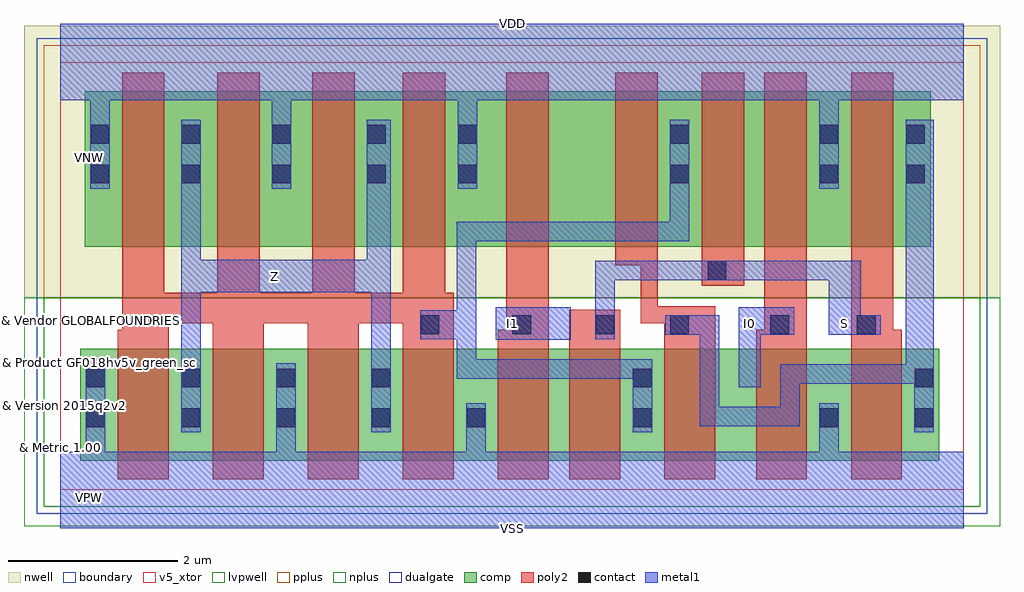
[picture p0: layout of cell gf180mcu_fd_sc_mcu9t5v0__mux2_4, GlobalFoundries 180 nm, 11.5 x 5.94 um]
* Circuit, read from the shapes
.subckt gf180mcu_fd_sc_mcu9t5v0__mux2_4 I0 I1 S VDD VNW VSS Z
XM1 Z n1 VSS VSUBS nfet_05v0 w=1.32u l=0.6u m=4
XM2 n2 I1 VSS VSUBS nfet_05v0 w=1.32u l=0.6u
XM3 n1 S n2 VSUBS nfet_05v0 w=1.32u l=0.6u
XM4 n3 n4 n1 VSUBS nfet_05v0 w=1.32u l=0.6u
XM5 VSS I0 n3 VSUBS nfet_05v0 w=1.32u l=0.6u
XM6 n4 S VSS VSUBS nfet_05v0 w=1.32u l=0.6u
XM7 Z n1 VDD VNW pfet_05v0 w=1.83u l=0.5u m=4
XM8 n5 I1 VDD VNW pfet_05v0 w=1.83u l=0.5u
XM9 n1 n4 n5 VNW pfet_05v0 w=1.83u l=0.5u
XM10 n6 S n1 VNW pfet_05v0 w=1.83u l=0.5u
XM11 VDD I0 n6 VNW pfet_05v0 w=1.83u l=0.5u
XM12 n4 S VDD VNW pfet_05v0 w=1.83u l=0.5u
.ends

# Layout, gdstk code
import gdstk
lib = gdstk.Library(unit=1e-6, precision=1e-09)
def R(c, l, rs):  # rectangles x0, y0, x1, y1
    for r in rs: c.add(gdstk.rectangle(r[:2], r[2:], *l))
def A(c, l, x, y, w, h, nx, ny, dx, dy):  # array of equal rectangles
    R(c, l, [(x+i*dx, y+j*dy, x+i*dx+w, y+j*dy+h) for i in range(nx) for j in range(ny)])
def P(c, l, *ps):  # polygons
    for p in ps: c.add(gdstk.Polygon(p, *l))
boundary = (0, 0)
nwell = (21, 0)
comp = (22, 0)
poly2 = (30, 0)
pplus = (31, 0)
nplus = (32, 0)
contact = (33, 0)
metal1 = (34, 0)
dualgate = (55, 0)
v5_xtor = (112, 1)
lvpwell = (204, 0)

gf180mcu_fd_sc_mcu9t5v0_ = lib.new_cell('gf180mcu_fd_sc_mcu9t5v0__mux2_4')
R(gf180mcu_fd_sc_mcu9t5v0_, boundary, [(0,0,10.64,5.04)])
R(gf180mcu_fd_sc_mcu9t5v0_, nwell, [(-0.43,2.265,11.07,5.47)])
R(gf180mcu_fd_sc_mcu9t5v0_, comp, [(0.235,0.345,10.355,1.665), (0.285,2.865,10.255,4.695)])
R(gf180mcu_fd_sc_mcu9t5v0_, poly2, [(5.995,0.125,6.595,2.125), (7.555,2.405,8.055,4.915)])
P(gf180mcu_fd_sc_mcu9t5v0_, poly2, [(0.675,0.125),(0.675,1.885),(0.725,1.885),(0.725,4.915),(1.225,4.915),(1.225,2.32),(1.845,2.32),(1.845,4.915),(2.345,4.915),(2.345,2.32),(2.965,2.32),(2.965,4.915),(3.465,4.915),(3.465,2.32),(4.035,2.32),(4.035,4.915),(4.535,4.915),(4.535,2.32),(4.635,2.32),(4.635,0.125),(4.035,0.125),(4.035,1.965),(3.515,1.965),(3.515,0.125),(2.915,0.125),(2.915,1.965),(2.395,1.965),(2.395,0.125),(1.795,0.125),(1.795,1.965),(1.275,1.965),(1.275,0.125)],
  [(5.155,0.125),(5.155,1.885),(5.255,1.885),(5.255,4.915),(5.755,4.915),(5.755,0.125)],
  [(7.115,0.125),(7.115,1.965),(6.835,1.965),(6.835,2.645),(6.535,2.645),(6.535,4.915),(7.035,4.915),(7.035,2.165),(7.715,2.165),(7.715,0.125)],
  [(8.195,0.125),(8.195,1.885),(8.295,1.885),(8.295,4.915),(8.795,4.915),(8.795,0.125)],
  [(9.315,0.125),(9.315,4.915),(9.815,4.915),(9.815,1.885),(9.915,1.885),(9.915,0.125)])
R(gf180mcu_fd_sc_mcu9t5v0_, pplus, [(-0.2,2.265,10.84,5.24)])
R(gf180mcu_fd_sc_mcu9t5v0_, nplus, [(-0.2,-0.2,10.84,2.265)])
A(gf180mcu_fd_sc_mcu9t5v0_, contact, 0.305, 0.74, 0.22, 0.22, 5, 1, 1.12, 0)
A(gf180mcu_fd_sc_mcu9t5v0_, contact, 0.305, 1.21, 0.22, 0.22, 4, 1, 1.12, 0)
A(gf180mcu_fd_sc_mcu9t5v0_, contact, 0.355, 3.61, 0.22, 0.22, 3, 2, 1.07, 0.47)
R(gf180mcu_fd_sc_mcu9t5v0_, contact, [(6.745,0.74,6.965,0.96), (8.945,0.74,9.165,0.96), (10.065,0.74,10.285,0.96), (6.745,1.21,6.965,1.43), (10.065,1.21,10.285,1.43), (4.245,1.835,4.465,2.055), (5.325,1.835,5.545,2.055), (6.305,1.835,6.525,2.055), (7.185,1.835,7.405,2.055), (8.365,1.835,8.585,2.055), (9.385,1.835,9.605,2.055), (7.625,2.475,7.845,2.695), (3.615,3.61,3.835,3.83), (4.685,3.61,4.905,3.83), (7.185,3.61,7.405,3.83), (8.945,3.61,9.165,3.83), (9.965,3.61,10.185,3.83), (3.615,4.08,3.835,4.3), (4.685,4.08,4.905,4.3), (7.185,4.08,7.405,4.3), (8.945,4.08,9.165,4.3), (9.965,4.08,10.185,4.3)])
R(gf180mcu_fd_sc_mcu9t5v0_, metal1, [(5.13,1.77,6.01,2.15)])
P(gf180mcu_fd_sc_mcu9t5v0_, metal1, [(1.42,0.68),(1.42,4.36),(1.65,4.36),(1.65,2.71),(3.61,2.71),(3.61,4.36),(3.89,4.36),(3.89,0.68),(3.66,0.68),(3.66,2.33),(1.65,2.33),(1.65,0.68)],
  [(6.74,0.68),(6.74,1.31),(4.67,1.31),(4.67,1.775),(4.24,1.775),(4.24,2.115),(4.67,2.115),(4.67,3.16),(7.18,3.16),(7.18,4.36),(7.41,4.36),(7.41,2.93),(4.9,2.93),(4.9,1.54),(6.97,1.54),(6.97,0.68)],
  [(7.99,1.21),(7.99,2.15),(8.645,2.15),(8.645,1.83),(8.25,1.83),(8.25,1.21)],
  [(6.3,1.775),(6.3,2.7),(9.43,2.7),(9.43,2.06),(9.665,2.06),(9.665,1.83),(9.05,1.83),(9.05,2.47),(6.53,2.47),(6.53,1.775)],
  [(10.06,0.68),(10.06,1.25),(8.71,1.25),(8.71,0.75),(7.53,0.75),(7.53,1.83),(7.125,1.83),(7.125,2.06),(7.76,2.06),(7.76,0.98),(8.48,0.98),(8.48,1.48),(9.96,1.48),(9.96,4.36),(10.29,4.36),(10.29,0.68)],
  [(0,-0.45),(0,0.45),(0.3,0.45),(0.3,1.49),(0.53,1.49),(0.53,0.45),(2.54,0.45),(2.54,1.49),(2.77,1.49),(2.77,0.45),(4.78,0.45),(4.78,1.02),(5.01,1.02),(5.01,0.45),(8.94,0.45),(8.94,1.02),(9.17,1.02),(9.17,0.45),(10.64,0.45),(10.64,-0.45)],
  [(0.35,3.55),(0.35,4.59),(0,4.59),(0,5.49),(10.64,5.49),(10.64,4.59),(9.17,4.59),(9.17,3.55),(8.94,3.55),(8.94,4.59),(4.91,4.59),(4.91,3.55),(4.68,3.55),(4.68,4.59),(2.72,4.59),(2.72,3.55),(2.49,3.55),(2.49,4.59),(0.58,4.59),(0.58,3.55)])
R(gf180mcu_fd_sc_mcu9t5v0_, dualgate, [(-0.28,-0.28,10.92,5.32)])
R(gf180mcu_fd_sc_mcu9t5v0_, v5_xtor, [(0,0,10.64,5.04)])
R(gf180mcu_fd_sc_mcu9t5v0_, lvpwell, [(-0.43,-0.43,11.07,2.265)])
gf180mcu_fd_sc_mcu9t5v0_.add(gdstk.Label('I0', (8.12,1.96), layer=34, texttype=10))
gf180mcu_fd_sc_mcu9t5v0_.add(gdstk.Label('I1', (5.32,1.96), layer=34, texttype=10))
gf180mcu_fd_sc_mcu9t5v0_.add(gdstk.Label('S', (9.24,1.96), layer=34, texttype=10))
gf180mcu_fd_sc_mcu9t5v0_.add(gdstk.Label('VDD', (5.32,5.49), layer=34, texttype=10))
gf180mcu_fd_sc_mcu9t5v0_.add(gdstk.Label('VSS', (5.32,-0.45), layer=34, texttype=10))
gf180mcu_fd_sc_mcu9t5v0_.add(gdstk.Label('Z', (2.52,2.52), layer=34, texttype=10))
gf180mcu_fd_sc_mcu9t5v0_.add(gdstk.Label('& Vendor GLOBALFOUNDRIES', (0,2), layer=63, texttype=63))
gf180mcu_fd_sc_mcu9t5v0_.add(gdstk.Label('& Product GF018hv5v_green_sc9', (0,1.5), layer=63, texttype=63))
gf180mcu_fd_sc_mcu9t5v0_.add(gdstk.Label('& Version 2015q2v2', (0,1), layer=63, texttype=63))
gf180mcu_fd_sc_mcu9t5v0_.add(gdstk.Label('& Metric 1.00', (0,0.5), layer=63, texttype=63))
gf180mcu_fd_sc_mcu9t5v0_.add(gdstk.Label('VNW', (0.345,3.92), layer=21, texttype=10))
gf180mcu_fd_sc_mcu9t5v0_.add(gdstk.Label('VPW', (0.34,-0.085), layer=204, texttype=10))

lib.write_gds('gf180mcu_fd_sc_mcu9t5v0__mux2_4.gds')
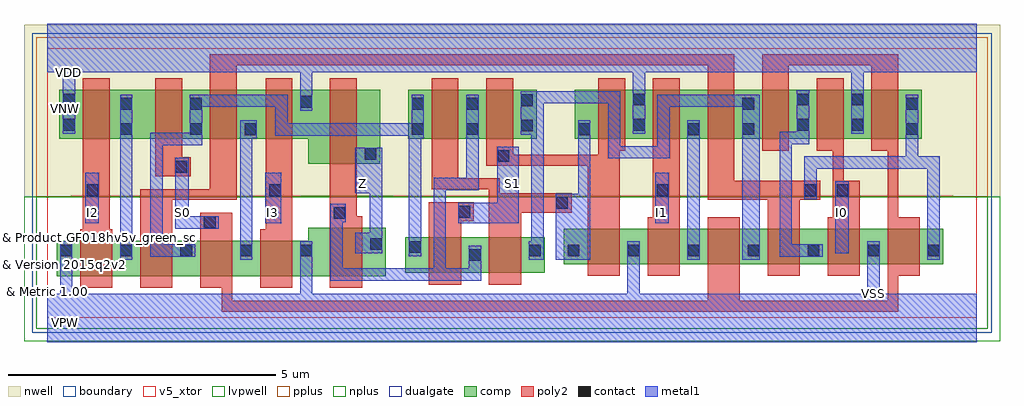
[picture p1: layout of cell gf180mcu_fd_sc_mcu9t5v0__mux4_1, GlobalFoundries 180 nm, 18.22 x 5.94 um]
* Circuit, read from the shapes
.subckt gf180mcu_fd_sc_mcu9t5v0__mux4_1 I0 I1 I2 I3 S0 S1 VDD VNW VSS Z
XM1 n1 I2 VSS VSUBS nfet_05v0 w=0.66u l=0.6u
XM2 n2 n3 n1 VSUBS nfet_05v0 w=0.66u l=0.6u
XM3 n4 S0 n2 VSUBS nfet_05v0 w=0.66u l=0.6u
XM4 VSS I3 n4 VSUBS nfet_05v0 w=0.66u l=0.6u
XM5 Z n5 VSS VSUBS nfet_05v0 w=0.9u l=0.6u
XM6 n5 S1 n2 VSUBS nfet_05v0 w=0.66u l=0.6u
XM7 n6 n7 n5 VSUBS nfet_05v0 w=0.66u l=0.6u
XM8 VSS S1 n7 VSUBS nfet_05v0 w=0.66u l=0.6u
XM9 n8 I1 VSS VSUBS nfet_05v0 w=0.66u l=0.6u
XM10 n6 S0 n8 VSUBS nfet_05v0 w=0.66u l=0.6u
XM11 n9 n3 n6 VSUBS nfet_05v0 w=0.66u l=0.6u
XM12 VSS I0 n9 VSUBS nfet_05v0 w=0.66u l=0.6u
XM13 n3 S0 VSS VSUBS nfet_05v0 w=0.66u l=0.6u
XM14 n1 I2 VDD VNW pfet_05v0 w=0.915u l=0.5u
XM15 n2 S0 n1 VNW pfet_05v0 w=0.915u l=0.5u
XM16 n4 n3 n2 VNW pfet_05v0 w=0.915u l=0.5u
XM17 VDD I3 n4 VNW pfet_05v0 w=0.915u l=0.5u
XM18 Z n5 VDD VNW pfet_05v0 w=1.38u l=0.5u
XM19 n5 n7 n2 VNW pfet_05v0 w=0.915u l=0.5u
XM20 n6 S1 n5 VNW pfet_05v0 w=0.915u l=0.5u
XM21 VDD S1 n7 VNW pfet_05v0 w=0.915u l=0.5u
XM22 n8 I1 VDD VNW pfet_05v0 w=0.915u l=0.5u
XM23 n6 n3 n8 VNW pfet_05v0 w=0.915u l=0.5u
XM24 n9 S0 n6 VNW pfet_05v0 w=0.915u l=0.5u
XM25 VDD I0 n9 VNW pfet_05v0 w=0.915u l=0.5u
XM26 n3 S0 VDD VNW pfet_05v0 w=0.915u l=0.5u
.ends

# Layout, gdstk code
import gdstk
lib = gdstk.Library(unit=1e-6, precision=1e-09)
def R(c, l, rs):  # rectangles x0, y0, x1, y1
    for r in rs: c.add(gdstk.rectangle(r[:2], r[2:], *l))
def A(c, l, x, y, w, h, nx, ny, dx, dy):  # array of equal rectangles
    R(c, l, [(x+i*dx, y+j*dy, x+i*dx+w, y+j*dy+h) for i in range(nx) for j in range(ny)])
def P(c, l, *ps):  # polygons
    for p in ps: c.add(gdstk.Polygon(p, *l))
boundary = (0, 0)
nwell = (21, 0)
comp = (22, 0)
poly2 = (30, 0)
pplus = (31, 0)
nplus = (32, 0)
contact = (33, 0)
metal1 = (34, 0)
dualgate = (55, 0)
v5_xtor = (112, 1)
lvpwell = (204, 0)

gf180mcu_fd_sc_mcu9t5v0_ = lib.new_cell('gf180mcu_fd_sc_mcu9t5v0__mux4_1')
R(gf180mcu_fd_sc_mcu9t5v0_, boundary, [(0,0,17.36,5.04)])
P(gf180mcu_fd_sc_mcu9t5v0_, nwell, [(-0.43,2.265),(-0.43,5.47),(17.79,5.47),(17.79,2.265),(16.93,2.265),(16.93,2.28),(0.43,2.28),(0.43,2.265)])
R(gf180mcu_fd_sc_mcu9t5v0_, comp, [(6.69,0.845,9.29,1.505), (9.65,1.005,16.73,1.665), (6.74,3.345,9.14,4.26), (9.85,3.345,16.33,4.26)])
P(gf180mcu_fd_sc_mcu9t5v0_, comp, [(4.88,2.88),(4.88,3.345),(0.23,3.345),(0.23,4.26),(6.22,4.26),(6.22,2.88)],
  [(0.18,0.78),(0.18,1.44),(4.88,1.44),(4.88,1.68),(6.32,1.68),(6.32,0.78)])
P(gf180mcu_fd_sc_mcu9t5v0_, poly2, [(0.62,0.56),(0.62,1.66),(0.67,1.66),(0.67,4.48),(1.17,4.48),(1.17,1.66),(1.22,1.66),(1.22,0.56)],
  [(2.02,2.645),(2.02,4.48),(2.52,4.48),(2.52,3.005),(2.685,3.005),(2.685,2.645)],
  [(3.98,0.56),(3.98,1.66),(4.08,1.66),(4.08,4.48),(4.58,4.48),(4.58,0.56)],
  [(5.28,0.56),(5.28,4.48),(5.78,4.48),(5.78,1.9),(5.88,1.9),(5.88,0.56)],
  [(7.13,0.625),(7.13,2.165),(7.97,2.165),(7.97,1.805),(7.73,1.805),(7.73,0.625)],
  [(8.25,0.625),(8.25,2.405),(7.18,2.405),(7.18,4.48),(7.68,4.48),(7.68,2.605),(8.45,2.605),(8.45,2.325),(9.795,2.325),(9.795,1.965),(8.85,1.965),(8.85,0.625)],
  [(10.09,0.785),(10.09,2.845),(8.2,2.845),(8.2,4.48),(8.7,4.48),(8.7,3.045),(10.29,3.045),(10.29,4.48),(10.79,4.48),(10.79,3.125),(10.69,3.125),(10.69,0.785)],
  [(11.21,0.785),(11.21,1.885),(11.31,1.885),(11.31,4.48),(11.81,4.48),(11.81,0.785)],
  [(1.74,0.56),(1.74,2.405),(3.04,2.405),(3.04,4.92),(12.83,4.92),(12.83,2.565),(14.43,2.565),(14.43,2.205),(14.05,2.205),(14.05,0.785),(13.45,0.785),(13.45,2.205),(12.33,2.205),(12.33,4.72),(3.54,4.72),(3.54,2.205),(2.34,2.205),(2.34,0.56)],
  [(14.57,0.785),(14.57,1.885),(14.67,1.885),(14.67,3.125),(14.37,3.125),(14.37,4.48),(14.87,4.48),(14.87,2.565),(15.17,2.565),(15.17,0.785)],
  [(3.26,0.12),(3.26,0.56),(2.86,0.56),(2.86,1.965),(3.46,1.965),(3.46,0.32),(12.33,0.32),(12.33,1.885),(12.93,1.885),(12.93,0.32),(15.69,0.32),(15.69,3.125),(15.39,3.125),(15.39,4.72),(13.85,4.72),(13.85,3.125),(13.35,3.125),(13.35,4.92),(15.89,4.92),(15.89,1.885),(16.29,1.885),(16.29,0.785),(15.89,0.785),(15.89,0.12)])
R(gf180mcu_fd_sc_mcu9t5v0_, pplus, [(-0.2,2.265,17.56,5.24)])
R(gf180mcu_fd_sc_mcu9t5v0_, nplus, [(-0.2,-0.2,17.56,2.265)])
A(gf180mcu_fd_sc_mcu9t5v0_, contact, 0.25, 1.15, 0.22, 0.22, 5, 1, 1.12, 0)
A(gf180mcu_fd_sc_mcu9t5v0_, contact, 9.72, 1.15, 0.22, 0.22, 7, 1, 1.12, 0)
R(gf180mcu_fd_sc_mcu9t5v0_, contact, [(7.88,1.065,8.1,1.285), (9,1.15,9.22,1.37), (6.76,1.215,6.98,1.435), (6.03,1.27,6.25,1.49), (2.93,1.675,3.15,1.895), (5.35,1.85,5.57,2.07), (7.68,1.875,7.9,2.095), (9.505,2.035,9.725,2.255), (0.74,2.275,0.96,2.495), (4.15,2.275,4.37,2.495), (11.38,2.275,11.6,2.495), (14.14,2.275,14.36,2.495), (14.74,2.275,14.96,2.495), (2.395,2.715,2.615,2.935), (8.41,2.915,8.63,3.135), (5.93,2.95,6.15,3.17), (3.69,3.415,3.91,3.635), (9.92,3.415,10.14,3.635), (11.96,3.415,12.18,3.635), (1.37,3.42,1.59,3.64), (2.67,3.42,2.89,3.64), (6.81,3.42,7.03,3.64), (7.83,3.42,8.05,3.64), (12.98,3.42,13.2,3.64), (16.04,3.42,16.26,3.64), (8.85,3.485,9.07,3.705), (0.3,3.5,0.52,3.72), (10.94,3.5,11.16,3.72), (14,3.5,14.22,3.72), (15.02,3.5,15.24,3.72), (1.37,3.89,1.59,4.11), (2.67,3.89,2.89,4.11), (6.81,3.89,7.03,4.11), (7.83,3.89,8.05,4.11), (12.98,3.89,13.2,4.11), (16.04,3.89,16.26,4.11), (4.73,3.925,4.95,4.145), (8.85,3.955,9.07,4.175), (0.3,3.97,0.52,4.19), (10.94,3.97,11.16,4.19), (14,3.97,14.22,4.19), (15.02,3.97,15.24,4.19)])
R(gf180mcu_fd_sc_mcu9t5v0_, metal1, [(1.365,1.09,1.595,4.17), (11.955,1.09,12.185,3.695), (14.71,1.21,14.97,2.555), (0.71,1.77,0.97,2.71), (4.07,1.77,4.375,2.71), (11.35,1.77,11.61,2.71)])
P(gf180mcu_fd_sc_mcu9t5v0_, metal1, [(2.39,1.67),(2.39,2.995),(2.65,2.995),(2.65,1.9),(3.21,1.9),(3.21,1.67)],
  [(3.605,1.09),(3.605,3.695),(3.915,3.695),(3.915,3.355),(3.835,3.355),(3.835,1.09)],
  [(5.75,1.21),(5.75,1.59),(6.025,1.59),(6.025,2.33),(5.75,2.33),(5.75,3.175),(6.255,3.175),(6.255,1.21)],
  [(1.93,1.145),(1.93,3.455),(2.665,3.455),(2.665,4.17),(4.495,4.17),(4.495,3.635),(6.805,3.635),(6.805,4.17),(7.035,4.17),(7.035,3.36),(6.985,3.36),(6.985,1.155),(6.755,1.155),(6.755,3.405),(4.265,3.405),(4.265,3.94),(2.895,3.94),(2.895,3.225),(2.16,3.225),(2.16,1.375),(2.77,1.375),(2.77,1.145)],
  [(5.29,0.695),(5.29,2.13),(5.575,2.13),(5.575,1.79),(5.52,1.79),(5.52,0.925),(7.215,0.925),(7.215,2.615),(7.825,2.615),(7.825,4.17),(8.055,4.17),(8.055,2.385),(7.445,2.385),(7.445,0.925),(7.875,0.925),(7.875,1.345),(8.105,1.345),(8.105,0.695)],
  [(7.675,1.77),(7.675,2.155),(8.405,2.155),(8.405,3.195),(8.81,3.195),(8.81,1.77)],
  [(9.5,1.09),(9.5,2.315),(9.915,2.315),(9.915,3.695),(10.145,3.695),(10.145,1.09)],
  [(8.995,1.09),(8.995,1.43),(9.04,1.43),(9.04,3.425),(8.845,3.425),(8.845,4.235),(10.705,4.235),(10.705,3.21),(11.395,3.21),(11.395,4.17),(13.305,4.17),(13.305,1.09),(12.975,1.09),(12.975,3.94),(11.625,3.94),(11.625,2.98),(10.475,2.98),(10.475,4.005),(9.27,4.005),(9.27,1.09)],
  [(13.675,1.145),(13.675,3.475),(13.995,3.475),(13.995,4.25),(14.225,4.25),(14.225,3.245),(13.905,3.245),(13.905,1.375),(14.48,1.375),(14.48,1.145)],
  [(16.435,1.09),(16.435,2.785),(14.365,2.785),(14.365,2.215),(14.135,2.215),(14.135,3.015),(16.035,3.015),(16.035,4.17),(16.265,4.17),(16.265,3.015),(16.665,3.015),(16.665,1.09)],
  [(0,-0.45),(0,0.45),(0.245,0.45),(0.245,1.43),(0.475,1.43),(0.475,0.45),(4.725,0.45),(4.725,1.43),(4.955,1.43),(4.955,0.45),(10.835,0.45),(10.835,1.43),(11.065,1.43),(11.065,0.45),(15.315,0.45),(15.315,1.43),(15.545,1.43),(15.545,0.45),(17.36,0.45),(17.36,-0.45)],
  [(0.295,3.44),(0.295,4.59),(0,4.59),(0,5.49),(17.36,5.49),(17.36,4.59),(15.245,4.59),(15.245,3.44),(15.015,3.44),(15.015,4.59),(11.165,4.59),(11.165,3.44),(10.935,3.44),(10.935,4.59),(4.955,4.59),(4.955,3.865),(4.725,3.865),(4.725,4.59),(0.525,4.59),(0.525,3.44)])
R(gf180mcu_fd_sc_mcu9t5v0_, dualgate, [(-0.28,-0.28,17.64,5.32)])
R(gf180mcu_fd_sc_mcu9t5v0_, v5_xtor, [(0,0,17.36,5.04)])
P(gf180mcu_fd_sc_mcu9t5v0_, lvpwell, [(-0.43,-0.43),(-0.43,2.265),(4.745,2.265),(4.745,2.28),(6.455,2.28),(6.455,2.265),(17.79,2.265),(17.79,-0.43)])
gf180mcu_fd_sc_mcu9t5v0_.add(gdstk.Label('I0', (14.84,1.96), layer=34, texttype=10))
gf180mcu_fd_sc_mcu9t5v0_.add(gdstk.Label('I1', (11.48,1.96), layer=34, texttype=10))
gf180mcu_fd_sc_mcu9t5v0_.add(gdstk.Label('I2', (0.84,1.96), layer=34, texttype=10))
gf180mcu_fd_sc_mcu9t5v0_.add(gdstk.Label('I3', (4.2,1.96), layer=34, texttype=10))
gf180mcu_fd_sc_mcu9t5v0_.add(gdstk.Label('S0', (2.52,1.96), layer=34, texttype=10))
gf180mcu_fd_sc_mcu9t5v0_.add(gdstk.Label('S1', (8.68,2.52), layer=34, texttype=10))
gf180mcu_fd_sc_mcu9t5v0_.add(gdstk.Label('VDD', (0.41,4.59), layer=34, texttype=10))
gf180mcu_fd_sc_mcu9t5v0_.add(gdstk.Label('VSS', (15.43,0.45), layer=34, texttype=10))
gf180mcu_fd_sc_mcu9t5v0_.add(gdstk.Label('Z', (5.88,2.52), layer=34, texttype=10))
gf180mcu_fd_sc_mcu9t5v0_.add(gdstk.Label('& Vendor GLOBALFOUNDRIES', (0,2), layer=63, texttype=63))
gf180mcu_fd_sc_mcu9t5v0_.add(gdstk.Label('& Product GF018hv5v_green_sc9', (0,1.5), layer=63, texttype=63))
gf180mcu_fd_sc_mcu9t5v0_.add(gdstk.Label('& Version 2015q2v2', (0,1), layer=63, texttype=63))
gf180mcu_fd_sc_mcu9t5v0_.add(gdstk.Label('& Metric 1.00', (0,0.5), layer=63, texttype=63))
gf180mcu_fd_sc_mcu9t5v0_.add(gdstk.Label('VNW', (0.345,3.92), layer=21, texttype=10))
gf180mcu_fd_sc_mcu9t5v0_.add(gdstk.Label('VPW', (0.34,-0.085), layer=204, texttype=10))

lib.write_gds('gf180mcu_fd_sc_mcu9t5v0__mux4_1.gds')
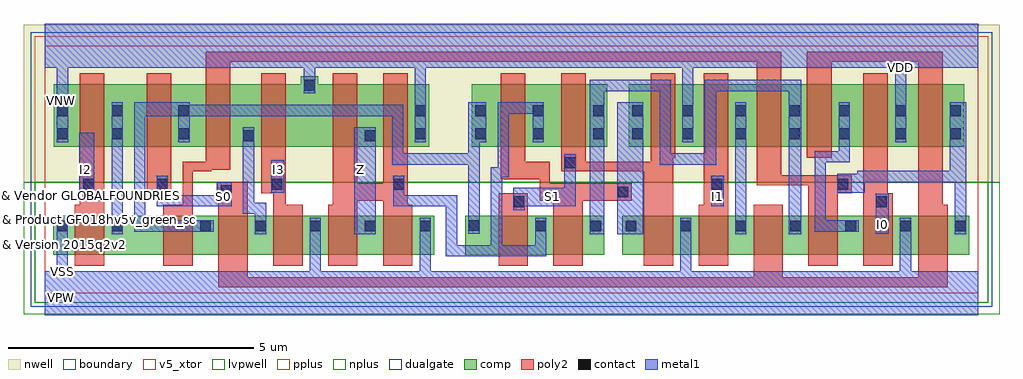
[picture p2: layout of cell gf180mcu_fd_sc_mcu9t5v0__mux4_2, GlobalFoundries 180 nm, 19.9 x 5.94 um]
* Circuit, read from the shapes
.subckt gf180mcu_fd_sc_mcu9t5v0__mux4_2 I0 I1 I2 I3 S0 S1 VDD VNW VSS Z
XM1 n1 I2 VSS VSUBS nfet_05v0 w=0.8u l=0.6u
XM2 n2 n3 n1 VSUBS nfet_05v0 w=0.8u l=0.6u
XM3 n4 S0 n2 VSUBS nfet_05v0 w=0.8u l=0.6u
XM4 VSS I3 n4 VSUBS nfet_05v0 w=0.8u l=0.6u
XM5 Z n5 VSS VSUBS nfet_05v0 w=0.8u l=0.6u m=2
XM6 n5 S1 n2 VSUBS nfet_05v0 w=0.8u l=0.6u
XM7 n6 n7 n5 VSUBS nfet_05v0 w=0.8u l=0.6u
XM8 VSS S1 n7 VSUBS nfet_05v0 w=0.8u l=0.6u
XM9 n8 I1 VSS VSUBS nfet_05v0 w=0.8u l=0.6u
XM10 n6 S0 n8 VSUBS nfet_05v0 w=0.8u l=0.6u
XM11 n9 n3 n6 VSUBS nfet_05v0 w=0.8u l=0.6u
XM12 VSS I0 n9 VSUBS nfet_05v0 w=0.8u l=0.6u
XM13 n3 S0 VSS VSUBS nfet_05v0 w=0.8u l=0.6u
XM14 n1 I2 VDD VNW pfet_05v0 w=1.28u l=0.5u
XM15 n2 S0 n1 VNW pfet_05v0 w=1.28u l=0.5u
XM16 n4 n3 n2 VNW pfet_05v0 w=1.28u l=0.5u
XM17 VDD I3 n4 VNW pfet_05v0 w=1.28u l=0.5u
XM18 Z n5 VDD VNW pfet_05v0 w=1.28u l=0.5u m=2
XM19 n5 n7 n2 VNW pfet_05v0 w=1.28u l=0.5u
XM20 n6 S1 n5 VNW pfet_05v0 w=1.28u l=0.5u
XM21 VDD S1 n7 VNW pfet_05v0 w=1.28u l=0.5u
XM22 n8 I1 VDD VNW pfet_05v0 w=1.28u l=0.5u
XM23 n6 n3 n8 VNW pfet_05v0 w=1.28u l=0.5u
XM24 n9 S0 n6 VNW pfet_05v0 w=1.28u l=0.5u
XM25 VDD I0 n9 VNW pfet_05v0 w=1.28u l=0.5u
XM26 n3 S0 VDD VNW pfet_05v0 w=1.28u l=0.5u
.ends

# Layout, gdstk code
import gdstk
lib = gdstk.Library(unit=1e-6, precision=1e-09)
def R(c, l, rs):  # rectangles x0, y0, x1, y1
    for r in rs: c.add(gdstk.rectangle(r[:2], r[2:], *l))
def A(c, l, x, y, w, h, nx, ny, dx, dy):  # array of equal rectangles
    R(c, l, [(x+i*dx, y+j*dy, x+i*dx+w, y+j*dy+h) for i in range(nx) for j in range(ny)])
def P(c, l, *ps):  # polygons
    for p in ps: c.add(gdstk.Polygon(p, *l))
boundary = (0, 0)
nwell = (21, 0)
comp = (22, 0)
poly2 = (30, 0)
pplus = (31, 0)
nplus = (32, 0)
contact = (33, 0)
metal1 = (34, 0)
dualgate = (55, 0)
v5_xtor = (112, 1)
lvpwell = (204, 0)

gf180mcu_fd_sc_mcu9t5v0_ = lib.new_cell('gf180mcu_fd_sc_mcu9t5v0__mux4_2')
R(gf180mcu_fd_sc_mcu9t5v0_, boundary, [(0,0,19.04,5.04)])
R(gf180mcu_fd_sc_mcu9t5v0_, nwell, [(-0.43,2.265,19.47,5.47)])
R(gf180mcu_fd_sc_mcu9t5v0_, comp, [(0.18,0.78,7.94,1.58), (8.575,0.78,11.415,1.58), (11.775,0.78,18.855,1.58), (8.71,2.98,11.475,4.26), (11.915,2.98,18.755,4.26)])
P(gf180mcu_fd_sc_mcu9t5v0_, comp, [(0.185,2.98),(0.185,4.26),(5.22,4.26),(5.22,4.42),(5.58,4.42),(5.58,4.26),(7.84,4.26),(7.84,2.98)])
R(gf180mcu_fd_sc_mcu9t5v0_, poly2, [(9.255,0.56,9.855,2.04), (2.08,2.04,2.58,4.48)])
P(gf180mcu_fd_sc_mcu9t5v0_, poly2, [(0.62,0.56),(0.62,1.8),(0.72,1.8),(0.72,4.48),(1.22,4.48),(1.22,0.56)],
  [(4.66,0.56),(4.66,2.04),(4.42,2.04),(4.42,4.48),(4.92,4.48),(4.92,1.8),(5.26,1.8),(5.26,0.56)],
  [(5.78,0.56),(5.78,1.8),(5.88,1.8),(5.88,4.48),(6.38,4.48),(6.38,2.24),(6.9,2.24),(6.9,4.48),(7.4,4.48),(7.4,1.8),(7.5,1.8),(7.5,0.56),(6.9,0.56),(6.9,1.88),(6.38,1.88),(6.38,0.56)],
  [(10.375,0.56),(10.375,1.88),(10.095,1.88),(10.095,2.32),(9.305,2.32),(9.305,4.48),(9.805,4.48),(9.805,2.68),(10.295,2.68),(10.295,2.24),(11.975,2.24),(11.975,1.88),(10.975,1.88),(10.975,0.56)],
  [(12.215,0.56),(12.215,2.48),(10.535,2.48),(10.535,4.48),(11.035,4.48),(11.035,2.68),(12.355,2.68),(12.355,4.48),(12.855,4.48),(12.855,2.76),(12.815,2.76),(12.815,0.56)],
  [(13.335,0.56),(13.335,1.8),(13.435,1.8),(13.435,4.48),(13.935,4.48),(13.935,0.56)],
  [(2.42,0.56),(2.42,1.8),(2.82,1.8),(2.82,2.68),(3.29,2.68),(3.29,4.92),(15.025,4.92),(15.025,2.4),(16.455,2.4),(16.455,2.04),(16.175,2.04),(16.175,0.56),(15.575,0.56),(15.575,2.2),(14.525,2.2),(14.525,4.72),(3.79,4.72),(3.79,2.51),(3.4,2.51),(3.4,2.48),(3.02,2.48),(3.02,0.56)],
  [(16.695,0.56),(16.695,4.48),(17.195,4.48),(17.195,2.04),(17.295,2.04),(17.295,0.56)],
  [(3.54,0.12),(3.54,1.91),(3.52,1.91),(3.52,2.27),(4.14,2.27),(4.14,0.32),(14.455,0.32),(14.455,1.8),(15.055,1.8),(15.055,0.32),(17.815,0.32),(17.815,4.72),(16.045,4.72),(16.045,2.76),(15.545,2.76),(15.545,4.92),(18.315,4.92),(18.315,1.8),(18.415,1.8),(18.415,0.12)])
R(gf180mcu_fd_sc_mcu9t5v0_, pplus, [(-0.2,2.265,19.24,5.24)])
R(gf180mcu_fd_sc_mcu9t5v0_, nplus, [(-0.2,-0.2,19.24,2.265)])
A(gf180mcu_fd_sc_mcu9t5v0_, contact, 3.17, 1.26, 0.22, 0.22, 5, 1, 1.12, 0)
A(gf180mcu_fd_sc_mcu9t5v0_, contact, 11.845, 1.26, 0.22, 0.22, 7, 1, 1.12, 0)
R(gf180mcu_fd_sc_mcu9t5v0_, contact, [(0.25,1.26,0.47,1.48), (1.37,1.26,1.59,1.48), (10.005,1.26,10.225,1.48), (11.125,1.26,11.345,1.48), (8.645,1.27,8.865,1.49), (9.565,1.75,9.785,1.97), (16.955,1.75,17.175,1.97), (11.685,1.95,11.905,2.17), (3.59,1.98,3.81,2.2), (0.79,2.11,1.01,2.33), (2.29,2.11,2.51,2.33), (4.63,2.11,4.85,2.33), (7.11,2.11,7.33,2.33), (13.595,2.11,13.815,2.33), (16.165,2.11,16.385,2.33), (10.605,2.55,10.825,2.77), (4.05,3.1,4.27,3.32), (6.53,3.1,6.75,3.32), (0.255,3.14,0.475,3.36), (1.37,3.14,1.59,3.36), (2.73,3.14,2.95,3.36), (7.55,3.14,7.77,3.36), (8.78,3.14,9,3.36), (9.955,3.14,10.175,3.36), (11.185,3.14,11.405,3.36), (11.985,3.14,12.205,3.36), (13.005,3.14,13.225,3.36), (14.085,3.14,14.305,3.36), (15.175,3.14,15.395,3.36), (16.195,3.14,16.415,3.36), (17.345,3.14,17.565,3.36), (18.465,3.14,18.685,3.36), (0.255,3.61,0.475,3.83), (1.37,3.61,1.59,3.83), (2.73,3.61,2.95,3.83), (7.55,3.61,7.77,3.83), (8.78,3.61,9,3.83), (9.955,3.61,10.175,3.83), (11.185,3.61,11.405,3.83), (11.985,3.61,12.205,3.83), (13.005,3.61,13.225,3.83), (14.085,3.61,14.305,3.83), (15.175,3.61,15.395,3.83), (16.195,3.61,16.415,3.83), (17.345,3.61,17.565,3.83), (18.465,3.61,18.685,3.83), (5.29,4.13,5.51,4.35)])
R(gf180mcu_fd_sc_mcu9t5v0_, metal1, [(1.365,1.2,1.595,3.89), (6.31,1.2,6.755,3.38), (11.68,1.2,12.21,3.89), (14.08,1.2,14.31,3.89), (16.95,1.21,17.21,2.03), (13.59,1.77,13.85,2.39), (0.71,2.05,1.015,3.27), (4.625,2.05,4.89,2.71)])
P(gf180mcu_fd_sc_mcu9t5v0_, metal1, [(2.285,1.77),(2.285,2.39),(2.515,2.39),(2.515,2),(3.51,2),(3.51,2.26),(3.815,2.26),(3.815,1.77)],
  [(4.285,1.2),(4.285,1.615),(4.045,1.615),(4.045,3.38),(4.275,3.38),(4.275,1.845),(4.515,1.845),(4.515,1.2)],
  [(8.64,1.21),(8.64,2.62),(7.085,2.62),(7.085,3.61),(2.955,3.61),(2.955,3.08),(2.725,3.08),(2.725,3.61),(2.055,3.61),(2.055,1.485),(3.45,1.485),(3.45,1.255),(1.825,1.255),(1.825,3.89),(2.955,3.89),(2.955,3.84),(7.315,3.84),(7.315,2.85),(8.64,2.85),(8.64,3.89),(9.005,3.89),(9.005,3.08),(8.87,3.08),(8.87,1.21)],
  [(8.18,0.75),(8.18,1.77),(7.105,1.77),(7.105,2.39),(7.335,2.39),(7.335,2),(8.41,2),(8.41,0.98),(9.1,0.98),(9.1,2.57),(9.235,2.57),(9.235,3.89),(10.18,3.89),(10.18,3.08),(9.95,3.08),(9.95,3.66),(9.465,3.66),(9.465,2.36),(9.33,2.36),(9.33,0.98),(10,0.98),(10,1.54),(10.23,1.54),(10.23,0.75)],
  [(9.56,1.69),(9.56,2.15),(10.6,2.15),(10.6,2.83),(10.83,2.83),(10.83,1.77),(9.79,1.77),(9.79,1.69)],
  [(11.12,1.2),(11.12,4.35),(12.77,4.35),(12.77,2.85),(13.46,2.85),(13.46,4.35),(15.43,4.35),(15.43,1.2),(15.17,1.2),(15.17,4.12),(13.69,4.12),(13.69,2.62),(12.54,2.62),(12.54,4.12),(11.41,4.12),(11.41,1.2)],
  [(15.7,1.255),(15.7,2.895),(16.19,2.895),(16.19,3.89),(16.42,3.89),(16.42,2.665),(15.93,2.665),(15.93,1.485),(16.605,1.485),(16.605,1.255)],
  [(18.56,1.2),(18.56,2.26),(16.72,2.26),(16.72,2.05),(16.16,2.05),(16.16,2.435),(16.57,2.435),(16.57,2.49),(18.46,2.49),(18.46,3.89),(18.79,3.89),(18.79,1.2)],
  [(0,-0.45),(0,0.45),(0.245,0.45),(0.245,1.54),(0.475,1.54),(0.475,0.45),(5.405,0.45),(5.405,1.54),(5.635,1.54),(5.635,0.45),(7.645,0.45),(7.645,1.54),(7.875,1.54),(7.875,0.45),(12.96,0.45),(12.96,1.54),(13.19,1.54),(13.19,0.45),(17.44,0.45),(17.44,1.54),(17.67,1.54),(17.67,0.45),(19.04,0.45),(19.04,-0.45)],
  [(0.25,3.08),(0.25,4.59),(0,4.59),(0,5.49),(19.04,5.49),(19.04,4.59),(17.57,4.59),(17.57,3.08),(17.34,3.08),(17.34,4.59),(13.23,4.59),(13.23,3.08),(13,3.08),(13,4.59),(7.775,4.59),(7.775,3.08),(7.545,3.08),(7.545,4.59),(5.515,4.59),(5.515,4.07),(5.285,4.07),(5.285,4.59),(0.48,4.59),(0.48,3.08)])
R(gf180mcu_fd_sc_mcu9t5v0_, dualgate, [(-0.28,-0.28,19.32,5.32)])
R(gf180mcu_fd_sc_mcu9t5v0_, v5_xtor, [(0,0,19.04,5.04)])
R(gf180mcu_fd_sc_mcu9t5v0_, lvpwell, [(-0.43,-0.43,19.47,2.265)])
gf180mcu_fd_sc_mcu9t5v0_.add(gdstk.Label('I0', (17.08,1.4), layer=34, texttype=10))
gf180mcu_fd_sc_mcu9t5v0_.add(gdstk.Label('I1', (13.72,1.96), layer=34, texttype=10))
gf180mcu_fd_sc_mcu9t5v0_.add(gdstk.Label('I2', (0.84,2.52), layer=34, texttype=10))
gf180mcu_fd_sc_mcu9t5v0_.add(gdstk.Label('I3', (4.76,2.52), layer=34, texttype=10))
gf180mcu_fd_sc_mcu9t5v0_.add(gdstk.Label('S0', (3.64,1.96), layer=34, texttype=10))
gf180mcu_fd_sc_mcu9t5v0_.add(gdstk.Label('S1', (10.36,1.96), layer=34, texttype=10))
gf180mcu_fd_sc_mcu9t5v0_.add(gdstk.Label('VDD', (17.455,4.59), layer=34, texttype=10))
gf180mcu_fd_sc_mcu9t5v0_.add(gdstk.Label('VSS', (0.36,0.45), layer=34, texttype=10))
gf180mcu_fd_sc_mcu9t5v0_.add(gdstk.Label('Z', (6.44,2.52), layer=34, texttype=10))
gf180mcu_fd_sc_mcu9t5v0_.add(gdstk.Label('& Vendor GLOBALFOUNDRIES', (0,2), layer=63, texttype=63))
gf180mcu_fd_sc_mcu9t5v0_.add(gdstk.Label('& Product GF018hv5v_green_sc9', (0,1.5), layer=63, texttype=63))
gf180mcu_fd_sc_mcu9t5v0_.add(gdstk.Label('& Version 2015q2v2', (0,1), layer=63, texttype=63))
gf180mcu_fd_sc_mcu9t5v0_.add(gdstk.Label('& Metric 1.00', (0,0.5), layer=63, texttype=63))
gf180mcu_fd_sc_mcu9t5v0_.add(gdstk.Label('VNW', (0.345,3.92), layer=21, texttype=10))
gf180mcu_fd_sc_mcu9t5v0_.add(gdstk.Label('VPW', (0.34,-0.085), layer=204, texttype=10))

lib.write_gds('gf180mcu_fd_sc_mcu9t5v0__mux4_2.gds')
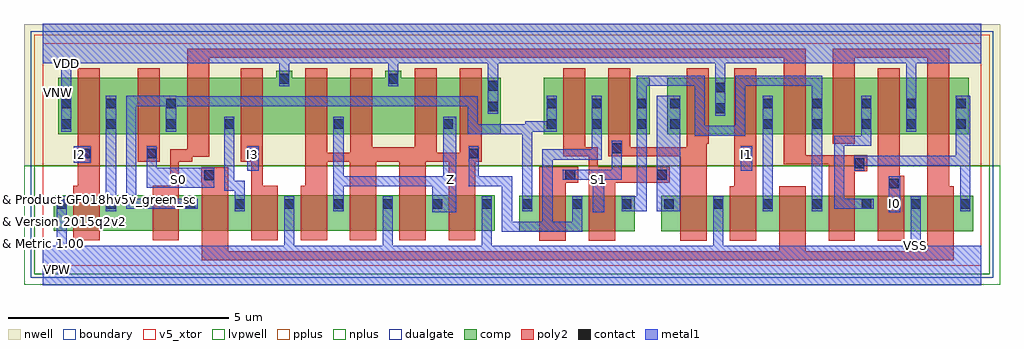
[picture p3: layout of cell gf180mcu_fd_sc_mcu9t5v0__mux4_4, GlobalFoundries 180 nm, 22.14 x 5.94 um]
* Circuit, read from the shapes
.subckt gf180mcu_fd_sc_mcu9t5v0__mux4_4 I0 I1 I2 I3 S0 S1 VDD VNW VSS Z
XM1 n1 I2 VSS VSUBS nfet_05v0 w=0.8u l=0.6u
XM2 n2 n3 n1 VSUBS nfet_05v0 w=0.8u l=0.6u
XM3 n4 S0 n2 VSUBS nfet_05v0 w=0.8u l=0.6u
XM4 VSS I3 n4 VSUBS nfet_05v0 w=0.8u l=0.6u
XM5 Z n5 VSS VSUBS nfet_05v0 w=0.8u l=0.6u m=4
XM6 n5 S1 n2 VSUBS nfet_05v0 w=0.8u l=0.6u
XM7 n6 n7 n5 VSUBS nfet_05v0 w=0.8u l=0.6u
XM8 VSS S1 n7 VSUBS nfet_05v0 w=0.8u l=0.6u
XM9 n8 I1 VSS VSUBS nfet_05v0 w=0.8u l=0.6u
XM10 n6 S0 n8 VSUBS nfet_05v0 w=0.8u l=0.6u
XM11 n9 n3 n6 VSUBS nfet_05v0 w=0.8u l=0.6u
XM12 VSS I0 n9 VSUBS nfet_05v0 w=0.8u l=0.6u
XM13 n3 S0 VSS VSUBS nfet_05v0 w=0.8u l=0.6u
XM14 n1 I2 VDD VNW pfet_05v0 w=1.28u l=0.5u
XM15 n2 S0 n1 VNW pfet_05v0 w=1.28u l=0.5u
XM16 n4 n3 n2 VNW pfet_05v0 w=1.28u l=0.5u
XM17 VDD I3 n4 VNW pfet_05v0 w=1.28u l=0.5u
XM18 Z n5 VDD VNW pfet_05v0 w=1.28u l=0.5u m=4
XM19 n5 n7 n2 VNW pfet_05v0 w=1.28u l=0.5u
XM20 n6 S1 n5 VNW pfet_05v0 w=1.28u l=0.5u
XM21 VDD S1 n7 VNW pfet_05v0 w=1.28u l=0.5u
XM22 n8 I1 VDD VNW pfet_05v0 w=1.28u l=0.5u
XM23 n6 n3 n8 VNW pfet_05v0 w=1.28u l=0.5u
XM24 n9 S0 n6 VNW pfet_05v0 w=1.28u l=0.5u
XM25 VDD I0 n9 VNW pfet_05v0 w=1.28u l=0.5u
XM26 n3 S0 VDD VNW pfet_05v0 w=1.28u l=0.5u
.ends

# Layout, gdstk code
import gdstk
lib = gdstk.Library(unit=1e-6, precision=1e-09)
def R(c, l, rs):  # rectangles x0, y0, x1, y1
    for r in rs: c.add(gdstk.rectangle(r[:2], r[2:], *l))
def A(c, l, x, y, w, h, nx, ny, dx, dy):  # array of equal rectangles
    R(c, l, [(x+i*dx, y+j*dy, x+i*dx+w, y+j*dy+h) for i in range(nx) for j in range(ny)])
def P(c, l, *ps):  # polygons
    for p in ps: c.add(gdstk.Polygon(p, *l))
boundary = (0, 0)
nwell = (21, 0)
comp = (22, 0)
poly2 = (30, 0)
pplus = (31, 0)
nplus = (32, 0)
contact = (33, 0)
metal1 = (34, 0)
dualgate = (55, 0)
v5_xtor = (112, 1)
lvpwell = (204, 0)

gf180mcu_fd_sc_mcu9t5v0_ = lib.new_cell('gf180mcu_fd_sc_mcu9t5v0__mux4_4')
R(gf180mcu_fd_sc_mcu9t5v0_, boundary, [(0,0,21.28,5.04)])
R(gf180mcu_fd_sc_mcu9t5v0_, nwell, [(-0.43,2.265,21.71,5.47)])
R(gf180mcu_fd_sc_mcu9t5v0_, comp, [(10.805,0.78,13.42,1.58), (14.02,0.78,21.1,1.58), (0.245,0.795,10.245,1.595), (11.36,2.98,13.76,4.26), (14.16,2.98,21,4.26)])
P(gf180mcu_fd_sc_mcu9t5v0_, comp, [(0.345,2.98),(0.345,4.26),(5.29,4.26),(5.29,4.42),(5.65,4.42),(5.65,4.26),(7.77,4.26),(7.77,4.42),(8.13,4.42),(8.13,4.26),(10.39,4.26),(10.39,2.98)])
R(gf180mcu_fd_sc_mcu9t5v0_, poly2, [(2.145,2.36,2.645,4.48)])
P(gf180mcu_fd_sc_mcu9t5v0_, poly2, [(0.685,0.575),(0.685,1.815),(0.785,1.815),(0.785,4.48),(1.285,4.48),(1.285,0.575)],
  [(4.725,0.575),(4.725,2.36),(4.49,2.36),(4.49,4.48),(4.99,4.48),(4.99,1.815),(5.325,1.815),(5.325,0.575)],
  [(5.845,0.575),(5.845,1.815),(5.95,1.815),(5.95,4.48),(6.45,4.48),(6.45,2.555),(6.97,2.555),(6.97,4.48),(7.47,4.48),(7.47,2.68),(8.43,2.68),(8.43,4.48),(8.93,4.48),(8.93,2.555),(9.45,2.555),(9.45,4.48),(9.95,4.48),(9.95,2.36),(9.805,2.36),(9.805,0.575),(9.205,0.575),(9.205,2.355),(8.685,2.355),(8.685,0.575),(8.085,0.575),(8.085,2.355),(7.565,2.355),(7.565,0.575),(6.965,0.575),(6.965,2.355),(6.445,2.355),(6.445,0.575)],
  [(11.26,0.56),(11.26,2.24),(12.14,2.24),(12.14,1.88),(11.86,1.88),(11.86,0.56)],
  [(12.38,0.56),(12.38,2.48),(11.8,2.48),(11.8,4.48),(12.3,4.48),(12.3,2.68),(12.58,2.68),(12.58,2.24),(14.22,2.24),(14.22,1.88),(12.98,1.88),(12.98,0.56)],
  [(14.46,0.56),(14.46,2.48),(12.82,2.48),(12.82,4.48),(13.32,4.48),(13.32,2.68),(14.6,2.68),(14.6,4.48),(15.1,4.48),(15.1,2.76),(15.06,2.76),(15.06,0.56)],
  [(15.58,0.56),(15.58,1.8),(15.68,1.8),(15.68,4.48),(16.18,4.48),(16.18,0.56)],
  [(17.82,0.56),(17.82,2.3),(16.8,2.3),(16.8,4.72),(3.775,4.72),(3.775,2.47),(3.385,2.47),(3.385,2.355),(3.085,2.355),(3.085,0.575),(2.485,0.575),(2.485,1.815),(2.885,1.815),(2.885,2.64),(3.275,2.64),(3.275,4.92),(17.3,4.92),(17.3,2.5),(18.7,2.5),(18.7,2.14),(18.42,2.14),(18.42,0.56)],
  [(18.94,0.56),(18.94,4.48),(19.44,4.48),(19.44,2.04),(19.54,2.04),(19.54,0.56)],
  [(3.605,0.12),(3.605,1.895),(3.59,1.895),(3.59,2.23),(4.205,2.23),(4.205,0.32),(16.7,0.32),(16.7,1.8),(17.3,1.8),(17.3,0.32),(20.06,0.32),(20.06,4.72),(18.42,4.72),(18.42,2.76),(17.92,2.76),(17.92,4.92),(20.56,4.92),(20.56,1.8),(20.66,1.8),(20.66,0.12)])
R(gf180mcu_fd_sc_mcu9t5v0_, pplus, [(-0.2,2.265,21.48,5.24)])
R(gf180mcu_fd_sc_mcu9t5v0_, nplus, [(-0.2,-0.2,21.48,2.265)])
A(gf180mcu_fd_sc_mcu9t5v0_, contact, 3.235, 1.29, 0.22, 0.22, 7, 1, 1.12, 0)
A(gf180mcu_fd_sc_mcu9t5v0_, contact, 14.09, 1.29, 0.22, 0.22, 7, 1, 1.12, 0)
A(gf180mcu_fd_sc_mcu9t5v0_, contact, 4.12, 3.1, 0.22, 0.22, 3, 1, 2.48, 0)
A(gf180mcu_fd_sc_mcu9t5v0_, contact, 11.43, 3.1, 0.22, 0.22, 3, 2, 1.02, 0.47)
A(gf180mcu_fd_sc_mcu9t5v0_, contact, 16.33, 3.1, 0.22, 0.22, 3, 2, 1.12, 0.47)
R(gf180mcu_fd_sc_mcu9t5v0_, contact, [(0.315,1.29,0.535,1.51), (1.435,1.29,1.655,1.51), (10.875,1.29,11.095,1.51), (12.01,1.29,12.23,1.51), (13.13,1.29,13.35,1.51), (19.195,1.75,19.415,1.97), (3.66,1.94,3.88,2.16), (11.85,1.95,12.07,2.17), (13.93,1.95,14.15,2.17), (18.41,2.21,18.63,2.43), (0.855,2.43,1.075,2.65), (2.355,2.43,2.575,2.65), (4.635,2.43,4.855,2.65), (9.66,2.43,9.88,2.65), (15.835,2.43,16.055,2.65), (12.91,2.55,13.13,2.77), (0.415,3.1,0.635,3.32), (1.435,3.1,1.655,3.32), (2.795,3.1,3.015,3.32), (14.23,3.1,14.45,3.32), (19.59,3.1,19.81,3.32), (20.71,3.1,20.93,3.32), (15.25,3.46,15.47,3.68), (10.1,3.5,10.32,3.72), (0.415,3.57,0.635,3.79), (1.435,3.57,1.655,3.79), (2.795,3.57,3.015,3.79), (14.23,3.57,14.45,3.79), (19.59,3.57,19.81,3.79), (20.71,3.57,20.93,3.79), (15.25,3.93,15.47,4.15), (10.1,3.97,10.32,4.19), (5.36,4.13,5.58,4.35), (7.84,4.13,8.06,4.35)])
R(gf180mcu_fd_sc_mcu9t5v0_, metal1, [(19.19,1.21,19.45,2.03), (1.43,1.23,1.66,3.85), (13.925,1.23,14.455,3.85), (16.325,1.23,16.555,3.85), (4.63,2.15,4.89,2.71), (15.83,2.15,16.09,2.71), (0.7,2.33,1.08,2.71)])
P(gf180mcu_fd_sc_mcu9t5v0_, metal1, [(2.35,1.77),(2.35,2.71),(2.58,2.71),(2.58,2.22),(3.885,2.22),(3.885,1.77)],
  [(4.35,1.23),(4.35,1.695),(4.115,1.695),(4.115,3.38),(4.345,3.38),(4.345,1.925),(4.58,1.925),(4.58,1.23)],
  [(8.83,1.21),(8.83,1.8),(6.82,1.8),(6.82,1.23),(6.59,1.23),(6.59,3.38),(6.825,3.38),(6.825,2.03),(9.075,2.03),(9.075,3.38),(9.37,3.38),(9.37,1.21)],
  [(10.87,1.23),(10.87,2.98),(9.635,2.98),(9.635,3.61),(3.02,3.61),(3.02,3.04),(2.79,3.04),(2.79,3.61),(2.12,3.61),(2.12,1.515),(3.515,1.515),(3.515,1.285),(1.89,1.285),(1.89,3.85),(3.02,3.85),(3.02,3.84),(9.865,3.84),(9.865,3.21),(10.945,3.21),(10.945,3.27),(11.425,3.27),(11.425,3.85),(11.655,3.85),(11.655,3.04),(11.1,3.04),(11.1,1.23)],
  [(10.41,0.77),(10.41,1.8),(9.655,1.8),(9.655,2.71),(9.885,2.71),(9.885,2.03),(10.64,2.03),(10.64,1),(11.33,1),(11.33,2.635),(12.445,2.635),(12.445,3.85),(12.675,3.85),(12.675,2.405),(11.56,2.405),(11.56,1),(12.005,1),(12.005,1.57),(12.235,1.57),(12.235,0.77)],
  [(12.47,1.21),(12.47,1.945),(11.79,1.945),(11.79,2.175),(12.905,2.175),(12.905,2.83),(13.135,2.83),(13.135,1.945),(12.73,1.945),(12.73,1.21)],
  [(13.125,1.23),(13.125,1.57),(13.465,1.57),(13.465,4.31),(15.015,4.31),(15.015,3.17),(15.705,3.17),(15.705,4.31),(17.675,4.31),(17.675,1.23),(17.445,1.23),(17.445,4.08),(15.935,4.08),(15.935,2.94),(14.785,2.94),(14.785,4.08),(13.695,4.08),(13.695,1.23)],
  [(17.945,1.285),(17.945,2.95),(18.565,2.95),(18.565,3.85),(18.795,3.85),(18.795,2.72),(18.175,2.72),(18.175,1.515),(18.85,1.515),(18.85,1.285)],
  [(20.805,1.23),(20.805,2.26),(18.635,2.26),(18.635,2.15),(18.405,2.15),(18.405,2.49),(20.705,2.49),(20.705,3.85),(21.035,3.85),(21.035,1.23)],
  [(0,-0.45),(0,0.45),(0.31,0.45),(0.31,1.57),(0.54,1.57),(0.54,0.45),(5.47,0.45),(5.47,1.57),(5.7,1.57),(5.7,0.45),(7.71,0.45),(7.71,1.57),(7.94,1.57),(7.94,0.45),(9.95,0.45),(9.95,1.57),(10.18,1.57),(10.18,0.45),(15.205,0.45),(15.205,1.57),(15.435,1.57),(15.435,0.45),(19.685,0.45),(19.685,1.57),(19.915,1.57),(19.915,0.45),(21.28,0.45),(21.28,-0.45)],
  [(0.41,3.04),(0.41,4.59),(0,4.59),(0,5.49),(21.28,5.49),(21.28,4.59),(19.815,4.59),(19.815,3.04),(19.585,3.04),(19.585,4.59),(15.475,4.59),(15.475,3.4),(15.245,3.4),(15.245,4.59),(10.325,4.59),(10.325,3.44),(10.095,3.44),(10.095,4.59),(8.065,4.59),(8.065,4.07),(7.835,4.07),(7.835,4.59),(5.585,4.59),(5.585,4.07),(5.355,4.07),(5.355,4.59),(0.64,4.59),(0.64,3.04)])
R(gf180mcu_fd_sc_mcu9t5v0_, dualgate, [(-0.28,-0.28,21.56,5.32)])
R(gf180mcu_fd_sc_mcu9t5v0_, v5_xtor, [(0,0,21.28,5.04)])
R(gf180mcu_fd_sc_mcu9t5v0_, lvpwell, [(-0.43,-0.43,21.71,2.265)])
gf180mcu_fd_sc_mcu9t5v0_.add(gdstk.Label('I0', (19.32,1.4), layer=34, texttype=10))
gf180mcu_fd_sc_mcu9t5v0_.add(gdstk.Label('I1', (15.96,2.52), layer=34, texttype=10))
gf180mcu_fd_sc_mcu9t5v0_.add(gdstk.Label('I2', (0.84,2.52), layer=34, texttype=10))
gf180mcu_fd_sc_mcu9t5v0_.add(gdstk.Label('I3', (4.76,2.52), layer=34, texttype=10))
gf180mcu_fd_sc_mcu9t5v0_.add(gdstk.Label('S0', (3.08,1.96), layer=34, texttype=10))
gf180mcu_fd_sc_mcu9t5v0_.add(gdstk.Label('S1', (12.6,1.96), layer=34, texttype=10))
gf180mcu_fd_sc_mcu9t5v0_.add(gdstk.Label('VDD', (0.525,4.59), layer=34, texttype=10))
gf180mcu_fd_sc_mcu9t5v0_.add(gdstk.Label('VSS', (19.8,0.45), layer=34, texttype=10))
gf180mcu_fd_sc_mcu9t5v0_.add(gdstk.Label('Z', (9.24,1.96), layer=34, texttype=10))
gf180mcu_fd_sc_mcu9t5v0_.add(gdstk.Label('& Vendor GLOBALFOUNDRIES', (0,2), layer=63, texttype=63))
gf180mcu_fd_sc_mcu9t5v0_.add(gdstk.Label('& Product GF018hv5v_green_sc9', (0,1.5), layer=63, texttype=63))
gf180mcu_fd_sc_mcu9t5v0_.add(gdstk.Label('& Version 2015q2v2', (0,1), layer=63, texttype=63))
gf180mcu_fd_sc_mcu9t5v0_.add(gdstk.Label('& Metric 1.00', (0,0.5), layer=63, texttype=63))
gf180mcu_fd_sc_mcu9t5v0_.add(gdstk.Label('VNW', (0.345,3.92), layer=21, texttype=10))
gf180mcu_fd_sc_mcu9t5v0_.add(gdstk.Label('VPW', (0.34,-0.085), layer=204, texttype=10))

lib.write_gds('gf180mcu_fd_sc_mcu9t5v0__mux4_4.gds')
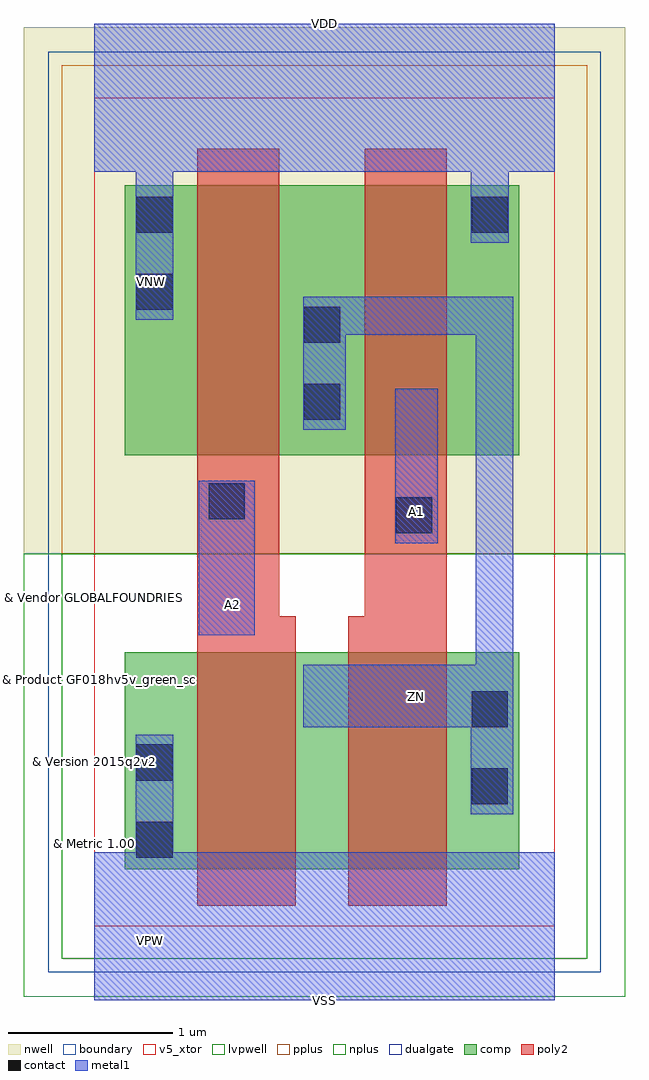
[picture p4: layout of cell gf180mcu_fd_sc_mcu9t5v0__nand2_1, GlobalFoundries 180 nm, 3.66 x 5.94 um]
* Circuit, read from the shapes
.subckt gf180mcu_fd_sc_mcu9t5v0__nand2_1 A1 A2 VDD VNW VSS ZN
XM1 n1 A2 VSS VSUBS nfet_05v0 w=1.32u l=0.6u
XM2 ZN A1 n1 VSUBS nfet_05v0 w=1.32u l=0.6u
XM3 ZN A2 VDD VNW pfet_05v0 w=1.645u l=0.5u
XM4 VDD A1 ZN VNW pfet_05v0 w=1.645u l=0.5u
.ends

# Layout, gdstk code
import gdstk
lib = gdstk.Library(unit=1e-6, precision=1e-09)
def R(c, l, rs):  # rectangles x0, y0, x1, y1
    for r in rs: c.add(gdstk.rectangle(r[:2], r[2:], *l))
def P(c, l, *ps):  # polygons
    for p in ps: c.add(gdstk.Polygon(p, *l))
boundary = (0, 0)
nwell = (21, 0)
comp = (22, 0)
poly2 = (30, 0)
pplus = (31, 0)
nplus = (32, 0)
contact = (33, 0)
metal1 = (34, 0)
dualgate = (55, 0)
v5_xtor = (112, 1)
lvpwell = (204, 0)

gf180mcu_fd_sc_mcu9t5v0_ = lib.new_cell('gf180mcu_fd_sc_mcu9t5v0__nand2_1')
R(gf180mcu_fd_sc_mcu9t5v0_, boundary, [(0,0,2.8,5.04)])
R(gf180mcu_fd_sc_mcu9t5v0_, nwell, [(-0.43,2.265,3.23,5.47)])
R(gf180mcu_fd_sc_mcu9t5v0_, comp, [(0.185,0.345,2.585,1.665), (0.185,2.865,2.585,4.51)])
P(gf180mcu_fd_sc_mcu9t5v0_, poly2, [(0.625,0.125),(0.625,4.73),(1.125,4.73),(1.125,1.885),(1.225,1.885),(1.225,0.125)],
  [(1.545,0.125),(1.545,1.885),(1.645,1.885),(1.645,4.73),(2.145,4.73),(2.145,0.125)])
R(gf180mcu_fd_sc_mcu9t5v0_, pplus, [(-0.2,2.265,3,5.24)])
R(gf180mcu_fd_sc_mcu9t5v0_, nplus, [(-0.2,-0.2,3,2.265)])
R(gf180mcu_fd_sc_mcu9t5v0_, contact, [(0.255,0.415,0.475,0.635), (2.295,0.74,2.515,0.96), (0.255,0.885,0.475,1.105), (2.295,1.21,2.515,1.43), (1.835,2.39,2.055,2.61), (0.695,2.475,0.915,2.695), (1.275,3.08,1.495,3.3), (1.275,3.55,1.495,3.77), (0.255,3.75,0.475,3.97), (0.255,4.22,0.475,4.44), (2.295,4.22,2.515,4.44)])
R(gf180mcu_fd_sc_mcu9t5v0_, metal1, [(0.635,1.77,0.975,2.71), (1.83,2.33,2.09,3.27)])
P(gf180mcu_fd_sc_mcu9t5v0_, metal1, [(2.29,0.68),(2.29,1.21),(1.27,1.21),(1.27,1.59),(2.32,1.59),(2.32,3.6),(1.53,3.6),(1.53,3.02),(1.27,3.02),(1.27,3.83),(2.55,3.83),(2.55,0.68)],
  [(0,-0.45),(0,0.45),(0.25,0.45),(0.25,1.165),(0.48,1.165),(0.48,0.45),(2.8,0.45),(2.8,-0.45)],
  [(0.25,3.69),(0.25,4.59),(0,4.59),(0,5.49),(2.8,5.49),(2.8,4.59),(2.52,4.59),(2.52,4.16),(2.29,4.16),(2.29,4.59),(0.48,4.59),(0.48,3.69)])
R(gf180mcu_fd_sc_mcu9t5v0_, dualgate, [(-0.28,-0.28,3.08,5.32)])
R(gf180mcu_fd_sc_mcu9t5v0_, v5_xtor, [(0,0,2.8,5.04)])
R(gf180mcu_fd_sc_mcu9t5v0_, lvpwell, [(-0.43,-0.43,3.23,2.265)])
gf180mcu_fd_sc_mcu9t5v0_.add(gdstk.Label('A1', (1.96,2.52), layer=34, texttype=10))
gf180mcu_fd_sc_mcu9t5v0_.add(gdstk.Label('A2', (0.84,1.96), layer=34, texttype=10))
gf180mcu_fd_sc_mcu9t5v0_.add(gdstk.Label('VDD', (1.4,5.49), layer=34, texttype=10))
gf180mcu_fd_sc_mcu9t5v0_.add(gdstk.Label('VSS', (1.4,-0.45), layer=34, texttype=10))
gf180mcu_fd_sc_mcu9t5v0_.add(gdstk.Label('ZN', (1.96,1.4), layer=34, texttype=10))
gf180mcu_fd_sc_mcu9t5v0_.add(gdstk.Label('& Vendor GLOBALFOUNDRIES', (0,2), layer=63, texttype=63))
gf180mcu_fd_sc_mcu9t5v0_.add(gdstk.Label('& Product GF018hv5v_green_sc9', (0,1.5), layer=63, texttype=63))
gf180mcu_fd_sc_mcu9t5v0_.add(gdstk.Label('& Version 2015q2v2', (0,1), layer=63, texttype=63))
gf180mcu_fd_sc_mcu9t5v0_.add(gdstk.Label('& Metric 1.00', (0,0.5), layer=63, texttype=63))
gf180mcu_fd_sc_mcu9t5v0_.add(gdstk.Label('VNW', (0.345,3.92), layer=21, texttype=10))
gf180mcu_fd_sc_mcu9t5v0_.add(gdstk.Label('VPW', (0.34,-0.085), layer=204, texttype=10))

lib.write_gds('gf180mcu_fd_sc_mcu9t5v0__nand2_1.gds')
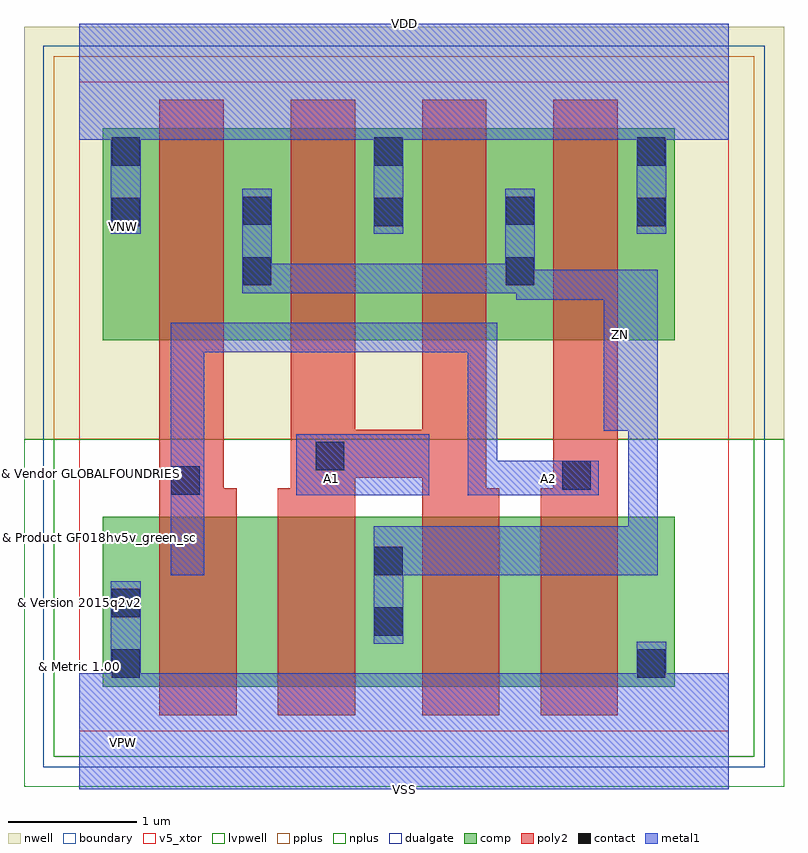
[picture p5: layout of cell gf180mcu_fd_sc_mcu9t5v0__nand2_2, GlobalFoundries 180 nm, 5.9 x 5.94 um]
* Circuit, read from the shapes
.subckt gf180mcu_fd_sc_mcu9t5v0__nand2_2 A1 A2 VDD VNW VSS ZN
XM1 n1 A2 VSS VSUBS nfet_05v0 w=1.32u l=0.6u
XM2 ZN A1 n1 VSUBS nfet_05v0 w=1.32u l=0.6u
XM3 n2 A1 ZN VSUBS nfet_05v0 w=1.32u l=0.6u
XM4 VSS A2 n2 VSUBS nfet_05v0 w=1.32u l=0.6u
XM5 ZN A2 VDD VNW pfet_05v0 w=1.645u l=0.5u m=2
XM6 VDD A1 ZN VNW pfet_05v0 w=1.645u l=0.5u m=2
.ends

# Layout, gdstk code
import gdstk
lib = gdstk.Library(unit=1e-6, precision=1e-09)
def R(c, l, rs):  # rectangles x0, y0, x1, y1
    for r in rs: c.add(gdstk.rectangle(r[:2], r[2:], *l))
def A(c, l, x, y, w, h, nx, ny, dx, dy):  # array of equal rectangles
    R(c, l, [(x+i*dx, y+j*dy, x+i*dx+w, y+j*dy+h) for i in range(nx) for j in range(ny)])
def P(c, l, *ps):  # polygons
    for p in ps: c.add(gdstk.Polygon(p, *l))
boundary = (0, 0)
nwell = (21, 0)
comp = (22, 0)
poly2 = (30, 0)
pplus = (31, 0)
nplus = (32, 0)
contact = (33, 0)
metal1 = (34, 0)
dualgate = (55, 0)
v5_xtor = (112, 1)
lvpwell = (204, 0)

gf180mcu_fd_sc_mcu9t5v0_ = lib.new_cell('gf180mcu_fd_sc_mcu9t5v0__nand2_2')
R(gf180mcu_fd_sc_mcu9t5v0_, boundary, [(0,0,5.04,5.04)])
R(gf180mcu_fd_sc_mcu9t5v0_, nwell, [(-0.43,2.265,5.47,5.47)])
R(gf180mcu_fd_sc_mcu9t5v0_, comp, [(0.18,0.345,4.62,1.665), (0.18,3.035,4.62,4.68)])
P(gf180mcu_fd_sc_mcu9t5v0_, poly2, [(0.62,0.125),(0.62,4.9),(1.12,4.9),(1.12,1.885),(1.22,1.885),(1.22,0.125)],
  [(1.54,0.125),(1.54,1.885),(1.64,1.885),(1.64,4.9),(2.14,4.9),(2.14,2.34),(2.66,2.34),(2.66,4.9),(3.16,4.9),(3.16,1.885),(3.26,1.885),(3.26,0.125),(2.66,0.125),(2.66,1.965),(2.14,1.965),(2.14,0.125)],
  [(3.58,0.125),(3.58,1.885),(3.68,1.885),(3.68,4.9),(4.18,4.9),(4.18,0.125)])
R(gf180mcu_fd_sc_mcu9t5v0_, pplus, [(-0.2,2.265,5.24,5.24)])
R(gf180mcu_fd_sc_mcu9t5v0_, nplus, [(-0.2,-0.2,5.24,2.265)])
A(gf180mcu_fd_sc_mcu9t5v0_, contact, 0.25, 3.92, 0.22, 0.22, 3, 2, 2.04, 0.47)
R(gf180mcu_fd_sc_mcu9t5v0_, contact, [(0.25,0.415,0.47,0.635), (4.33,0.415,4.55,0.635), (2.29,0.74,2.51,0.96), (0.25,0.885,0.47,1.105), (2.29,1.21,2.51,1.43), (0.715,1.835,0.935,2.055), (3.75,1.875,3.97,2.095), (1.835,2.025,2.055,2.245), (1.27,3.46,1.49,3.68), (3.31,3.46,3.53,3.68), (1.27,3.93,1.49,4.15), (3.31,3.93,3.53,4.15)])
R(gf180mcu_fd_sc_mcu9t5v0_, metal1, [(1.685,1.83,2.715,2.305)])
P(gf180mcu_fd_sc_mcu9t5v0_, metal1, [(0.71,1.21),(0.71,3.17),(3.245,3.17),(3.245,2.1),(4.03,2.1),(4.03,1.83),(3.015,1.83),(3.015,2.94),(0.97,2.94),(0.97,1.21)],
  [(2.285,0.68),(2.285,1.59),(4.26,1.59),(4.26,2.33),(4.07,2.33),(4.07,3.35),(3.39,3.35),(3.39,3.4),(1.265,3.4),(1.265,4.21),(1.495,4.21),(1.495,3.63),(3.305,3.63),(3.305,4.21),(3.535,4.21),(3.535,3.58),(4.49,3.58),(4.49,1.21),(2.515,1.21),(2.515,0.68)],
  [(0,-0.45),(0,0.45),(0.245,0.45),(0.245,1.165),(0.475,1.165),(0.475,0.45),(4.325,0.45),(4.325,0.695),(4.555,0.695),(4.555,0.45),(5.04,0.45),(5.04,-0.45)],
  [(0.245,3.86),(0.245,4.59),(0,4.59),(0,5.49),(5.04,5.49),(5.04,4.59),(4.555,4.59),(4.555,3.86),(4.325,3.86),(4.325,4.59),(2.515,4.59),(2.515,3.86),(2.285,3.86),(2.285,4.59),(0.475,4.59),(0.475,3.86)])
R(gf180mcu_fd_sc_mcu9t5v0_, dualgate, [(-0.28,-0.28,5.32,5.32)])
R(gf180mcu_fd_sc_mcu9t5v0_, v5_xtor, [(0,0,5.04,5.04)])
R(gf180mcu_fd_sc_mcu9t5v0_, lvpwell, [(-0.43,-0.43,5.47,2.265)])
gf180mcu_fd_sc_mcu9t5v0_.add(gdstk.Label('A1', (1.96,1.96), layer=34, texttype=10))
gf180mcu_fd_sc_mcu9t5v0_.add(gdstk.Label('A2', (3.64,1.96), layer=34, texttype=10))
gf180mcu_fd_sc_mcu9t5v0_.add(gdstk.Label('VDD', (2.52,5.49), layer=34, texttype=10))
gf180mcu_fd_sc_mcu9t5v0_.add(gdstk.Label('VSS', (2.52,-0.45), layer=34, texttype=10))
gf180mcu_fd_sc_mcu9t5v0_.add(gdstk.Label('ZN', (4.2,3.08), layer=34, texttype=10))
gf180mcu_fd_sc_mcu9t5v0_.add(gdstk.Label('& Vendor GLOBALFOUNDRIES', (0,2), layer=63, texttype=63))
gf180mcu_fd_sc_mcu9t5v0_.add(gdstk.Label('& Product GF018hv5v_green_sc9', (0,1.5), layer=63, texttype=63))
gf180mcu_fd_sc_mcu9t5v0_.add(gdstk.Label('& Version 2015q2v2', (0,1), layer=63, texttype=63))
gf180mcu_fd_sc_mcu9t5v0_.add(gdstk.Label('& Metric 1.00', (0,0.5), layer=63, texttype=63))
gf180mcu_fd_sc_mcu9t5v0_.add(gdstk.Label('VNW', (0.345,3.92), layer=21, texttype=10))
gf180mcu_fd_sc_mcu9t5v0_.add(gdstk.Label('VPW', (0.34,-0.085), layer=204, texttype=10))

lib.write_gds('gf180mcu_fd_sc_mcu9t5v0__nand2_2.gds')
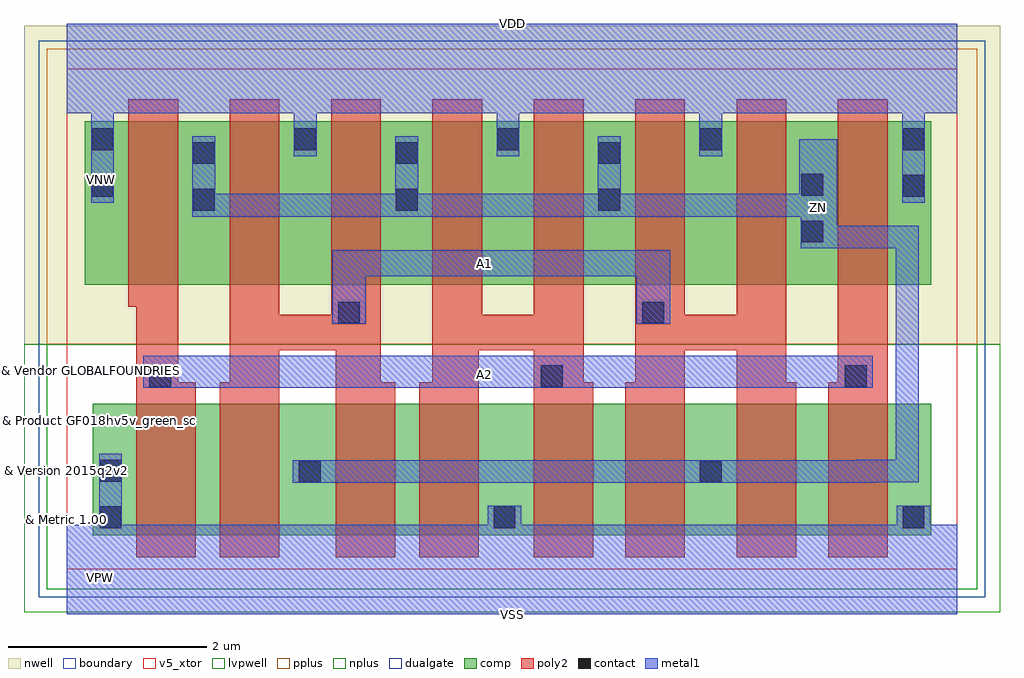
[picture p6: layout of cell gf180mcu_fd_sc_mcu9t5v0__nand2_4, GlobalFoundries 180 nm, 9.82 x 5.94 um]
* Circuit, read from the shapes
.subckt gf180mcu_fd_sc_mcu9t5v0__nand2_4 A1 A2 VDD VNW VSS ZN
XM1 n1 A2 VSS VSUBS nfet_05v0 w=1.32u l=0.6u
XM2 ZN A1 n1 VSUBS nfet_05v0 w=1.32u l=0.6u
XM3 n2 A1 ZN VSUBS nfet_05v0 w=1.32u l=0.6u
XM4 VSS A2 n2 VSUBS nfet_05v0 w=1.32u l=0.6u
XM5 n3 A2 VSS VSUBS nfet_05v0 w=1.32u l=0.6u
XM6 ZN A1 n3 VSUBS nfet_05v0 w=1.32u l=0.6u
XM7 n4 A1 ZN VSUBS nfet_05v0 w=1.32u l=0.6u
XM8 VSS A2 n4 VSUBS nfet_05v0 w=1.32u l=0.6u
XM9 ZN A2 VDD VNW pfet_05v0 w=1.645u l=0.5u m=4
XM10 VDD A1 ZN VNW pfet_05v0 w=1.645u l=0.5u m=4
.ends

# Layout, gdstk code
import gdstk
lib = gdstk.Library(unit=1e-6, precision=1e-09)
def R(c, l, rs):  # rectangles x0, y0, x1, y1
    for r in rs: c.add(gdstk.rectangle(r[:2], r[2:], *l))
def A(c, l, x, y, w, h, nx, ny, dx, dy):  # array of equal rectangles
    R(c, l, [(x+i*dx, y+j*dy, x+i*dx+w, y+j*dy+h) for i in range(nx) for j in range(ny)])
def P(c, l, *ps):  # polygons
    for p in ps: c.add(gdstk.Polygon(p, *l))
boundary = (0, 0)
nwell = (21, 0)
comp = (22, 0)
poly2 = (30, 0)
pplus = (31, 0)
nplus = (32, 0)
contact = (33, 0)
metal1 = (34, 0)
dualgate = (55, 0)
v5_xtor = (112, 1)
lvpwell = (204, 0)

gf180mcu_fd_sc_mcu9t5v0_ = lib.new_cell('gf180mcu_fd_sc_mcu9t5v0__nand2_4')
R(gf180mcu_fd_sc_mcu9t5v0_, boundary, [(0,0,8.96,5.04)])
R(gf180mcu_fd_sc_mcu9t5v0_, nwell, [(-0.43,2.265,9.39,5.47)])
R(gf180mcu_fd_sc_mcu9t5v0_, comp, [(0.26,0.345,8.7,1.665), (0.18,2.865,8.7,4.51)])
P(gf180mcu_fd_sc_mcu9t5v0_, poly2, [(0.7,0.125),(0.7,2.645),(0.62,2.645),(0.62,4.73),(1.12,4.73),(1.12,1.885),(1.3,1.885),(1.3,0.125)],
  [(1.54,0.125),(1.54,1.885),(1.64,1.885),(1.64,4.73),(2.14,4.73),(2.14,2.565),(2.66,2.565),(2.66,4.73),(3.16,4.73),(3.16,1.885),(3.305,1.885),(3.305,0.125),(2.705,0.125),(2.705,2.205),(2.14,2.205),(2.14,0.125)],
  [(3.545,0.125),(3.545,1.885),(3.68,1.885),(3.68,4.73),(4.18,4.73),(4.18,2.565),(4.7,2.565),(4.7,4.73),(5.2,4.73),(5.2,1.885),(5.3,1.885),(5.3,0.125),(4.7,0.125),(4.7,2.205),(4.145,2.205),(4.145,0.125)],
  [(5.62,0.125),(5.62,1.885),(5.72,1.885),(5.72,4.73),(6.22,4.73),(6.22,2.565),(6.74,2.565),(6.74,4.73),(7.24,4.73),(7.24,1.885),(7.34,1.885),(7.34,0.125),(6.74,0.125),(6.74,2.205),(6.22,2.205),(6.22,0.125)],
  [(7.66,0.125),(7.66,1.885),(7.76,1.885),(7.76,4.73),(8.26,4.73),(8.26,0.125)])
R(gf180mcu_fd_sc_mcu9t5v0_, pplus, [(-0.2,2.265,9.16,5.24)])
R(gf180mcu_fd_sc_mcu9t5v0_, nplus, [(-0.2,-0.2,9.16,2.265)])
A(gf180mcu_fd_sc_mcu9t5v0_, contact, 1.27, 3.61, 0.22, 0.22, 3, 2, 2.04, 0.47)
A(gf180mcu_fd_sc_mcu9t5v0_, contact, 0.25, 4.22, 0.22, 0.22, 5, 1, 2.04, 0)
R(gf180mcu_fd_sc_mcu9t5v0_, contact, [(0.33,0.415,0.55,0.635), (4.295,0.415,4.515,0.635), (8.41,0.415,8.63,0.635), (2.335,0.875,2.555,1.095), (6.37,0.875,6.59,1.095), (0.33,0.885,0.55,1.105), (0.83,1.835,1.05,2.055), (4.77,1.835,4.99,2.055), (7.83,1.835,8.05,2.055), (2.73,2.475,2.95,2.695), (5.79,2.475,6.01,2.695), (7.39,3.29,7.61,3.51), (0.25,3.75,0.47,3.97), (8.41,3.75,8.63,3.97), (7.39,3.76,7.61,3.98)])
R(gf180mcu_fd_sc_mcu9t5v0_, metal1, [(0.77,1.83,8.11,2.15)])
P(gf180mcu_fd_sc_mcu9t5v0_, metal1, [(2.67,2.47),(2.67,3.21),(6.07,3.21),(6.07,2.47),(5.73,2.47),(5.73,2.95),(3.01,2.95),(3.01,2.47)],
  [(2.275,0.87),(2.275,1.1),(7.94,1.1),(7.94,1.105),(8.34,1.105),(8.34,3.23),(7.385,3.23),(7.385,3.55),(1.265,3.55),(1.265,4.36),(1.495,4.36),(1.495,3.78),(3.305,3.78),(3.305,4.36),(3.535,4.36),(3.535,3.78),(5.345,3.78),(5.345,4.36),(5.575,4.36),(5.575,3.78),(7.37,3.78),(7.37,4.33),(7.75,4.33),(7.75,3.46),(8.57,3.46),(8.57,0.875),(8.145,0.875),(8.145,0.87)],
  [(0,-0.45),(0,0.45),(0.325,0.45),(0.325,1.165),(0.555,1.165),(0.555,0.45),(4.235,0.45),(4.235,0.64),(4.575,0.64),(4.575,0.45),(8.35,0.45),(8.35,0.64),(8.69,0.64),(8.69,0.45),(8.96,0.45),(8.96,-0.45)],
  [(0.245,3.69),(0.245,4.59),(0,4.59),(0,5.49),(8.96,5.49),(8.96,4.59),(8.635,4.59),(8.635,3.69),(8.405,3.69),(8.405,4.59),(6.595,4.59),(6.595,4.16),(6.365,4.16),(6.365,4.59),(4.555,4.59),(4.555,4.16),(4.325,4.16),(4.325,4.59),(2.515,4.59),(2.515,4.16),(2.285,4.16),(2.285,4.59),(0.475,4.59),(0.475,3.69)])
R(gf180mcu_fd_sc_mcu9t5v0_, dualgate, [(-0.28,-0.28,9.24,5.32)])
R(gf180mcu_fd_sc_mcu9t5v0_, v5_xtor, [(0,0,8.96,5.04)])
R(gf180mcu_fd_sc_mcu9t5v0_, lvpwell, [(-0.43,-0.43,9.39,2.265)])
gf180mcu_fd_sc_mcu9t5v0_.add(gdstk.Label('A1', (4.2,3.08), layer=34, texttype=10))
gf180mcu_fd_sc_mcu9t5v0_.add(gdstk.Label('A2', (4.2,1.96), layer=34, texttype=10))
gf180mcu_fd_sc_mcu9t5v0_.add(gdstk.Label('VDD', (4.48,5.49), layer=34, texttype=10))
gf180mcu_fd_sc_mcu9t5v0_.add(gdstk.Label('VSS', (4.48,-0.45), layer=34, texttype=10))
gf180mcu_fd_sc_mcu9t5v0_.add(gdstk.Label('ZN', (7.56,3.64), layer=34, texttype=10))
gf180mcu_fd_sc_mcu9t5v0_.add(gdstk.Label('& Vendor GLOBALFOUNDRIES', (0,2), layer=63, texttype=63))
gf180mcu_fd_sc_mcu9t5v0_.add(gdstk.Label('& Product GF018hv5v_green_sc9', (0,1.5), layer=63, texttype=63))
gf180mcu_fd_sc_mcu9t5v0_.add(gdstk.Label('& Version 2015q2v2', (0,1), layer=63, texttype=63))
gf180mcu_fd_sc_mcu9t5v0_.add(gdstk.Label('& Metric 1.00', (0,0.5), layer=63, texttype=63))
gf180mcu_fd_sc_mcu9t5v0_.add(gdstk.Label('VNW', (0.345,3.92), layer=21, texttype=10))
gf180mcu_fd_sc_mcu9t5v0_.add(gdstk.Label('VPW', (0.34,-0.085), layer=204, texttype=10))

lib.write_gds('gf180mcu_fd_sc_mcu9t5v0__nand2_4.gds')
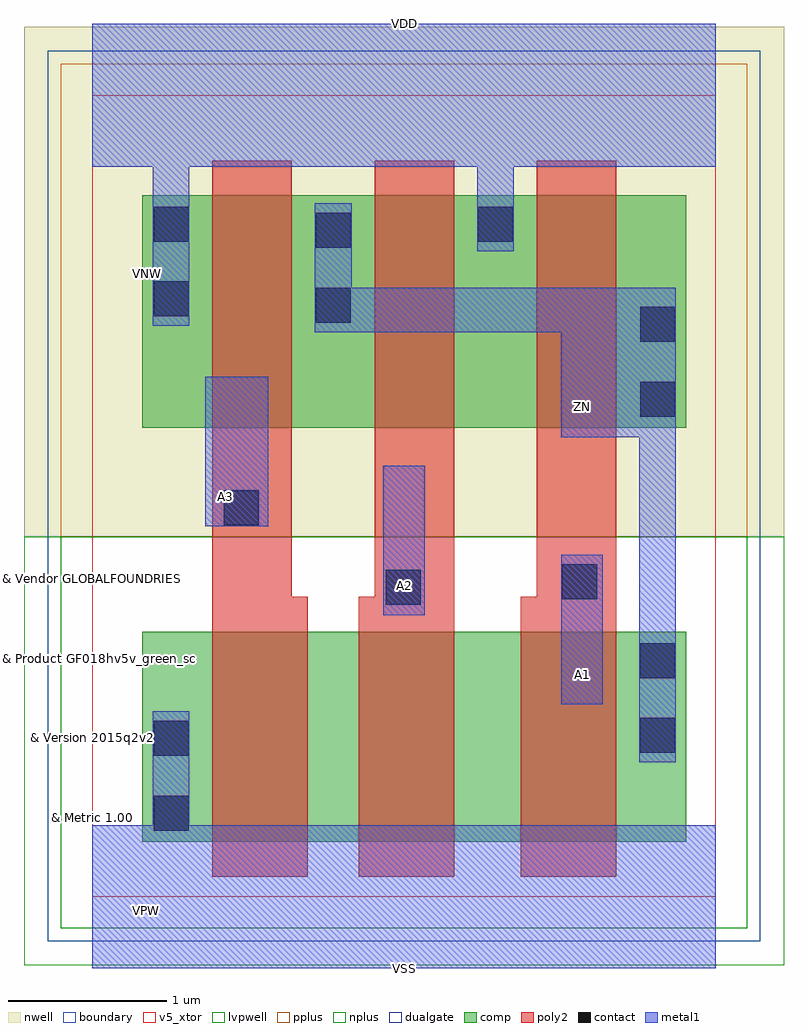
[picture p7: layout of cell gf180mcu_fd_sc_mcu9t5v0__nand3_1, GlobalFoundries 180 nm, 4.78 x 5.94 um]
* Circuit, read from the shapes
.subckt gf180mcu_fd_sc_mcu9t5v0__nand3_1 A1 A2 A3 VDD VNW VSS ZN
XM1 n1 A3 VSS VSUBS nfet_05v0 w=1.32u l=0.6u
XM2 n2 A2 n1 VSUBS nfet_05v0 w=1.32u l=0.6u
XM3 ZN A1 n2 VSUBS nfet_05v0 w=1.32u l=0.6u
XM4 ZN A3 VDD VNW pfet_05v0 w=1.46u l=0.5u
XM5 VDD A2 ZN VNW pfet_05v0 w=1.46u l=0.5u
XM6 ZN A1 VDD VNW pfet_05v0 w=1.46u l=0.5u
.ends

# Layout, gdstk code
import gdstk
lib = gdstk.Library(unit=1e-6, precision=1e-09)
def R(c, l, rs):  # rectangles x0, y0, x1, y1
    for r in rs: c.add(gdstk.rectangle(r[:2], r[2:], *l))
def P(c, l, *ps):  # polygons
    for p in ps: c.add(gdstk.Polygon(p, *l))
boundary = (0, 0)
nwell = (21, 0)
comp = (22, 0)
poly2 = (30, 0)
pplus = (31, 0)
nplus = (32, 0)
contact = (33, 0)
metal1 = (34, 0)
dualgate = (55, 0)
v5_xtor = (112, 1)
lvpwell = (204, 0)

gf180mcu_fd_sc_mcu9t5v0_ = lib.new_cell('gf180mcu_fd_sc_mcu9t5v0__nand3_1')
R(gf180mcu_fd_sc_mcu9t5v0_, boundary, [(0,0,3.92,5.04)])
R(gf180mcu_fd_sc_mcu9t5v0_, nwell, [(-0.43,2.265,4.35,5.47)])
R(gf180mcu_fd_sc_mcu9t5v0_, comp, [(0.315,0.345,3.735,1.665), (0.315,2.95,3.735,4.41)])
P(gf180mcu_fd_sc_mcu9t5v0_, poly2, [(0.755,0.125),(0.755,4.63),(1.255,4.63),(1.255,1.885),(1.355,1.885),(1.355,0.125)],
  [(1.675,0.125),(1.675,1.885),(1.775,1.885),(1.775,4.63),(2.275,4.63),(2.275,0.125)],
  [(2.695,0.125),(2.695,1.885),(2.795,1.885),(2.795,4.63),(3.295,4.63),(3.295,0.125)])
R(gf180mcu_fd_sc_mcu9t5v0_, pplus, [(-0.2,2.265,4.12,5.24)])
R(gf180mcu_fd_sc_mcu9t5v0_, nplus, [(-0.2,-0.2,4.12,2.265)])
R(gf180mcu_fd_sc_mcu9t5v0_, contact, [(0.385,0.415,0.605,0.635), (0.385,0.885,0.605,1.105), (3.445,0.905,3.665,1.125), (3.445,1.375,3.665,1.595), (1.845,1.835,2.065,2.055), (2.955,1.87,3.175,2.09), (0.825,2.335,1.045,2.555), (3.445,3.02,3.665,3.24), (3.445,3.49,3.665,3.71), (1.405,3.61,1.625,3.83), (0.385,3.65,0.605,3.87), (1.405,4.08,1.625,4.3), (0.385,4.12,0.605,4.34), (2.425,4.12,2.645,4.34)])
R(gf180mcu_fd_sc_mcu9t5v0_, metal1, [(2.95,1.21,3.21,2.15), (1.83,1.77,2.09,2.71), (0.71,2.33,1.105,3.27)])
P(gf180mcu_fd_sc_mcu9t5v0_, metal1, [(3.44,0.845),(3.44,2.89),(2.95,2.89),(2.95,3.55),(1.4,3.55),(1.4,4.36),(1.63,4.36),(1.63,3.83),(3.67,3.83),(3.67,0.845)],
  [(0,-0.45),(0,0.45),(0.38,0.45),(0.38,1.165),(0.61,1.165),(0.61,0.45),(3.92,0.45),(3.92,-0.45)],
  [(0.38,3.59),(0.38,4.59),(0,4.59),(0,5.49),(3.92,5.49),(3.92,4.59),(2.65,4.59),(2.65,4.06),(2.42,4.06),(2.42,4.59),(0.61,4.59),(0.61,3.59)])
R(gf180mcu_fd_sc_mcu9t5v0_, dualgate, [(-0.28,-0.28,4.2,5.32)])
R(gf180mcu_fd_sc_mcu9t5v0_, v5_xtor, [(0,0,3.92,5.04)])
R(gf180mcu_fd_sc_mcu9t5v0_, lvpwell, [(-0.43,-0.43,4.35,2.265)])
gf180mcu_fd_sc_mcu9t5v0_.add(gdstk.Label('A1', (3.08,1.4), layer=34, texttype=10))
gf180mcu_fd_sc_mcu9t5v0_.add(gdstk.Label('A2', (1.96,1.96), layer=34, texttype=10))
gf180mcu_fd_sc_mcu9t5v0_.add(gdstk.Label('A3', (0.84,2.52), layer=34, texttype=10))
gf180mcu_fd_sc_mcu9t5v0_.add(gdstk.Label('VDD', (1.96,5.49), layer=34, texttype=10))
gf180mcu_fd_sc_mcu9t5v0_.add(gdstk.Label('VSS', (1.96,-0.45), layer=34, texttype=10))
gf180mcu_fd_sc_mcu9t5v0_.add(gdstk.Label('ZN', (3.08,3.08), layer=34, texttype=10))
gf180mcu_fd_sc_mcu9t5v0_.add(gdstk.Label('& Vendor GLOBALFOUNDRIES', (0,2), layer=63, texttype=63))
gf180mcu_fd_sc_mcu9t5v0_.add(gdstk.Label('& Product GF018hv5v_green_sc9', (0,1.5), layer=63, texttype=63))
gf180mcu_fd_sc_mcu9t5v0_.add(gdstk.Label('& Version 2015q2v2', (0,1), layer=63, texttype=63))
gf180mcu_fd_sc_mcu9t5v0_.add(gdstk.Label('& Metric 1.00', (0,0.5), layer=63, texttype=63))
gf180mcu_fd_sc_mcu9t5v0_.add(gdstk.Label('VNW', (0.345,3.92), layer=21, texttype=10))
gf180mcu_fd_sc_mcu9t5v0_.add(gdstk.Label('VPW', (0.34,-0.085), layer=204, texttype=10))

lib.write_gds('gf180mcu_fd_sc_mcu9t5v0__nand3_1.gds')
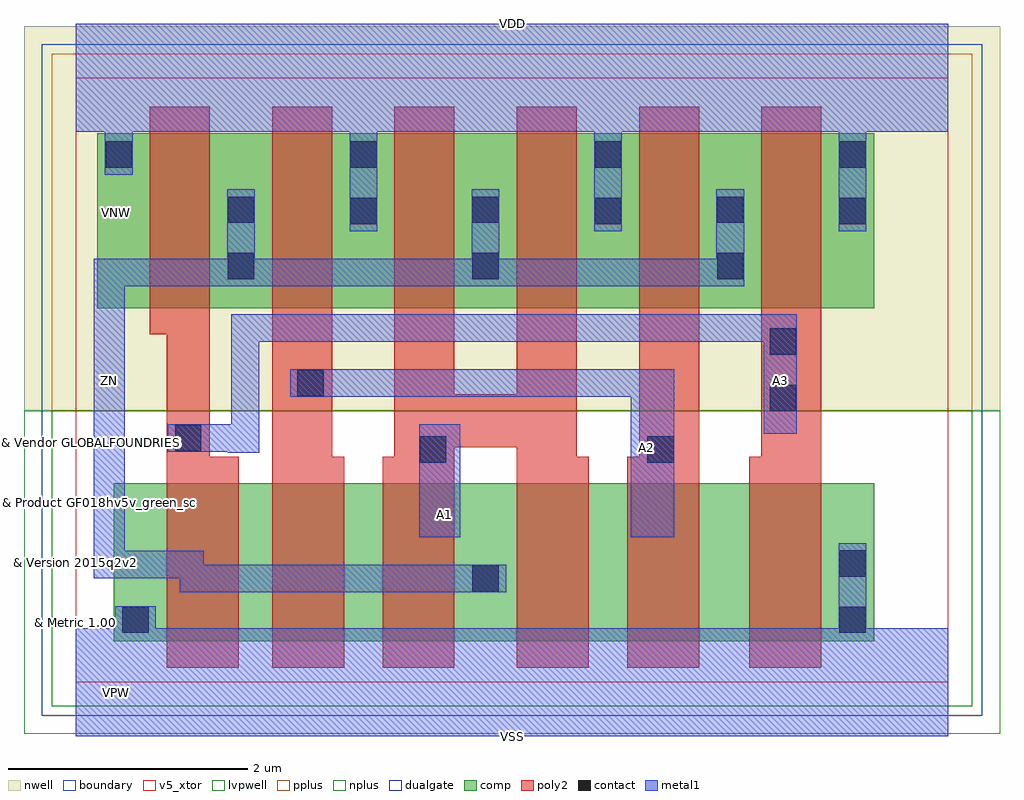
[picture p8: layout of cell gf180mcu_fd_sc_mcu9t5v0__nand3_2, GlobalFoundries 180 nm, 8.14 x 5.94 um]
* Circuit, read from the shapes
.subckt gf180mcu_fd_sc_mcu9t5v0__nand3_2 A1 A2 A3 VDD VNW VSS ZN
XM1 n1 A3 VSS VSUBS nfet_05v0 w=1.32u l=0.6u
XM2 n2 A2 n1 VSUBS nfet_05v0 w=1.32u l=0.6u
XM3 ZN A1 n2 VSUBS nfet_05v0 w=1.32u l=0.6u
XM4 n3 A1 ZN VSUBS nfet_05v0 w=1.32u l=0.6u
XM5 n4 A2 n3 VSUBS nfet_05v0 w=1.32u l=0.6u
XM6 VSS A3 n4 VSUBS nfet_05v0 w=1.32u l=0.6u
XM7 ZN A3 VDD VNW pfet_05v0 w=1.46u l=0.5u m=2
XM8 VDD A2 ZN VNW pfet_05v0 w=1.46u l=0.5u m=2
XM9 ZN A1 VDD VNW pfet_05v0 w=1.46u l=0.5u m=2
.ends

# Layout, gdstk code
import gdstk
lib = gdstk.Library(unit=1e-6, precision=1e-09)
def R(c, l, rs):  # rectangles x0, y0, x1, y1
    for r in rs: c.add(gdstk.rectangle(r[:2], r[2:], *l))
def A(c, l, x, y, w, h, nx, ny, dx, dy):  # array of equal rectangles
    R(c, l, [(x+i*dx, y+j*dy, x+i*dx+w, y+j*dy+h) for i in range(nx) for j in range(ny)])
def P(c, l, *ps):  # polygons
    for p in ps: c.add(gdstk.Polygon(p, *l))
boundary = (0, 0)
nwell = (21, 0)
comp = (22, 0)
poly2 = (30, 0)
pplus = (31, 0)
nplus = (32, 0)
contact = (33, 0)
metal1 = (34, 0)
dualgate = (55, 0)
v5_xtor = (112, 1)
lvpwell = (204, 0)

gf180mcu_fd_sc_mcu9t5v0_ = lib.new_cell('gf180mcu_fd_sc_mcu9t5v0__nand3_2')
R(gf180mcu_fd_sc_mcu9t5v0_, boundary, [(0,0,7.28,5.04)])
R(gf180mcu_fd_sc_mcu9t5v0_, nwell, [(-0.43,2.265,7.71,5.47)])
R(gf180mcu_fd_sc_mcu9t5v0_, comp, [(0.32,0.34,6.66,1.66), (0.18,3.12,6.66,4.58)])
P(gf180mcu_fd_sc_mcu9t5v0_, poly2, [(0.76,0.12),(0.76,2.9),(0.62,2.9),(0.62,4.8),(1.12,4.8),(1.12,1.88),(1.36,1.88),(1.36,0.12)],
  [(1.64,0.12),(1.64,4.8),(2.14,4.8),(2.14,1.88),(2.24,1.88),(2.24,0.12)],
  [(2.56,0.12),(2.56,1.88),(2.66,1.88),(2.66,4.8),(3.16,4.8),(3.16,2.4),(3.68,2.4),(3.68,4.8),(4.18,4.8),(4.18,1.88),(4.28,1.88),(4.28,0.12),(3.68,0.12),(3.68,1.96),(3.16,1.96),(3.16,0.12)],
  [(4.6,0.12),(4.6,1.88),(4.7,1.88),(4.7,4.8),(5.2,4.8),(5.2,0.12)],
  [(5.62,0.12),(5.62,1.88),(5.72,1.88),(5.72,4.8),(6.22,4.8),(6.22,0.12)])
R(gf180mcu_fd_sc_mcu9t5v0_, pplus, [(-0.2,2.265,7.48,5.24)])
R(gf180mcu_fd_sc_mcu9t5v0_, nplus, [(-0.2,-0.2,7.48,2.265)])
A(gf180mcu_fd_sc_mcu9t5v0_, contact, 1.27, 3.36, 0.22, 0.22, 3, 2, 2.04, 0.47)
A(gf180mcu_fd_sc_mcu9t5v0_, contact, 2.29, 3.82, 0.22, 0.22, 3, 1, 2.04, 0)
A(gf180mcu_fd_sc_mcu9t5v0_, contact, 0.25, 4.29, 0.22, 0.22, 4, 1, 2.04, 0)
R(gf180mcu_fd_sc_mcu9t5v0_, contact, [(0.39,0.41,0.61,0.63), (6.37,0.41,6.59,0.63), (3.31,0.755,3.53,0.975), (6.37,0.88,6.59,1.1), (2.87,1.83,3.09,2.05), (4.77,1.83,4.99,2.05), (0.83,1.925,1.05,2.145), (5.79,2.26,6.01,2.48), (1.85,2.385,2.07,2.605), (5.79,2.73,6.01,2.95)])
R(gf180mcu_fd_sc_mcu9t5v0_, metal1, [(2.865,1.21,3.21,2.15)])
P(gf180mcu_fd_sc_mcu9t5v0_, metal1, [(4.63,1.21),(4.63,2.38),(1.79,2.38),(1.79,2.61),(4.995,2.61),(4.995,1.21)],
  [(0.87,0.75),(0.87,0.865),(0.15,0.865),(0.15,3.53),(1.265,3.53),(1.265,4.11),(1.495,4.11),(1.495,3.53),(3.305,3.53),(3.305,4.11),(3.535,4.11),(3.535,3.53),(5.345,3.53),(5.345,4.11),(5.575,4.11),(5.575,3.3),(0.41,3.3),(0.41,1.095),(1.07,1.095),(1.07,0.98),(3.59,0.98),(3.59,0.75)],
  [(1.27,1.915),(1.27,1.92),(0.77,1.92),(0.77,2.15),(1.3,2.15),(1.3,3.07),(6.015,3.07),(6.015,2.07),(5.74,2.07),(5.74,2.84),(1.53,2.84),(1.53,1.915)],
  [(0,-0.45),(0,0.45),(0.33,0.45),(0.33,0.635),(0.67,0.635),(0.67,0.45),(6.365,0.45),(6.365,1.16),(6.595,1.16),(6.595,0.45),(7.28,0.45),(7.28,-0.45)],
  [(2.285,3.76),(2.285,4.59),(0.475,4.59),(0.475,4.23),(0.245,4.23),(0.245,4.59),(0,4.59),(0,5.49),(7.28,5.49),(7.28,4.59),(6.595,4.59),(6.595,3.76),(6.365,3.76),(6.365,4.59),(4.555,4.59),(4.555,3.76),(4.325,3.76),(4.325,4.59),(2.515,4.59),(2.515,3.76)])
R(gf180mcu_fd_sc_mcu9t5v0_, dualgate, [(-0.28,-0.28,7.56,5.32)])
R(gf180mcu_fd_sc_mcu9t5v0_, v5_xtor, [(0,0,7.28,5.04)])
R(gf180mcu_fd_sc_mcu9t5v0_, lvpwell, [(-0.43,-0.43,7.71,2.265)])
gf180mcu_fd_sc_mcu9t5v0_.add(gdstk.Label('A1', (3.08,1.4), layer=34, texttype=10))
gf180mcu_fd_sc_mcu9t5v0_.add(gdstk.Label('A2', (4.76,1.96), layer=34, texttype=10))
gf180mcu_fd_sc_mcu9t5v0_.add(gdstk.Label('A3', (5.88,2.52), layer=34, texttype=10))
gf180mcu_fd_sc_mcu9t5v0_.add(gdstk.Label('VDD', (3.64,5.49), layer=34, texttype=10))
gf180mcu_fd_sc_mcu9t5v0_.add(gdstk.Label('VSS', (3.64,-0.45), layer=34, texttype=10))
gf180mcu_fd_sc_mcu9t5v0_.add(gdstk.Label('ZN', (0.28,2.52), layer=34, texttype=10))
gf180mcu_fd_sc_mcu9t5v0_.add(gdstk.Label('& Vendor GLOBALFOUNDRIES', (0,2), layer=63, texttype=63))
gf180mcu_fd_sc_mcu9t5v0_.add(gdstk.Label('& Product GF018hv5v_green_sc9', (0,1.5), layer=63, texttype=63))
gf180mcu_fd_sc_mcu9t5v0_.add(gdstk.Label('& Version 2015q2v2', (0,1), layer=63, texttype=63))
gf180mcu_fd_sc_mcu9t5v0_.add(gdstk.Label('& Metric 1.00', (0,0.5), layer=63, texttype=63))
gf180mcu_fd_sc_mcu9t5v0_.add(gdstk.Label('VNW', (0.345,3.92), layer=21, texttype=10))
gf180mcu_fd_sc_mcu9t5v0_.add(gdstk.Label('VPW', (0.34,-0.085), layer=204, texttype=10))

lib.write_gds('gf180mcu_fd_sc_mcu9t5v0__nand3_2.gds')
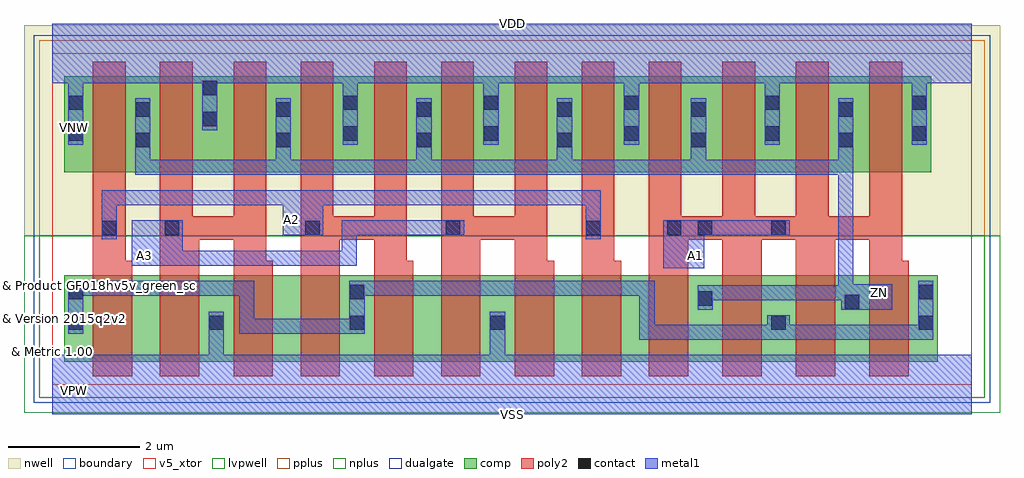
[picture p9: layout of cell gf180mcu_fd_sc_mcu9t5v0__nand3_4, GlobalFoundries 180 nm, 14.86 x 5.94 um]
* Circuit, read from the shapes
.subckt gf180mcu_fd_sc_mcu9t5v0__nand3_4 A1 A2 A3 VDD VNW VSS ZN
XM1 n1 A2 n2 VSUBS nfet_05v0 w=1.32u l=0.6u
XM2 VSS A3 n1 VSUBS nfet_05v0 w=1.32u l=0.6u
XM3 n3 A3 VSS VSUBS nfet_05v0 w=1.32u l=0.6u
XM4 n2 A2 n3 VSUBS nfet_05v0 w=1.32u l=0.6u
XM5 n4 A2 n2 VSUBS nfet_05v0 w=1.32u l=0.6u
XM6 VSS A3 n4 VSUBS nfet_05v0 w=1.32u l=0.6u
XM7 n5 A3 VSS VSUBS nfet_05v0 w=1.32u l=0.6u
XM8 n6 A2 n5 VSUBS nfet_05v0 w=1.32u l=0.6u
XM9 ZN A1 n6 VSUBS nfet_05v0 w=1.32u l=0.6u
XM10 n2 A1 ZN VSUBS nfet_05v0 w=1.32u l=0.6u m=3
XM11 ZN A2 VDD VNW pfet_05v0 w=1.46u l=0.5u m=4
XM12 VDD A3 ZN VNW pfet_05v0 w=1.46u l=0.5u m=4
XM13 ZN A1 VDD VNW pfet_05v0 w=1.46u l=0.5u m=4
.ends

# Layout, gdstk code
import gdstk
lib = gdstk.Library(unit=1e-6, precision=1e-09)
def R(c, l, rs):  # rectangles x0, y0, x1, y1
    for r in rs: c.add(gdstk.rectangle(r[:2], r[2:], *l))
def A(c, l, x, y, w, h, nx, ny, dx, dy):  # array of equal rectangles
    R(c, l, [(x+i*dx, y+j*dy, x+i*dx+w, y+j*dy+h) for i in range(nx) for j in range(ny)])
def P(c, l, *ps):  # polygons
    for p in ps: c.add(gdstk.Polygon(p, *l))
boundary = (0, 0)
nwell = (21, 0)
comp = (22, 0)
poly2 = (30, 0)
pplus = (31, 0)
nplus = (32, 0)
contact = (33, 0)
metal1 = (34, 0)
dualgate = (55, 0)
v5_xtor = (112, 1)
lvpwell = (204, 0)

gf180mcu_fd_sc_mcu9t5v0_ = lib.new_cell('gf180mcu_fd_sc_mcu9t5v0__nand3_4')
R(gf180mcu_fd_sc_mcu9t5v0_, boundary, [(0,0,14,5.04)])
R(gf180mcu_fd_sc_mcu9t5v0_, nwell, [(-0.43,2.265,14.43,5.47)])
R(gf180mcu_fd_sc_mcu9t5v0_, comp, [(0.18,0.345,13.48,1.665), (0.18,3.235,13.38,4.695)])
P(gf180mcu_fd_sc_mcu9t5v0_, poly2, [(0.62,0.125),(0.62,4.915),(1.12,4.915),(1.12,1.885),(1.22,1.885),(1.22,0.125)],
  [(1.64,0.125),(1.64,4.915),(2.14,4.915),(2.14,2.565),(2.76,2.565),(2.76,4.915),(3.26,4.915),(3.26,1.885),(3.36,1.885),(3.36,0.125),(2.76,0.125),(2.76,2.205),(2.24,2.205),(2.24,0.125)],
  [(3.78,0.125),(3.78,4.915),(4.28,4.915),(4.28,2.565),(4.9,2.565),(4.9,4.915),(5.4,4.915),(5.4,1.885),(5.5,1.885),(5.5,0.125),(4.9,0.125),(4.9,2.205),(4.38,2.205),(4.38,0.125)],
  [(5.92,0.125),(5.92,4.915),(6.42,4.915),(6.42,2.565),(7.04,2.565),(7.04,4.915),(7.54,4.915),(7.54,1.885),(7.64,1.885),(7.64,0.125),(7.04,0.125),(7.04,2.205),(6.52,2.205),(6.52,0.125)],
  [(8.06,0.125),(8.06,4.915),(8.56,4.915),(8.56,1.885),(8.66,1.885),(8.66,0.125)],
  [(9.08,0.125),(9.08,4.915),(9.58,4.915),(9.58,2.565),(10.2,2.565),(10.2,4.915),(10.7,4.915),(10.7,2.565),(11.32,2.565),(11.32,4.915),(11.82,4.915),(11.82,2.565),(12.44,2.565),(12.44,4.915),(12.94,4.915),(12.94,1.885),(13.04,1.885),(13.04,0.125),(12.44,0.125),(12.44,2.205),(11.92,2.205),(11.92,0.125),(11.32,0.125),(11.32,2.205),(10.8,2.205),(10.8,0.125),(10.2,0.125),(10.2,2.205),(9.68,2.205),(9.68,0.125)])
R(gf180mcu_fd_sc_mcu9t5v0_, pplus, [(-0.2,2.265,14.2,5.24)])
R(gf180mcu_fd_sc_mcu9t5v0_, nplus, [(-0.2,-0.2,14.2,2.265)])
A(gf180mcu_fd_sc_mcu9t5v0_, contact, 0.25, 0.83, 0.22, 0.22, 4, 1, 2.14, 0)
A(gf180mcu_fd_sc_mcu9t5v0_, contact, 1.71, 2.275, 0.22, 0.22, 4, 1, 2.14, 0)
A(gf180mcu_fd_sc_mcu9t5v0_, contact, 1.27, 3.61, 0.22, 0.22, 4, 2, 2.14, 0.47)
A(gf180mcu_fd_sc_mcu9t5v0_, contact, 4.43, 3.71, 0.22, 0.22, 4, 2, 2.14, 0.47)
R(gf180mcu_fd_sc_mcu9t5v0_, contact, [(10.95,0.83,11.17,1.05), (13.19,0.83,13.41,1.05), (12.07,1.145,12.29,1.365), (9.83,1.2,10.05,1.42), (0.25,1.3,0.47,1.52), (4.53,1.3,4.75,1.52), (13.19,1.3,13.41,1.52), (0.755,2.275,0.975,2.495), (9.36,2.275,9.58,2.495), (9.83,2.275,10.05,2.495), (10.95,2.275,11.17,2.495), (9.73,3.61,9.95,3.83), (11.97,3.61,12.19,3.83), (0.25,3.71,0.47,3.93), (13.09,3.71,13.31,3.93), (2.29,3.935,2.51,4.155), (9.73,4.08,9.95,4.3), (11.97,4.08,12.19,4.3), (0.25,4.18,0.47,4.4), (13.09,4.18,13.31,4.4), (2.29,4.405,2.51,4.625)])
P(gf180mcu_fd_sc_mcu9t5v0_, metal1, [(1.21,1.81),(1.21,2.5),(1.99,2.5),(1.99,2.04),(4.41,2.04),(4.41,2.5),(6.27,2.5),(6.27,2.27),(4.64,2.27),(4.64,1.81)],
  [(0.75,2.215),(0.75,2.96),(8.355,2.96),(8.355,2.215),(8.125,2.215),(8.125,2.73),(4.13,2.73),(4.13,2.27),(3.51,2.27),(3.51,2.73),(0.98,2.73),(0.98,2.215)],
  [(9.3,1.77),(9.3,2.5),(11.23,2.5),(11.23,2.27),(9.93,2.27),(9.93,1.77)],
  [(9.825,1.14),(9.825,1.515),(11.965,1.515),(11.965,3.19),(1.265,3.19),(1.265,4.36),(1.495,4.36),(1.495,3.42),(3.405,3.42),(3.405,4.36),(3.635,4.36),(3.635,3.42),(5.545,3.42),(5.545,4.36),(5.775,4.36),(5.775,3.42),(7.685,3.42),(7.685,4.36),(7.915,4.36),(7.915,3.42),(9.725,3.42),(9.725,4.36),(9.955,4.36),(9.955,3.42),(11.965,3.42),(11.965,4.36),(12.195,4.36),(12.195,1.53),(12.79,1.53),(12.79,1.14),(12.01,1.14),(12.01,1.285),(10.055,1.285),(10.055,1.14)],
  [(8.94,0.68),(8.94,1.35),(4.755,1.35),(4.755,0.77),(2.845,0.77),(2.845,1.35),(0.475,1.35),(0.475,0.77),(0.245,0.77),(0.245,1.58),(3.075,1.58),(3.075,1),(4.525,1),(4.525,1.58),(9.17,1.58),(9.17,0.91),(10.89,0.91),(10.89,1.055),(11.23,1.055),(11.23,0.91),(13.185,0.91),(13.185,1.58),(13.415,1.58),(13.415,0.68)],
  [(0,-0.45),(0,0.45),(2.385,0.45),(2.385,1.11),(2.615,1.11),(2.615,0.45),(6.665,0.45),(6.665,1.11),(6.895,1.11),(6.895,0.45),(14,0.45),(14,-0.45)],
  [(0.245,3.65),(0.245,4.59),(0,4.59),(0,5.49),(14,5.49),(14,4.59),(13.315,4.59),(13.315,3.65),(13.085,3.65),(13.085,4.59),(11.075,4.59),(11.075,3.65),(10.845,3.65),(10.845,4.59),(8.935,4.59),(8.935,3.65),(8.705,3.65),(8.705,4.59),(6.795,4.59),(6.795,3.65),(6.565,3.65),(6.565,4.59),(4.655,4.59),(4.655,3.65),(4.425,3.65),(4.425,4.59),(2.515,4.59),(2.515,3.875),(2.285,3.875),(2.285,4.59),(0.475,4.59),(0.475,3.65)])
R(gf180mcu_fd_sc_mcu9t5v0_, dualgate, [(-0.28,-0.28,14.28,5.32)])
R(gf180mcu_fd_sc_mcu9t5v0_, v5_xtor, [(0,0,14,5.04)])
R(gf180mcu_fd_sc_mcu9t5v0_, lvpwell, [(-0.43,-0.43,14.43,2.265)])
gf180mcu_fd_sc_mcu9t5v0_.add(gdstk.Label('A1', (9.8,1.96), layer=34, texttype=10))
gf180mcu_fd_sc_mcu9t5v0_.add(gdstk.Label('A2', (3.64,2.52), layer=34, texttype=10))
gf180mcu_fd_sc_mcu9t5v0_.add(gdstk.Label('A3', (1.4,1.96), layer=34, texttype=10))
gf180mcu_fd_sc_mcu9t5v0_.add(gdstk.Label('VDD', (7,5.49), layer=34, texttype=10))
gf180mcu_fd_sc_mcu9t5v0_.add(gdstk.Label('VSS', (7,-0.45), layer=34, texttype=10))
gf180mcu_fd_sc_mcu9t5v0_.add(gdstk.Label('ZN', (12.6,1.4), layer=34, texttype=10))
gf180mcu_fd_sc_mcu9t5v0_.add(gdstk.Label('& Vendor GLOBALFOUNDRIES', (0,2), layer=63, texttype=63))
gf180mcu_fd_sc_mcu9t5v0_.add(gdstk.Label('& Product GF018hv5v_green_sc9', (0,1.5), layer=63, texttype=63))
gf180mcu_fd_sc_mcu9t5v0_.add(gdstk.Label('& Version 2015q2v2', (0,1), layer=63, texttype=63))
gf180mcu_fd_sc_mcu9t5v0_.add(gdstk.Label('& Metric 1.00', (0,0.5), layer=63, texttype=63))
gf180mcu_fd_sc_mcu9t5v0_.add(gdstk.Label('VNW', (0.345,3.92), layer=21, texttype=10))
gf180mcu_fd_sc_mcu9t5v0_.add(gdstk.Label('VPW', (0.34,-0.085), layer=204, texttype=10))

lib.write_gds('gf180mcu_fd_sc_mcu9t5v0__nand3_4.gds')
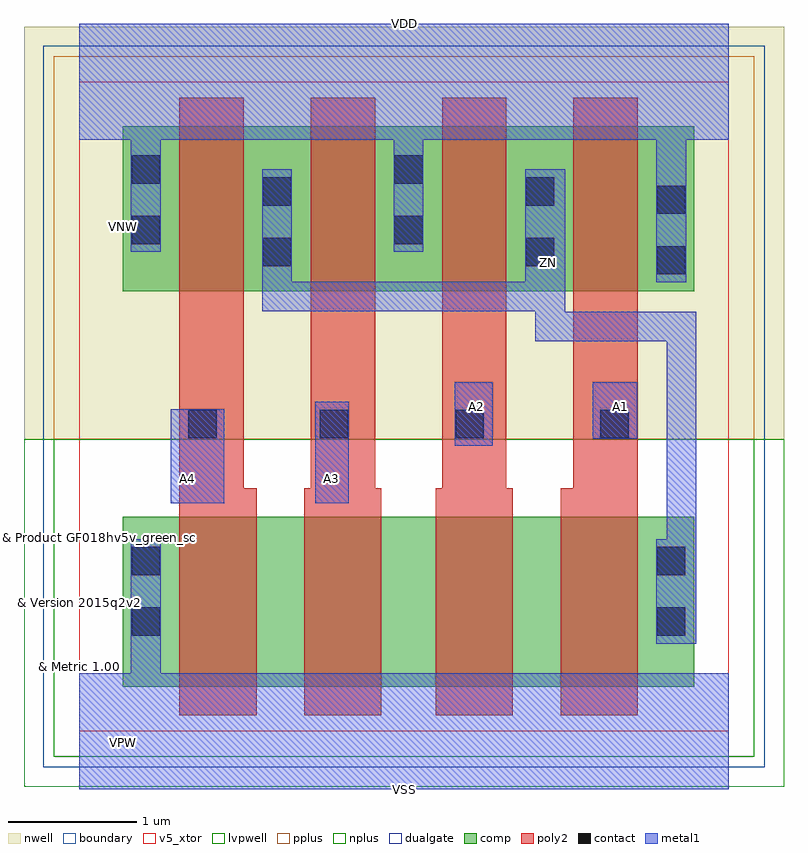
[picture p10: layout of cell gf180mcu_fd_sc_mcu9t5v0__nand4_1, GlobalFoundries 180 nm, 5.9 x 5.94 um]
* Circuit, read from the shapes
.subckt gf180mcu_fd_sc_mcu9t5v0__nand4_1 A1 A2 A3 A4 VDD VNW VSS ZN
XM1 n1 A4 VSS VSUBS nfet_05v0 w=1.32u l=0.6u
XM2 n2 A3 n1 VSUBS nfet_05v0 w=1.32u l=0.6u
XM3 n3 A2 n2 VSUBS nfet_05v0 w=1.32u l=0.6u
XM4 ZN A1 n3 VSUBS nfet_05v0 w=1.32u l=0.6u
XM5 ZN A4 VDD VNW pfet_05v0 w=1.28u l=0.5u
XM6 VDD A3 ZN VNW pfet_05v0 w=1.28u l=0.5u
XM7 ZN A2 VDD VNW pfet_05v0 w=1.28u l=0.5u
XM8 VDD A1 ZN VNW pfet_05v0 w=1.28u l=0.5u
.ends

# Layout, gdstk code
import gdstk
lib = gdstk.Library(unit=1e-6, precision=1e-09)
def R(c, l, rs):  # rectangles x0, y0, x1, y1
    for r in rs: c.add(gdstk.rectangle(r[:2], r[2:], *l))
def P(c, l, *ps):  # polygons
    for p in ps: c.add(gdstk.Polygon(p, *l))
boundary = (0, 0)
nwell = (21, 0)
comp = (22, 0)
poly2 = (30, 0)
pplus = (31, 0)
nplus = (32, 0)
contact = (33, 0)
metal1 = (34, 0)
dualgate = (55, 0)
v5_xtor = (112, 1)
lvpwell = (204, 0)

gf180mcu_fd_sc_mcu9t5v0_ = lib.new_cell('gf180mcu_fd_sc_mcu9t5v0__nand4_1')
R(gf180mcu_fd_sc_mcu9t5v0_, boundary, [(0,0,5.04,5.04)])
R(gf180mcu_fd_sc_mcu9t5v0_, nwell, [(-0.43,2.265,5.47,5.47)])
R(gf180mcu_fd_sc_mcu9t5v0_, comp, [(0.335,0.345,4.775,1.665), (0.335,3.415,4.775,4.695)])
P(gf180mcu_fd_sc_mcu9t5v0_, poly2, [(0.775,0.125),(0.775,4.915),(1.275,4.915),(1.275,1.885),(1.375,1.885),(1.375,0.125)],
  [(1.745,0.125),(1.745,1.885),(1.795,1.885),(1.795,4.915),(2.295,4.915),(2.295,1.885),(2.345,1.885),(2.345,0.125)],
  [(2.765,0.125),(2.765,1.885),(2.815,1.885),(2.815,4.915),(3.315,4.915),(3.315,1.885),(3.365,1.885),(3.365,0.125)],
  [(3.735,0.125),(3.735,1.885),(3.835,1.885),(3.835,4.915),(4.335,4.915),(4.335,0.125)])
R(gf180mcu_fd_sc_mcu9t5v0_, pplus, [(-0.2,2.265,5.24,5.24)])
R(gf180mcu_fd_sc_mcu9t5v0_, nplus, [(-0.2,-0.2,5.24,2.265)])
R(gf180mcu_fd_sc_mcu9t5v0_, contact, [(0.405,0.74,0.625,0.96), (4.485,0.74,4.705,0.96), (0.405,1.21,0.625,1.43), (4.485,1.21,4.705,1.43), (0.845,2.275,1.065,2.495), (1.865,2.275,2.085,2.495), (2.92,2.275,3.14,2.495), (4.045,2.275,4.265,2.495), (4.485,3.545,4.705,3.765), (1.425,3.61,1.645,3.83), (3.465,3.61,3.685,3.83), (0.405,3.78,0.625,4), (2.445,3.78,2.665,4), (4.485,4.015,4.705,4.235), (1.425,4.08,1.645,4.3), (3.465,4.08,3.685,4.3), (0.405,4.25,0.625,4.47), (2.445,4.25,2.665,4.47)])
R(gf180mcu_fd_sc_mcu9t5v0_, metal1, [(0.71,1.77,1.125,2.5), (1.83,1.77,2.09,2.555), (2.915,2.215,3.21,2.71), (3.985,2.27,4.33,2.71)])
P(gf180mcu_fd_sc_mcu9t5v0_, metal1, [(4.48,0.68),(4.48,1.49),(4.56,1.49),(4.56,3.025),(3.54,3.025),(3.54,3.26),(1.42,3.26),(1.42,4.36),(1.65,4.36),(1.65,3.49),(3.46,3.49),(3.46,4.36),(3.77,4.36),(3.77,3.255),(4.79,3.255),(4.79,0.68)],
  [(0,-0.45),(0,0.45),(0.4,0.45),(0.4,1.49),(0.63,1.49),(0.63,0.45),(5.04,0.45),(5.04,-0.45)],
  [(4.48,3.485),(4.48,4.59),(2.67,4.59),(2.67,3.72),(2.44,3.72),(2.44,4.59),(0.63,4.59),(0.63,3.72),(0.4,3.72),(0.4,4.59),(0,4.59),(0,5.49),(5.04,5.49),(5.04,4.59),(4.71,4.59),(4.71,3.485)])
R(gf180mcu_fd_sc_mcu9t5v0_, dualgate, [(-0.28,-0.28,5.32,5.32)])
R(gf180mcu_fd_sc_mcu9t5v0_, v5_xtor, [(0,0,5.04,5.04)])
R(gf180mcu_fd_sc_mcu9t5v0_, lvpwell, [(-0.43,-0.43,5.47,2.265)])
gf180mcu_fd_sc_mcu9t5v0_.add(gdstk.Label('A1', (4.2,2.52), layer=34, texttype=10))
gf180mcu_fd_sc_mcu9t5v0_.add(gdstk.Label('A2', (3.08,2.52), layer=34, texttype=10))
gf180mcu_fd_sc_mcu9t5v0_.add(gdstk.Label('A3', (1.96,1.96), layer=34, texttype=10))
gf180mcu_fd_sc_mcu9t5v0_.add(gdstk.Label('A4', (0.84,1.96), layer=34, texttype=10))
gf180mcu_fd_sc_mcu9t5v0_.add(gdstk.Label('VDD', (2.52,5.49), layer=34, texttype=10))
gf180mcu_fd_sc_mcu9t5v0_.add(gdstk.Label('VSS', (2.52,-0.45), layer=34, texttype=10))
gf180mcu_fd_sc_mcu9t5v0_.add(gdstk.Label('ZN', (3.64,3.64), layer=34, texttype=10))
gf180mcu_fd_sc_mcu9t5v0_.add(gdstk.Label('& Vendor GLOBALFOUNDRIES', (0,2), layer=63, texttype=63))
gf180mcu_fd_sc_mcu9t5v0_.add(gdstk.Label('& Product GF018hv5v_green_sc9', (0,1.5), layer=63, texttype=63))
gf180mcu_fd_sc_mcu9t5v0_.add(gdstk.Label('& Version 2015q2v2', (0,1), layer=63, texttype=63))
gf180mcu_fd_sc_mcu9t5v0_.add(gdstk.Label('& Metric 1.00', (0,0.5), layer=63, texttype=63))
gf180mcu_fd_sc_mcu9t5v0_.add(gdstk.Label('VNW', (0.345,3.92), layer=21, texttype=10))
gf180mcu_fd_sc_mcu9t5v0_.add(gdstk.Label('VPW', (0.34,-0.085), layer=204, texttype=10))

lib.write_gds('gf180mcu_fd_sc_mcu9t5v0__nand4_1.gds')
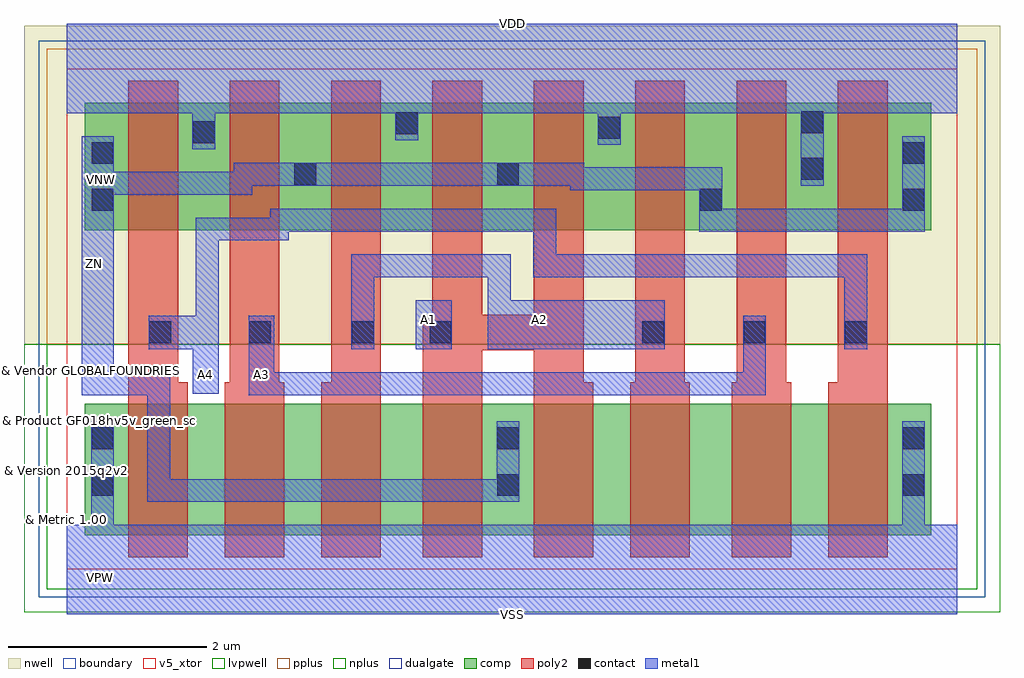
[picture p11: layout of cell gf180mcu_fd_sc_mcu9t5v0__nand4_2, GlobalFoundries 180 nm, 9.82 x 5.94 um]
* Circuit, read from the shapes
.subckt gf180mcu_fd_sc_mcu9t5v0__nand4_2 A1 A2 A3 A4 VDD VNW VSS ZN
XM1 n1 A4 VSS VSUBS nfet_05v0 w=1.32u l=0.6u
XM2 n2 A3 n1 VSUBS nfet_05v0 w=1.32u l=0.6u
XM3 n3 A2 n2 VSUBS nfet_05v0 w=1.32u l=0.6u
XM4 ZN A1 n3 VSUBS nfet_05v0 w=1.32u l=0.6u
XM5 n4 A1 ZN VSUBS nfet_05v0 w=1.32u l=0.6u
XM6 n5 A2 n4 VSUBS nfet_05v0 w=1.32u l=0.6u
XM7 n6 A3 n5 VSUBS nfet_05v0 w=1.32u l=0.6u
XM8 VSS A4 n6 VSUBS nfet_05v0 w=1.32u l=0.6u
XM9 VDD A4 ZN VNW pfet_05v0 w=1.28u l=0.5u m=2
XM10 ZN A3 VDD VNW pfet_05v0 w=1.28u l=0.5u m=2
XM11 VDD A2 ZN VNW pfet_05v0 w=1.28u l=0.5u m=2
XM12 ZN A1 VDD VNW pfet_05v0 w=1.28u l=0.5u m=2
.ends

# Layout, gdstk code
import gdstk
lib = gdstk.Library(unit=1e-6, precision=1e-09)
def R(c, l, rs):  # rectangles x0, y0, x1, y1
    for r in rs: c.add(gdstk.rectangle(r[:2], r[2:], *l))
def A(c, l, x, y, w, h, nx, ny, dx, dy):  # array of equal rectangles
    R(c, l, [(x+i*dx, y+j*dy, x+i*dx+w, y+j*dy+h) for i in range(nx) for j in range(ny)])
def P(c, l, *ps):  # polygons
    for p in ps: c.add(gdstk.Polygon(p, *l))
boundary = (0, 0)
nwell = (21, 0)
comp = (22, 0)
poly2 = (30, 0)
pplus = (31, 0)
nplus = (32, 0)
contact = (33, 0)
metal1 = (34, 0)
dualgate = (55, 0)
v5_xtor = (112, 1)
lvpwell = (204, 0)

gf180mcu_fd_sc_mcu9t5v0_ = lib.new_cell('gf180mcu_fd_sc_mcu9t5v0__nand4_2')
R(gf180mcu_fd_sc_mcu9t5v0_, boundary, [(0,0,8.96,5.04)])
R(gf180mcu_fd_sc_mcu9t5v0_, nwell, [(-0.43,2.265,9.39,5.47)])
R(gf180mcu_fd_sc_mcu9t5v0_, comp, [(0.18,0.345,8.7,1.665), (0.18,3.415,8.7,4.695)])
P(gf180mcu_fd_sc_mcu9t5v0_, poly2, [(0.62,0.125),(0.62,4.915),(1.12,4.915),(1.12,1.885),(1.22,1.885),(1.22,0.125)],
  [(1.59,0.125),(1.59,1.885),(1.64,1.885),(1.64,4.915),(2.14,4.915),(2.14,1.885),(2.19,1.885),(2.19,0.125)],
  [(2.56,0.125),(2.56,1.885),(2.66,1.885),(2.66,4.915),(3.16,4.915),(3.16,0.125)],
  [(3.58,0.125),(3.58,2.565),(3.68,2.565),(3.68,4.915),(4.18,4.915),(4.18,2.565),(4.7,2.565),(4.7,4.915),(5.2,4.915),(5.2,1.885),(5.3,1.885),(5.3,0.125),(4.7,0.125),(4.7,2.205),(4.18,2.205),(4.18,0.125)],
  [(5.67,0.125),(5.67,1.885),(5.72,1.885),(5.72,4.915),(6.22,4.915),(6.22,1.885),(6.27,1.885),(6.27,0.125)],
  [(6.69,0.125),(6.69,1.885),(6.74,1.885),(6.74,4.915),(7.24,4.915),(7.24,1.885),(7.29,1.885),(7.29,0.125)],
  [(7.66,0.125),(7.66,1.885),(7.76,1.885),(7.76,4.915),(8.26,4.915),(8.26,0.125)])
R(gf180mcu_fd_sc_mcu9t5v0_, pplus, [(-0.2,2.265,9.16,5.24)])
R(gf180mcu_fd_sc_mcu9t5v0_, nplus, [(-0.2,-0.2,9.16,2.265)])
A(gf180mcu_fd_sc_mcu9t5v0_, contact, 0.25, 0.74, 0.22, 0.22, 3, 2, 4.08, 0.47)
A(gf180mcu_fd_sc_mcu9t5v0_, contact, 5.79, 2.275, 0.22, 0.22, 3, 1, 1.02, 0)
R(gf180mcu_fd_sc_mcu9t5v0_, contact, [(0.83,2.275,1.05,2.495), (1.835,2.275,2.055,2.495), (2.87,2.275,3.09,2.495), (3.65,2.275,3.87,2.495), (0.25,3.61,0.47,3.83), (6.37,3.61,6.59,3.83), (8.41,3.61,8.63,3.83), (2.29,3.865,2.51,4.085), (4.33,3.865,4.55,4.085), (7.39,3.92,7.61,4.14), (0.25,4.08,0.47,4.3), (8.41,4.08,8.63,4.3), (1.27,4.29,1.49,4.51), (5.35,4.335,5.57,4.555), (3.31,4.38,3.53,4.6), (7.39,4.39,7.61,4.61)])
R(gf180mcu_fd_sc_mcu9t5v0_, metal1, [(3.51,2.215,3.875,2.71)])
P(gf180mcu_fd_sc_mcu9t5v0_, metal1, [(2.865,2.215),(2.865,3.17),(4.465,3.17),(4.465,2.71),(6.015,2.71),(6.015,2.215),(4.235,2.215),(4.235,2.94),(3.095,2.94),(3.095,2.215)],
  [(1.83,1.755),(1.83,2.555),(2.09,2.555),(2.09,1.985),(6.805,1.985),(6.805,2.555),(7.035,2.555),(7.035,1.755)],
  [(1.27,1.77),(1.27,2.215),(0.825,2.215),(0.825,2.555),(1.3,2.555),(1.3,3.54),(2.05,3.54),(2.05,3.63),(4.925,3.63),(4.925,3.17),(8.055,3.17),(8.055,2.215),(7.825,2.215),(7.825,2.94),(4.695,2.94),(4.695,3.4),(2.235,3.4),(2.235,3.31),(1.53,3.31),(1.53,1.77)],
  [(0.81,0.68),(0.81,1.755),(0.15,1.755),(0.15,4.36),(0.475,4.36),(0.475,4),(1.68,4),(1.68,4.09),(5.205,4.09),(5.205,4.045),(6.595,4.045),(6.595,3.63),(8.405,3.63),(8.405,4.36),(8.635,4.36),(8.635,3.4),(6.365,3.4),(6.365,3.815),(5.065,3.815),(5.065,3.86),(1.865,3.86),(1.865,3.77),(0.475,3.77),(0.475,1.985),(1.04,1.985),(1.04,0.91),(4.325,0.91),(4.325,1.49),(4.555,1.49),(4.555,0.68)],
  [(0,-0.45),(0,0.45),(0.245,0.45),(0.245,1.49),(0.475,1.49),(0.475,0.45),(8.405,0.45),(8.405,1.49),(8.635,1.49),(8.635,0.45),(8.96,0.45),(8.96,-0.45)],
  [(7.385,3.86),(7.385,4.59),(5.575,4.59),(5.575,4.275),(5.345,4.275),(5.345,4.59),(3.535,4.59),(3.535,4.32),(3.305,4.32),(3.305,4.59),(1.495,4.59),(1.495,4.23),(1.265,4.23),(1.265,4.59),(0,4.59),(0,5.49),(8.96,5.49),(8.96,4.59),(7.615,4.59),(7.615,3.86)])
R(gf180mcu_fd_sc_mcu9t5v0_, dualgate, [(-0.28,-0.28,9.24,5.32)])
R(gf180mcu_fd_sc_mcu9t5v0_, v5_xtor, [(0,0,8.96,5.04)])
R(gf180mcu_fd_sc_mcu9t5v0_, lvpwell, [(-0.43,-0.43,9.39,2.265)])
gf180mcu_fd_sc_mcu9t5v0_.add(gdstk.Label('A1', (3.64,2.52), layer=34, texttype=10))
gf180mcu_fd_sc_mcu9t5v0_.add(gdstk.Label('A2', (4.76,2.52), layer=34, texttype=10))
gf180mcu_fd_sc_mcu9t5v0_.add(gdstk.Label('A3', (1.96,1.96), layer=34, texttype=10))
gf180mcu_fd_sc_mcu9t5v0_.add(gdstk.Label('A4', (1.4,1.96), layer=34, texttype=10))
gf180mcu_fd_sc_mcu9t5v0_.add(gdstk.Label('VDD', (4.48,5.49), layer=34, texttype=10))
gf180mcu_fd_sc_mcu9t5v0_.add(gdstk.Label('VSS', (4.48,-0.45), layer=34, texttype=10))
gf180mcu_fd_sc_mcu9t5v0_.add(gdstk.Label('ZN', (0.28,3.08), layer=34, texttype=10))
gf180mcu_fd_sc_mcu9t5v0_.add(gdstk.Label('& Vendor GLOBALFOUNDRIES', (0,2), layer=63, texttype=63))
gf180mcu_fd_sc_mcu9t5v0_.add(gdstk.Label('& Product GF018hv5v_green_sc9', (0,1.5), layer=63, texttype=63))
gf180mcu_fd_sc_mcu9t5v0_.add(gdstk.Label('& Version 2015q2v2', (0,1), layer=63, texttype=63))
gf180mcu_fd_sc_mcu9t5v0_.add(gdstk.Label('& Metric 1.00', (0,0.5), layer=63, texttype=63))
gf180mcu_fd_sc_mcu9t5v0_.add(gdstk.Label('VNW', (0.345,3.92), layer=21, texttype=10))
gf180mcu_fd_sc_mcu9t5v0_.add(gdstk.Label('VPW', (0.34,-0.085), layer=204, texttype=10))

lib.write_gds('gf180mcu_fd_sc_mcu9t5v0__nand4_2.gds')
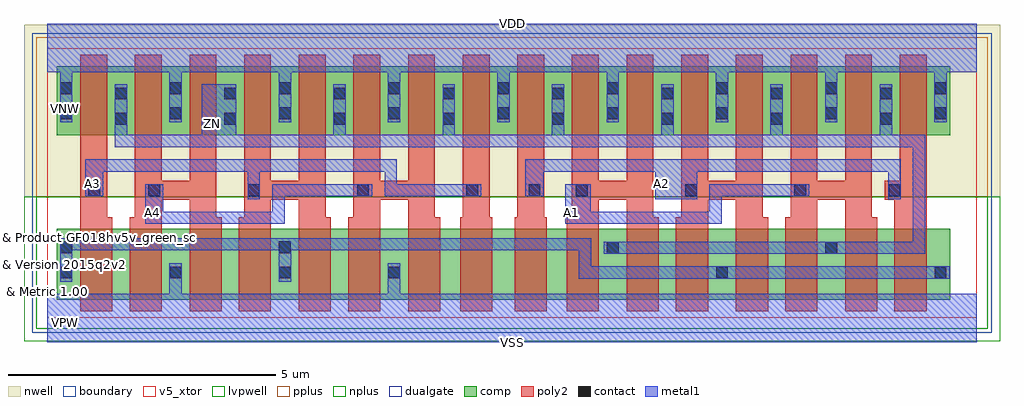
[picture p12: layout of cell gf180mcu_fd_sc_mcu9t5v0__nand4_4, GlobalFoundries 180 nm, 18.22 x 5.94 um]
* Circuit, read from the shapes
.subckt gf180mcu_fd_sc_mcu9t5v0__nand4_4 A1 A2 A3 A4 VDD VNW VSS ZN
XM1 n1 A3 n2 VSUBS nfet_05v0 w=1.32u l=0.6u
XM2 VSS A4 n1 VSUBS nfet_05v0 w=1.32u l=0.6u
XM3 n3 A4 VSS VSUBS nfet_05v0 w=1.32u l=0.6u
XM4 n2 A3 n3 VSUBS nfet_05v0 w=1.32u l=0.6u
XM5 n4 A3 n2 VSUBS nfet_05v0 w=1.32u l=0.6u
XM6 VSS A4 n4 VSUBS nfet_05v0 w=1.32u l=0.6u
XM7 n5 A4 VSS VSUBS nfet_05v0 w=1.32u l=0.6u
XM8 n6 A3 n5 VSUBS nfet_05v0 w=1.32u l=0.6u
XM9 n7 A2 n6 VSUBS nfet_05v0 w=1.32u l=0.6u
XM10 ZN A1 n7 VSUBS nfet_05v0 w=1.32u l=0.6u
XM11 n8 A1 ZN VSUBS nfet_05v0 w=1.32u l=0.6u
XM12 n2 A2 n8 VSUBS nfet_05v0 w=1.32u l=0.6u
XM13 n9 A2 n2 VSUBS nfet_05v0 w=1.32u l=0.6u
XM14 ZN A1 n9 VSUBS nfet_05v0 w=1.32u l=0.6u
XM15 n10 A1 ZN VSUBS nfet_05v0 w=1.32u l=0.6u
XM16 n2 A2 n10 VSUBS nfet_05v0 w=1.32u l=0.6u
XM17 ZN A3 VDD VNW pfet_05v0 w=1.28u l=0.5u m=4
XM18 VDD A4 ZN VNW pfet_05v0 w=1.28u l=0.5u m=4
XM19 ZN A2 VDD VNW pfet_05v0 w=1.28u l=0.5u m=4
XM20 VDD A1 ZN VNW pfet_05v0 w=1.28u l=0.5u m=4
.ends

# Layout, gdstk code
import gdstk
lib = gdstk.Library(unit=1e-6, precision=1e-09)
def R(c, l, rs):  # rectangles x0, y0, x1, y1
    for r in rs: c.add(gdstk.rectangle(r[:2], r[2:], *l))
def A(c, l, x, y, w, h, nx, ny, dx, dy):  # array of equal rectangles
    R(c, l, [(x+i*dx, y+j*dy, x+i*dx+w, y+j*dy+h) for i in range(nx) for j in range(ny)])
def P(c, l, *ps):  # polygons
    for p in ps: c.add(gdstk.Polygon(p, *l))
boundary = (0, 0)
nwell = (21, 0)
comp = (22, 0)
poly2 = (30, 0)
pplus = (31, 0)
nplus = (32, 0)
contact = (33, 0)
metal1 = (34, 0)
dualgate = (55, 0)
v5_xtor = (112, 1)
lvpwell = (204, 0)

gf180mcu_fd_sc_mcu9t5v0_ = lib.new_cell('gf180mcu_fd_sc_mcu9t5v0__nand4_4')
R(gf180mcu_fd_sc_mcu9t5v0_, boundary, [(0,0,17.36,5.04)])
R(gf180mcu_fd_sc_mcu9t5v0_, nwell, [(-0.43,2.265,17.79,5.47)])
R(gf180mcu_fd_sc_mcu9t5v0_, comp, [(0.18,0.345,16.86,1.665), (0.18,3.415,16.86,4.695)])
P(gf180mcu_fd_sc_mcu9t5v0_, poly2, [(0.62,0.125),(0.62,4.915),(1.12,4.915),(1.12,1.885),(1.22,1.885),(1.22,0.125)],
  [(1.54,0.125),(1.54,1.885),(1.64,1.885),(1.64,4.915),(2.14,4.915),(2.14,2.565),(2.66,2.565),(2.66,4.915),(3.16,4.915),(3.16,1.885),(3.26,1.885),(3.26,0.125),(2.66,0.125),(2.66,2.205),(2.14,2.205),(2.14,0.125)],
  [(3.58,0.125),(3.58,1.885),(3.68,1.885),(3.68,4.915),(4.18,4.915),(4.18,2.565),(4.7,2.565),(4.7,4.915),(5.2,4.915),(5.2,1.885),(5.3,1.885),(5.3,0.125),(4.7,0.125),(4.7,2.205),(4.18,2.205),(4.18,0.125)],
  [(5.62,0.125),(5.62,1.885),(5.72,1.885),(5.72,4.915),(6.22,4.915),(6.22,2.565),(6.74,2.565),(6.74,4.915),(7.24,4.915),(7.24,1.885),(7.34,1.885),(7.34,0.125),(6.74,0.125),(6.74,2.205),(6.22,2.205),(6.22,0.125)],
  [(7.71,0.125),(7.71,1.885),(7.76,1.885),(7.76,4.915),(8.26,4.915),(8.26,1.885),(8.31,1.885),(8.31,0.125)],
  [(8.73,0.125),(8.73,1.885),(8.78,1.885),(8.78,4.915),(9.28,4.915),(9.28,1.885),(9.33,1.885),(9.33,0.125)],
  [(9.7,0.125),(9.7,1.885),(9.8,1.885),(9.8,4.915),(10.3,4.915),(10.3,2.565),(10.82,2.565),(10.82,4.915),(11.32,4.915),(11.32,1.885),(11.42,1.885),(11.42,0.125),(10.82,0.125),(10.82,2.205),(10.3,2.205),(10.3,0.125)],
  [(11.74,0.125),(11.74,1.885),(11.84,1.885),(11.84,4.915),(12.34,4.915),(12.34,2.565),(12.86,2.565),(12.86,4.915),(13.36,4.915),(13.36,1.885),(13.46,1.885),(13.46,0.125),(12.86,0.125),(12.86,2.205),(12.34,2.205),(12.34,0.125)],
  [(13.78,0.125),(13.78,1.885),(13.88,1.885),(13.88,4.915),(14.38,4.915),(14.38,2.565),(14.9,2.565),(14.9,4.915),(15.4,4.915),(15.4,1.885),(15.5,1.885),(15.5,0.125),(14.9,0.125),(14.9,2.205),(14.38,2.205),(14.38,0.125)],
  [(15.82,0.125),(15.82,2.205),(15.64,2.205),(15.64,2.565),(15.92,2.565),(15.92,4.915),(16.42,4.915),(16.42,0.125)])
R(gf180mcu_fd_sc_mcu9t5v0_, pplus, [(-0.2,2.265,17.56,5.24)])
R(gf180mcu_fd_sc_mcu9t5v0_, nplus, [(-0.2,-0.2,17.56,2.265)])
A(gf180mcu_fd_sc_mcu9t5v0_, contact, 0.25, 0.74, 0.22, 0.22, 4, 1, 2.04, 0)
A(gf180mcu_fd_sc_mcu9t5v0_, contact, 3.75, 2.275, 0.22, 0.22, 3, 1, 2.04, 0)
A(gf180mcu_fd_sc_mcu9t5v0_, contact, 9.87, 2.275, 0.22, 0.22, 3, 1, 2.04, 0)
A(gf180mcu_fd_sc_mcu9t5v0_, contact, 1.27, 3.61, 0.22, 0.22, 8, 2, 2.04, 0.47)
A(gf180mcu_fd_sc_mcu9t5v0_, contact, 0.25, 3.71, 0.22, 0.22, 9, 2, 2.04, 0.47)
R(gf180mcu_fd_sc_mcu9t5v0_, contact, [(12.49,0.74,12.71,0.96), (16.57,0.74,16.79,0.96), (10.45,1.2,10.67,1.42), (14.53,1.2,14.75,1.42), (0.25,1.21,0.47,1.43), (4.33,1.21,4.55,1.43), (0.77,2.275,0.99,2.495), (1.89,2.275,2.11,2.495), (8.99,2.275,9.21,2.495), (15.71,2.275,15.93,2.495)])
P(gf180mcu_fd_sc_mcu9t5v0_, metal1, [(1.83,1.755),(1.83,2.5),(2.17,2.5),(2.17,1.985),(4.205,1.985),(4.205,2.5),(6.07,2.5),(6.07,2.27),(4.435,2.27),(4.435,1.755)],
  [(3.745,2.215),(3.745,2.73),(1.05,2.73),(1.05,2.27),(0.71,2.27),(0.71,2.96),(6.53,2.96),(6.53,2.5),(8.11,2.5),(8.11,2.27),(6.3,2.27),(6.3,2.73),(3.975,2.73),(3.975,2.215)],
  [(9.67,1.755),(9.67,2.5),(10.15,2.5),(10.15,1.985),(12.365,1.985),(12.365,2.5),(14.23,2.5),(14.23,2.27),(12.595,2.27),(12.595,1.755)],
  [(11.35,2.215),(11.35,2.73),(9.27,2.73),(9.27,2.27),(8.93,2.27),(8.93,2.96),(15.935,2.96),(15.935,2.215),(15.705,2.215),(15.705,2.73),(12.135,2.73),(12.135,2.215)],
  [(10.39,1.195),(10.39,1.425),(16.165,1.425),(16.165,3.19),(1.265,3.19),(1.265,4.36),(1.495,4.36),(1.495,3.42),(2.89,3.42),(2.89,4.36),(3.535,4.36),(3.535,3.42),(5.345,3.42),(5.345,4.36),(5.575,4.36),(5.575,3.42),(7.385,3.42),(7.385,4.36),(7.615,4.36),(7.615,3.42),(9.425,3.42),(9.425,4.36),(9.655,4.36),(9.655,3.42),(11.465,3.42),(11.465,4.36),(11.695,4.36),(11.695,3.42),(13.505,3.42),(13.505,4.36),(13.735,4.36),(13.735,3.42),(15.545,3.42),(15.545,4.36),(15.775,4.36),(15.775,3.42),(16.395,3.42),(16.395,1.195)],
  [(0.245,0.68),(0.245,1.49),(10.16,1.49),(10.16,0.965),(16.85,0.965),(16.85,0.735),(9.93,0.735),(9.93,1.26),(4.555,1.26),(4.555,0.68),(4.325,0.68),(4.325,1.26),(0.475,1.26),(0.475,0.68)],
  [(0,-0.45),(0,0.45),(2.285,0.45),(2.285,1.02),(2.515,1.02),(2.515,0.45),(6.365,0.45),(6.365,1.02),(6.595,1.02),(6.595,0.45),(17.36,0.45),(17.36,-0.45)],
  [(0.245,3.65),(0.245,4.59),(0,4.59),(0,5.49),(17.36,5.49),(17.36,4.59),(16.795,4.59),(16.795,3.65),(16.565,3.65),(16.565,4.59),(14.755,4.59),(14.755,3.65),(14.525,3.65),(14.525,4.59),(12.715,4.59),(12.715,3.65),(12.485,3.65),(12.485,4.59),(10.675,4.59),(10.675,3.65),(10.445,3.65),(10.445,4.59),(8.635,4.59),(8.635,3.65),(8.405,3.65),(8.405,4.59),(6.595,4.59),(6.595,3.65),(6.365,3.65),(6.365,4.59),(4.555,4.59),(4.555,3.65),(4.325,3.65),(4.325,4.59),(2.515,4.59),(2.515,3.65),(2.285,3.65),(2.285,4.59),(0.475,4.59),(0.475,3.65)])
R(gf180mcu_fd_sc_mcu9t5v0_, dualgate, [(-0.28,-0.28,17.64,5.32)])
R(gf180mcu_fd_sc_mcu9t5v0_, v5_xtor, [(0,0,17.36,5.04)])
R(gf180mcu_fd_sc_mcu9t5v0_, lvpwell, [(-0.43,-0.43,17.79,2.265)])
gf180mcu_fd_sc_mcu9t5v0_.add(gdstk.Label('A1', (9.8,1.96), layer=34, texttype=10))
gf180mcu_fd_sc_mcu9t5v0_.add(gdstk.Label('A2', (11.48,2.52), layer=34, texttype=10))
gf180mcu_fd_sc_mcu9t5v0_.add(gdstk.Label('A3', (0.84,2.52), layer=34, texttype=10))
gf180mcu_fd_sc_mcu9t5v0_.add(gdstk.Label('A4', (1.96,1.96), layer=34, texttype=10))
gf180mcu_fd_sc_mcu9t5v0_.add(gdstk.Label('VDD', (8.68,5.49), layer=34, texttype=10))
gf180mcu_fd_sc_mcu9t5v0_.add(gdstk.Label('VSS', (8.68,-0.45), layer=34, texttype=10))
gf180mcu_fd_sc_mcu9t5v0_.add(gdstk.Label('ZN', (3.08,3.64), layer=34, texttype=10))
gf180mcu_fd_sc_mcu9t5v0_.add(gdstk.Label('& Vendor GLOBALFOUNDRIES', (0,2), layer=63, texttype=63))
gf180mcu_fd_sc_mcu9t5v0_.add(gdstk.Label('& Product GF018hv5v_green_sc9', (0,1.5), layer=63, texttype=63))
gf180mcu_fd_sc_mcu9t5v0_.add(gdstk.Label('& Version 2015q2v2', (0,1), layer=63, texttype=63))
gf180mcu_fd_sc_mcu9t5v0_.add(gdstk.Label('& Metric 1.00', (0,0.5), layer=63, texttype=63))
gf180mcu_fd_sc_mcu9t5v0_.add(gdstk.Label('VNW', (0.345,3.92), layer=21, texttype=10))
gf180mcu_fd_sc_mcu9t5v0_.add(gdstk.Label('VPW', (0.34,-0.085), layer=204, texttype=10))

lib.write_gds('gf180mcu_fd_sc_mcu9t5v0__nand4_4.gds')
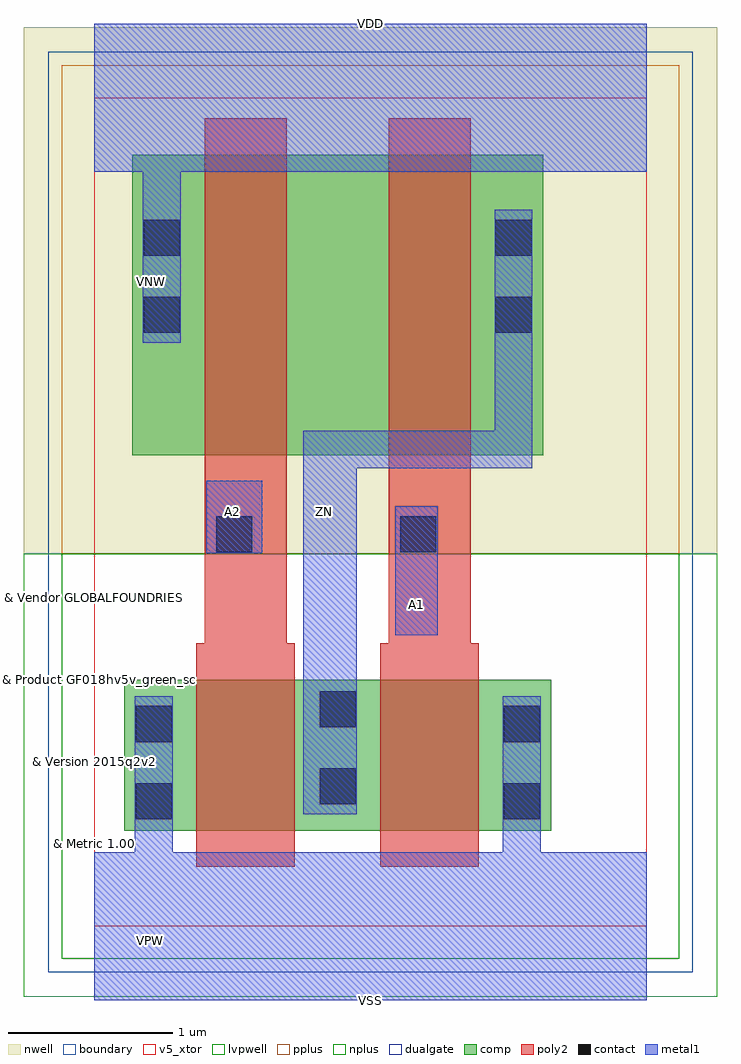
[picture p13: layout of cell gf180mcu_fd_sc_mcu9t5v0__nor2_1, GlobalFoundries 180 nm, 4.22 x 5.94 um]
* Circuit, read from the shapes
.subckt gf180mcu_fd_sc_mcu9t5v0__nor2_1 A1 A2 VDD VNW VSS ZN
XM1 ZN A2 VSS VSUBS nfet_05v0 w=0.92u l=0.6u
XM2 VSS A1 ZN VSUBS nfet_05v0 w=0.92u l=0.6u
XM3 n1 A2 VDD VNW pfet_05v0 w=1.83u l=0.5u
XM4 ZN A1 n1 VNW pfet_05v0 w=1.83u l=0.5u
.ends

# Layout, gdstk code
import gdstk
lib = gdstk.Library(unit=1e-6, precision=1e-09)
def R(c, l, rs):  # rectangles x0, y0, x1, y1
    for r in rs: c.add(gdstk.rectangle(r[:2], r[2:], *l))
def P(c, l, *ps):  # polygons
    for p in ps: c.add(gdstk.Polygon(p, *l))
boundary = (0, 0)
nwell = (21, 0)
comp = (22, 0)
poly2 = (30, 0)
pplus = (31, 0)
nplus = (32, 0)
contact = (33, 0)
metal1 = (34, 0)
dualgate = (55, 0)
v5_xtor = (112, 1)
lvpwell = (204, 0)

gf180mcu_fd_sc_mcu9t5v0_ = lib.new_cell('gf180mcu_fd_sc_mcu9t5v0__nor2_1')
R(gf180mcu_fd_sc_mcu9t5v0_, boundary, [(0,0,3.36,5.04)])
R(gf180mcu_fd_sc_mcu9t5v0_, nwell, [(-0.43,2.265,3.79,5.47)])
R(gf180mcu_fd_sc_mcu9t5v0_, comp, [(0.18,0.58,2.78,1.5), (0.23,2.865,2.73,4.695)])
P(gf180mcu_fd_sc_mcu9t5v0_, poly2, [(0.62,0.36),(0.62,1.72),(0.67,1.72),(0.67,4.915),(1.17,4.915),(1.17,1.72),(1.22,1.72),(1.22,0.36)],
  [(1.74,0.36),(1.74,1.72),(1.79,1.72),(1.79,4.915),(2.29,4.915),(2.29,1.72),(2.34,1.72),(2.34,0.36)])
R(gf180mcu_fd_sc_mcu9t5v0_, pplus, [(-0.2,2.265,3.56,5.24)])
R(gf180mcu_fd_sc_mcu9t5v0_, nplus, [(-0.2,-0.2,3.56,2.265)])
R(gf180mcu_fd_sc_mcu9t5v0_, contact, [(0.25,0.65,0.47,0.87), (2.49,0.65,2.71,0.87), (1.37,0.74,1.59,0.96), (0.25,1.12,0.47,1.34), (2.49,1.12,2.71,1.34), (1.37,1.21,1.59,1.43), (0.74,2.275,0.96,2.495), (1.86,2.275,2.08,2.495), (0.3,3.61,0.52,3.83), (2.44,3.61,2.66,3.83), (0.3,4.08,0.52,4.3), (2.44,4.08,2.66,4.3)])
R(gf180mcu_fd_sc_mcu9t5v0_, metal1, [(1.83,1.77,2.09,2.555), (0.68,2.27,1.02,2.71)])
P(gf180mcu_fd_sc_mcu9t5v0_, metal1, [(1.27,0.68),(1.27,3.015),(2.435,3.015),(2.435,4.36),(2.665,4.36),(2.665,2.785),(1.595,2.785),(1.595,0.68)],
  [(0,-0.45),(0,0.45),(0.245,0.45),(0.245,1.4),(0.475,1.4),(0.475,0.45),(2.485,0.45),(2.485,1.4),(2.715,1.4),(2.715,0.45),(3.36,0.45),(3.36,-0.45)],
  [(0.295,3.55),(0.295,4.59),(0,4.59),(0,5.49),(3.36,5.49),(3.36,4.59),(0.525,4.59),(0.525,3.55)])
R(gf180mcu_fd_sc_mcu9t5v0_, dualgate, [(-0.28,-0.28,3.64,5.32)])
R(gf180mcu_fd_sc_mcu9t5v0_, v5_xtor, [(0,0,3.36,5.04)])
R(gf180mcu_fd_sc_mcu9t5v0_, lvpwell, [(-0.43,-0.43,3.79,2.265)])
gf180mcu_fd_sc_mcu9t5v0_.add(gdstk.Label('A1', (1.96,1.96), layer=34, texttype=10))
gf180mcu_fd_sc_mcu9t5v0_.add(gdstk.Label('A2', (0.84,2.52), layer=34, texttype=10))
gf180mcu_fd_sc_mcu9t5v0_.add(gdstk.Label('VDD', (1.68,5.49), layer=34, texttype=10))
gf180mcu_fd_sc_mcu9t5v0_.add(gdstk.Label('VSS', (1.68,-0.45), layer=34, texttype=10))
gf180mcu_fd_sc_mcu9t5v0_.add(gdstk.Label('ZN', (1.4,2.52), layer=34, texttype=10))
gf180mcu_fd_sc_mcu9t5v0_.add(gdstk.Label('& Vendor GLOBALFOUNDRIES', (0,2), layer=63, texttype=63))
gf180mcu_fd_sc_mcu9t5v0_.add(gdstk.Label('& Product GF018hv5v_green_sc9', (0,1.5), layer=63, texttype=63))
gf180mcu_fd_sc_mcu9t5v0_.add(gdstk.Label('& Version 2015q2v2', (0,1), layer=63, texttype=63))
gf180mcu_fd_sc_mcu9t5v0_.add(gdstk.Label('& Metric 1.00', (0,0.5), layer=63, texttype=63))
gf180mcu_fd_sc_mcu9t5v0_.add(gdstk.Label('VNW', (0.345,3.92), layer=21, texttype=10))
gf180mcu_fd_sc_mcu9t5v0_.add(gdstk.Label('VPW', (0.34,-0.085), layer=204, texttype=10))

lib.write_gds('gf180mcu_fd_sc_mcu9t5v0__nor2_1.gds')
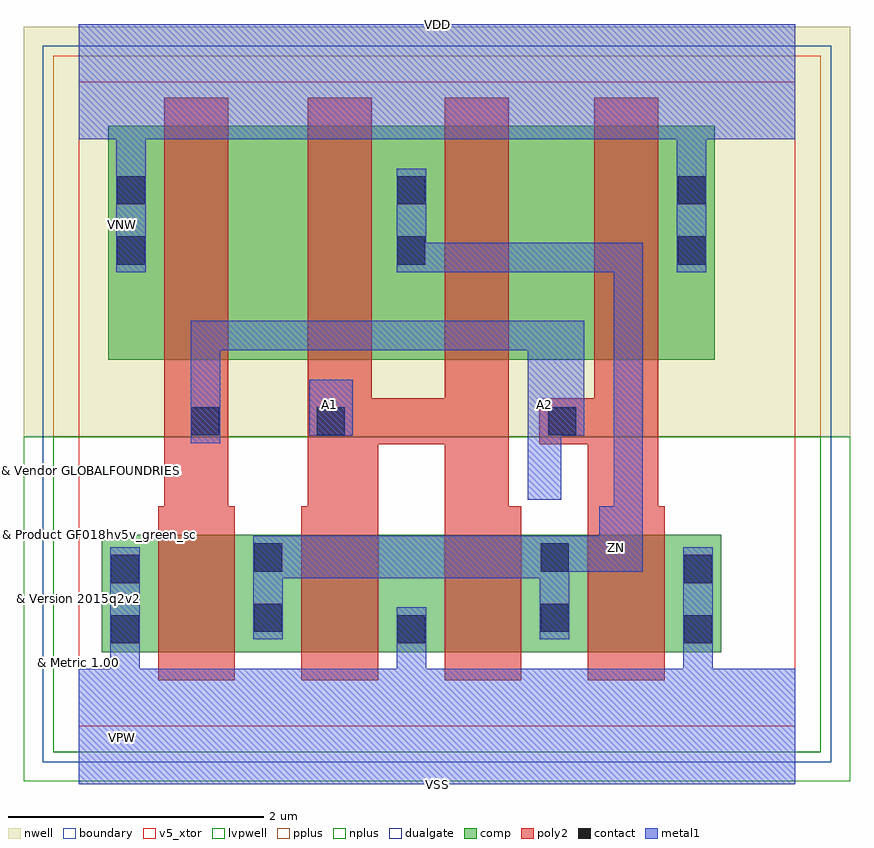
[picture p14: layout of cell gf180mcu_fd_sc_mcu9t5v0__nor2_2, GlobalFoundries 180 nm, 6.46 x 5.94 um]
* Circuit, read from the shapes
.subckt gf180mcu_fd_sc_mcu9t5v0__nor2_2 A1 A2 VDD VNW VSS ZN
XM1 ZN A2 VSS VSUBS nfet_05v0 w=0.92u l=0.6u m=2
XM2 VSS A1 ZN VSUBS nfet_05v0 w=0.92u l=0.6u m=2
XM3 n1 A2 VDD VNW pfet_05v0 w=1.83u l=0.5u
XM4 ZN A1 n1 VNW pfet_05v0 w=1.83u l=0.5u
XM5 n2 A1 ZN VNW pfet_05v0 w=1.83u l=0.5u
XM6 VDD A2 n2 VNW pfet_05v0 w=1.83u l=0.5u
.ends

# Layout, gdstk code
import gdstk
lib = gdstk.Library(unit=1e-6, precision=1e-09)
def R(c, l, rs):  # rectangles x0, y0, x1, y1
    for r in rs: c.add(gdstk.rectangle(r[:2], r[2:], *l))
def A(c, l, x, y, w, h, nx, ny, dx, dy):  # array of equal rectangles
    R(c, l, [(x+i*dx, y+j*dy, x+i*dx+w, y+j*dy+h) for i in range(nx) for j in range(ny)])
def P(c, l, *ps):  # polygons
    for p in ps: c.add(gdstk.Polygon(p, *l))
boundary = (0, 0)
nwell = (21, 0)
comp = (22, 0)
poly2 = (30, 0)
pplus = (31, 0)
nplus = (32, 0)
contact = (33, 0)
metal1 = (34, 0)
dualgate = (55, 0)
v5_xtor = (112, 1)
lvpwell = (204, 0)

gf180mcu_fd_sc_mcu9t5v0_ = lib.new_cell('gf180mcu_fd_sc_mcu9t5v0__nor2_2')
R(gf180mcu_fd_sc_mcu9t5v0_, boundary, [(0,0,5.6,5.04)])
R(gf180mcu_fd_sc_mcu9t5v0_, nwell, [(-0.43,2.265,6.03,5.47)])
R(gf180mcu_fd_sc_mcu9t5v0_, comp, [(0.18,0.58,5.02,1.5), (0.23,2.865,4.97,4.695)])
P(gf180mcu_fd_sc_mcu9t5v0_, poly2, [(0.62,0.36),(0.62,1.72),(0.67,1.72),(0.67,4.915),(1.17,4.915),(1.17,1.72),(1.22,1.72),(1.22,0.36)],
  [(1.74,0.36),(1.74,1.72),(1.79,1.72),(1.79,4.915),(2.29,4.915),(2.29,2.565),(2.86,2.565),(2.86,4.915),(3.36,4.915),(3.36,1.72),(3.46,1.72),(3.46,0.36),(2.86,0.36),(2.86,2.205),(2.34,2.205),(2.34,0.36)],
  [(3.98,0.36),(3.98,2.205),(3.6,2.205),(3.6,2.565),(4.03,2.565),(4.03,4.915),(4.53,4.915),(4.53,1.72),(4.58,1.72),(4.58,0.36)])
R(gf180mcu_fd_sc_mcu9t5v0_, pplus, [(-0.2,2.265,5.8,5.24)])
R(gf180mcu_fd_sc_mcu9t5v0_, nplus, [(-0.2,-0.2,5.8,2.265)])
A(gf180mcu_fd_sc_mcu9t5v0_, contact, 0.25, 0.65, 0.22, 0.22, 3, 1, 2.24, 0)
A(gf180mcu_fd_sc_mcu9t5v0_, contact, 0.3, 3.61, 0.22, 0.22, 3, 2, 2.19, 0.47)
R(gf180mcu_fd_sc_mcu9t5v0_, contact, [(1.37,0.74,1.59,0.96), (3.61,0.74,3.83,0.96), (0.25,1.12,0.47,1.34), (4.73,1.12,4.95,1.34), (1.37,1.21,1.59,1.43), (3.61,1.21,3.83,1.43), (0.88,2.275,1.1,2.495), (1.86,2.275,2.08,2.495), (3.67,2.275,3.89,2.495)])
R(gf180mcu_fd_sc_mcu9t5v0_, metal1, [(1.8,2.27,2.14,2.71)])
P(gf180mcu_fd_sc_mcu9t5v0_, metal1, [(3.51,1.77),(3.51,2.94),(1.105,2.94),(1.105,2.215),(0.875,2.215),(0.875,3.17),(3.95,3.17),(3.95,2.27),(3.77,2.27),(3.77,1.77)],
  [(1.365,0.68),(1.365,1.49),(4.07,1.49),(4.07,1.72),(4.18,1.72),(4.18,3.55),(2.485,3.55),(2.485,4.36),(2.715,4.36),(2.715,3.78),(4.41,3.78),(4.41,1.21),(3.835,1.21),(3.835,0.68),(3.605,0.68),(3.605,1.16),(1.595,1.16),(1.595,0.68)],
  [(0,-0.45),(0,0.45),(0.245,0.45),(0.245,1.4),(0.475,1.4),(0.475,0.45),(2.485,0.45),(2.485,0.93),(2.715,0.93),(2.715,0.45),(4.725,0.45),(4.725,1.4),(4.955,1.4),(4.955,0.45),(5.6,0.45),(5.6,-0.45)],
  [(0.295,3.55),(0.295,4.59),(0,4.59),(0,5.49),(5.6,5.49),(5.6,4.59),(4.905,4.59),(4.905,3.55),(4.675,3.55),(4.675,4.59),(0.525,4.59),(0.525,3.55)])
R(gf180mcu_fd_sc_mcu9t5v0_, dualgate, [(-0.28,-0.28,5.88,5.32)])
R(gf180mcu_fd_sc_mcu9t5v0_, v5_xtor, [(0,0,5.6,5.04)])
R(gf180mcu_fd_sc_mcu9t5v0_, lvpwell, [(-0.43,-0.43,6.03,2.265)])
gf180mcu_fd_sc_mcu9t5v0_.add(gdstk.Label('A1', (1.96,2.52), layer=34, texttype=10))
gf180mcu_fd_sc_mcu9t5v0_.add(gdstk.Label('A2', (3.64,2.52), layer=34, texttype=10))
gf180mcu_fd_sc_mcu9t5v0_.add(gdstk.Label('VDD', (2.8,5.49), layer=34, texttype=10))
gf180mcu_fd_sc_mcu9t5v0_.add(gdstk.Label('VSS', (2.8,-0.45), layer=34, texttype=10))
gf180mcu_fd_sc_mcu9t5v0_.add(gdstk.Label('ZN', (4.2,1.4), layer=34, texttype=10))
gf180mcu_fd_sc_mcu9t5v0_.add(gdstk.Label('& Vendor GLOBALFOUNDRIES', (0,2), layer=63, texttype=63))
gf180mcu_fd_sc_mcu9t5v0_.add(gdstk.Label('& Product GF018hv5v_green_sc9', (0,1.5), layer=63, texttype=63))
gf180mcu_fd_sc_mcu9t5v0_.add(gdstk.Label('& Version 2015q2v2', (0,1), layer=63, texttype=63))
gf180mcu_fd_sc_mcu9t5v0_.add(gdstk.Label('& Metric 1.00', (0,0.5), layer=63, texttype=63))
gf180mcu_fd_sc_mcu9t5v0_.add(gdstk.Label('VNW', (0.345,3.92), layer=21, texttype=10))
gf180mcu_fd_sc_mcu9t5v0_.add(gdstk.Label('VPW', (0.34,-0.085), layer=204, texttype=10))

lib.write_gds('gf180mcu_fd_sc_mcu9t5v0__nor2_2.gds')
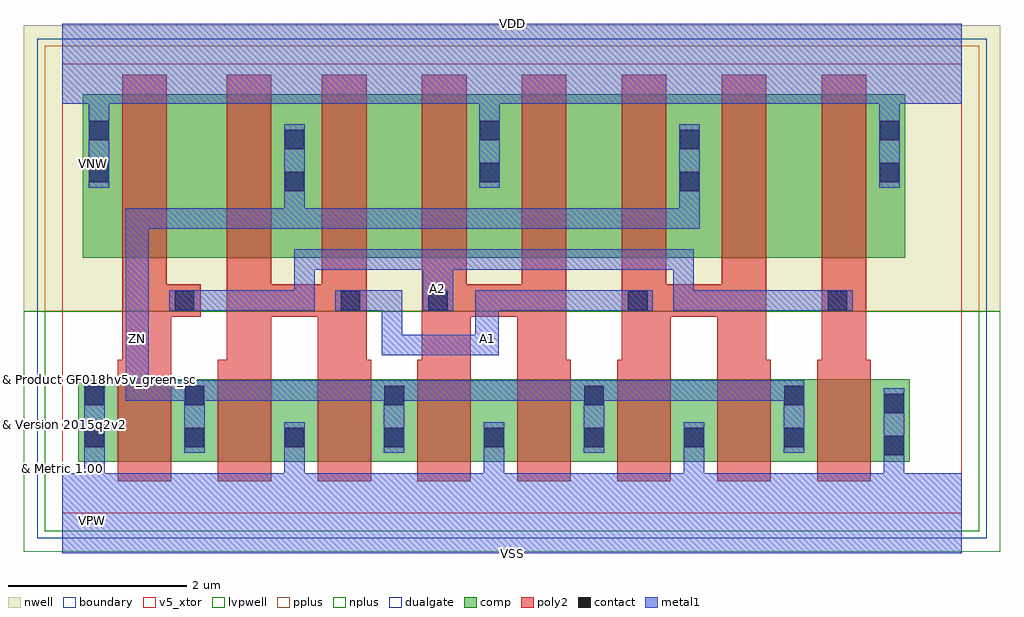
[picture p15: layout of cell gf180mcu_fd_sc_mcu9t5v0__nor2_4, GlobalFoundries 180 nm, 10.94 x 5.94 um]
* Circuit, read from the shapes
.subckt gf180mcu_fd_sc_mcu9t5v0__nor2_4 A1 A2 VDD VNW VSS ZN
XM1 ZN A2 VSS VSUBS nfet_05v0 w=0.92u l=0.6u m=4
XM2 VSS A1 ZN VSUBS nfet_05v0 w=0.92u l=0.6u m=4
XM3 n1 A2 VDD VNW pfet_05v0 w=1.83u l=0.5u
XM4 ZN A1 n1 VNW pfet_05v0 w=1.83u l=0.5u
XM5 n2 A1 ZN VNW pfet_05v0 w=1.83u l=0.5u
XM6 VDD A2 n2 VNW pfet_05v0 w=1.83u l=0.5u
XM7 n3 A2 VDD VNW pfet_05v0 w=1.83u l=0.5u
XM8 ZN A1 n3 VNW pfet_05v0 w=1.83u l=0.5u
XM9 n4 A1 ZN VNW pfet_05v0 w=1.83u l=0.5u
XM10 VDD A2 n4 VNW pfet_05v0 w=1.83u l=0.5u
.ends

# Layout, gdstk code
import gdstk
lib = gdstk.Library(unit=1e-6, precision=1e-09)
def R(c, l, rs):  # rectangles x0, y0, x1, y1
    for r in rs: c.add(gdstk.rectangle(r[:2], r[2:], *l))
def A(c, l, x, y, w, h, nx, ny, dx, dy):  # array of equal rectangles
    R(c, l, [(x+i*dx, y+j*dy, x+i*dx+w, y+j*dy+h) for i in range(nx) for j in range(ny)])
def P(c, l, *ps):  # polygons
    for p in ps: c.add(gdstk.Polygon(p, *l))
boundary = (0, 0)
nwell = (21, 0)
comp = (22, 0)
poly2 = (30, 0)
pplus = (31, 0)
nplus = (32, 0)
contact = (33, 0)
metal1 = (34, 0)
dualgate = (55, 0)
v5_xtor = (112, 1)
lvpwell = (204, 0)

gf180mcu_fd_sc_mcu9t5v0_ = lib.new_cell('gf180mcu_fd_sc_mcu9t5v0__nor2_4')
R(gf180mcu_fd_sc_mcu9t5v0_, boundary, [(0,0,10.08,5.04)])
R(gf180mcu_fd_sc_mcu9t5v0_, nwell, [(-0.43,2.265,10.51,5.47)])
R(gf180mcu_fd_sc_mcu9t5v0_, comp, [(0.18,0.58,9.5,1.5), (0.23,2.865,9.45,4.695)])
P(gf180mcu_fd_sc_mcu9t5v0_, poly2, [(0.62,0.36),(0.62,1.72),(0.67,1.72),(0.67,4.915),(1.17,4.915),(1.17,2.565),(1.55,2.565),(1.55,2.205),(1.22,2.205),(1.22,0.36)],
  [(1.74,0.36),(1.74,1.72),(1.84,1.72),(1.84,4.915),(2.34,4.915),(2.34,2.565),(2.91,2.565),(2.91,4.915),(3.41,4.915),(3.41,1.72),(3.46,1.72),(3.46,0.36),(2.86,0.36),(2.86,2.205),(2.34,2.205),(2.34,0.36)],
  [(3.98,0.36),(3.98,1.72),(4.03,1.72),(4.03,4.915),(4.53,4.915),(4.53,2.565),(5.15,2.565),(5.15,4.915),(5.65,4.915),(5.65,1.72),(5.7,1.72),(5.7,0.36),(5.1,0.36),(5.1,2.205),(4.58,2.205),(4.58,0.36)],
  [(6.22,0.36),(6.22,1.72),(6.27,1.72),(6.27,4.915),(6.77,4.915),(6.77,2.565),(7.39,2.565),(7.39,4.915),(7.89,4.915),(7.89,1.72),(7.94,1.72),(7.94,0.36),(7.34,0.36),(7.34,2.205),(6.82,2.205),(6.82,0.36)],
  [(8.46,0.36),(8.46,1.72),(8.51,1.72),(8.51,4.915),(9.01,4.915),(9.01,1.72),(9.06,1.72),(9.06,0.36)])
R(gf180mcu_fd_sc_mcu9t5v0_, pplus, [(-0.2,2.265,10.28,5.24)])
R(gf180mcu_fd_sc_mcu9t5v0_, nplus, [(-0.2,-0.2,10.28,2.265)])
A(gf180mcu_fd_sc_mcu9t5v0_, contact, 0.25, 0.74, 0.22, 0.22, 8, 1, 1.12, 0)
A(gf180mcu_fd_sc_mcu9t5v0_, contact, 1.37, 1.21, 0.22, 0.22, 4, 1, 2.24, 0)
A(gf180mcu_fd_sc_mcu9t5v0_, contact, 4.1, 2.275, 0.22, 0.22, 3, 1, 2.24, 0)
R(gf180mcu_fd_sc_mcu9t5v0_, contact, [(9.21,0.65,9.43,0.87), (9.21,1.12,9.43,1.34), (0.25,1.21,0.47,1.43), (1.26,2.275,1.48,2.495), (3.12,2.275,3.34,2.495), (2.49,3.61,2.71,3.83), (6.92,3.61,7.14,3.83), (0.3,3.71,0.52,3.93), (4.68,3.71,4.9,3.93), (9.16,3.71,9.38,3.93), (2.49,4.08,2.71,4.3), (6.92,4.08,7.14,4.3), (0.3,4.18,0.52,4.4), (4.68,4.18,4.9,4.4), (9.16,4.18,9.38,4.4)])
P(gf180mcu_fd_sc_mcu9t5v0_, metal1, [(3.58,1.77),(3.58,2.27),(3.06,2.27),(3.06,2.5),(3.81,2.5),(3.81,2),(4.63,2),(4.63,2.5),(6.62,2.5),(6.62,2.27),(4.89,2.27),(4.89,1.77)],
  [(1.365,0.68),(1.365,1.26),(0.71,1.26),(0.71,3.42),(2.485,3.42),(2.485,4.36),(2.715,4.36),(2.715,3.42),(6.915,3.42),(6.915,4.36),(7.145,4.36),(7.145,3.19),(0.97,3.19),(0.97,1.49),(8.315,1.49),(8.315,0.68),(8.085,0.68),(8.085,1.26),(6.075,1.26),(6.075,0.68),(5.845,0.68),(5.845,1.26),(3.835,1.26),(3.835,0.68),(3.605,0.68),(3.605,1.26),(1.595,1.26),(1.595,0.68)],
  [(1.2,2.27),(1.2,2.5),(2.6,2.5),(2.6,2.96),(7.08,2.96),(7.08,2.5),(8.86,2.5),(8.86,2.27),(6.85,2.27),(6.85,2.73),(4.38,2.73),(4.38,2.27),(4.04,2.27),(4.04,2.73),(2.83,2.73),(2.83,2.27)],
  [(0,-0.45),(0,0.45),(0.245,0.45),(0.245,1.49),(0.475,1.49),(0.475,0.45),(2.485,0.45),(2.485,1.02),(2.715,1.02),(2.715,0.45),(4.725,0.45),(4.725,1.02),(4.955,1.02),(4.955,0.45),(6.965,0.45),(6.965,1.02),(7.195,1.02),(7.195,0.45),(9.205,0.45),(9.205,1.4),(9.435,1.4),(9.435,0.45),(10.08,0.45),(10.08,-0.45)],
  [(0.295,3.65),(0.295,4.59),(0,4.59),(0,5.49),(10.08,5.49),(10.08,4.59),(9.385,4.59),(9.385,3.65),(9.155,3.65),(9.155,4.59),(4.905,4.59),(4.905,3.65),(4.675,3.65),(4.675,4.59),(0.525,4.59),(0.525,3.65)])
R(gf180mcu_fd_sc_mcu9t5v0_, dualgate, [(-0.28,-0.28,10.36,5.32)])
R(gf180mcu_fd_sc_mcu9t5v0_, v5_xtor, [(0,0,10.08,5.04)])
R(gf180mcu_fd_sc_mcu9t5v0_, lvpwell, [(-0.43,-0.43,10.51,2.265)])
gf180mcu_fd_sc_mcu9t5v0_.add(gdstk.Label('A1', (4.76,1.96), layer=34, texttype=10))
gf180mcu_fd_sc_mcu9t5v0_.add(gdstk.Label('A2', (4.2,2.52), layer=34, texttype=10))
gf180mcu_fd_sc_mcu9t5v0_.add(gdstk.Label('VDD', (5.04,5.49), layer=34, texttype=10))
gf180mcu_fd_sc_mcu9t5v0_.add(gdstk.Label('VSS', (5.04,-0.45), layer=34, texttype=10))
gf180mcu_fd_sc_mcu9t5v0_.add(gdstk.Label('ZN', (0.84,1.96), layer=34, texttype=10))
gf180mcu_fd_sc_mcu9t5v0_.add(gdstk.Label('& Vendor GLOBALFOUNDRIES', (0,2), layer=63, texttype=63))
gf180mcu_fd_sc_mcu9t5v0_.add(gdstk.Label('& Product GF018hv5v_green_sc9', (0,1.5), layer=63, texttype=63))
gf180mcu_fd_sc_mcu9t5v0_.add(gdstk.Label('& Version 2015q2v2', (0,1), layer=63, texttype=63))
gf180mcu_fd_sc_mcu9t5v0_.add(gdstk.Label('& Metric 1.00', (0,0.5), layer=63, texttype=63))
gf180mcu_fd_sc_mcu9t5v0_.add(gdstk.Label('VNW', (0.345,3.92), layer=21, texttype=10))
gf180mcu_fd_sc_mcu9t5v0_.add(gdstk.Label('VPW', (0.34,-0.085), layer=204, texttype=10))

lib.write_gds('gf180mcu_fd_sc_mcu9t5v0__nor2_4.gds')
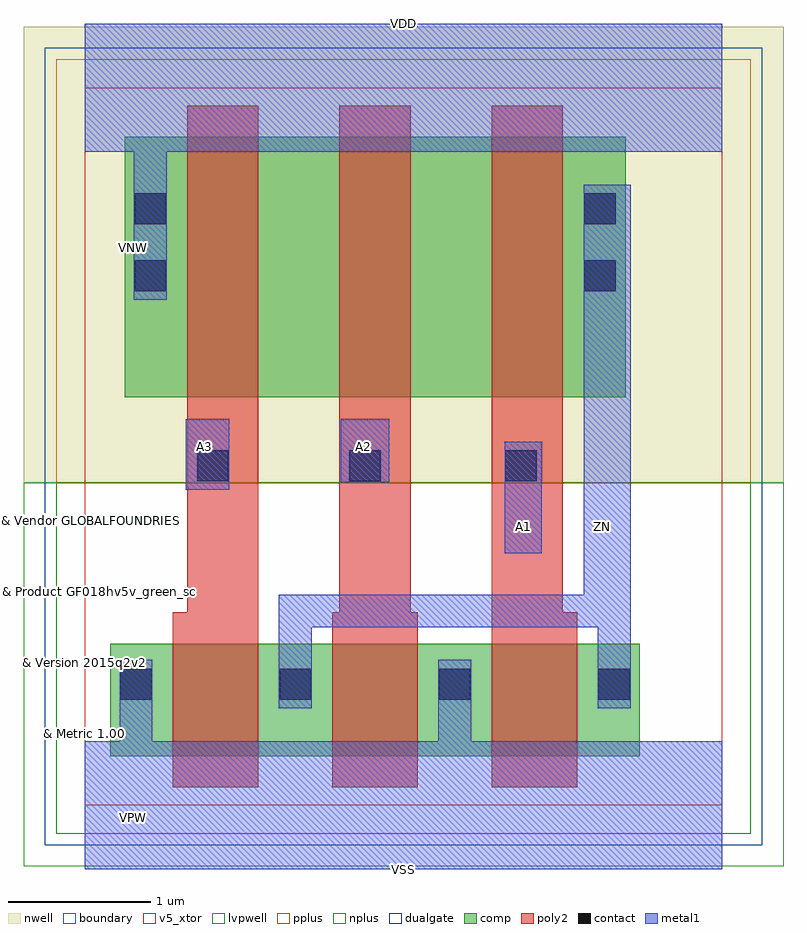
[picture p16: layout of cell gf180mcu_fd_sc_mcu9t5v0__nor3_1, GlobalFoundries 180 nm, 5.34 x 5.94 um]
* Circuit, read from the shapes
.subckt gf180mcu_fd_sc_mcu9t5v0__nor3_1 A1 A2 A3 VDD VNW VSS ZN
XM1 ZN A3 VSS VSUBS nfet_05v0 w=0.79u l=0.6u
XM2 VSS A2 ZN VSUBS nfet_05v0 w=0.79u l=0.6u
XM3 ZN A1 VSS VSUBS nfet_05v0 w=0.79u l=0.6u
XM4 n1 A3 VDD VNW pfet_05v0 w=1.83u l=0.5u
XM5 n2 A2 n1 VNW pfet_05v0 w=1.83u l=0.5u
XM6 ZN A1 n2 VNW pfet_05v0 w=1.83u l=0.5u
.ends

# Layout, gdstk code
import gdstk
lib = gdstk.Library(unit=1e-6, precision=1e-09)
def R(c, l, rs):  # rectangles x0, y0, x1, y1
    for r in rs: c.add(gdstk.rectangle(r[:2], r[2:], *l))
def A(c, l, x, y, w, h, nx, ny, dx, dy):  # array of equal rectangles
    R(c, l, [(x+i*dx, y+j*dy, x+i*dx+w, y+j*dy+h) for i in range(nx) for j in range(ny)])
def P(c, l, *ps):  # polygons
    for p in ps: c.add(gdstk.Polygon(p, *l))
boundary = (0, 0)
nwell = (21, 0)
comp = (22, 0)
poly2 = (30, 0)
pplus = (31, 0)
nplus = (32, 0)
contact = (33, 0)
metal1 = (34, 0)
dualgate = (55, 0)
v5_xtor = (112, 1)
lvpwell = (204, 0)

gf180mcu_fd_sc_mcu9t5v0_ = lib.new_cell('gf180mcu_fd_sc_mcu9t5v0__nor3_1')
R(gf180mcu_fd_sc_mcu9t5v0_, boundary, [(0,0,4.48,5.04)])
R(gf180mcu_fd_sc_mcu9t5v0_, nwell, [(-0.43,2.265,4.91,5.47)])
R(gf180mcu_fd_sc_mcu9t5v0_, comp, [(0.18,0.345,3.9,1.135), (0.28,2.865,3.8,4.695)])
P(gf180mcu_fd_sc_mcu9t5v0_, poly2, [(0.62,0.125),(0.62,1.355),(0.72,1.355),(0.72,4.915),(1.22,4.915),(1.22,0.125)],
  [(1.74,0.125),(1.74,1.355),(1.79,1.355),(1.79,4.915),(2.29,4.915),(2.29,1.355),(2.34,1.355),(2.34,0.125)],
  [(2.86,0.125),(2.86,4.915),(3.36,4.915),(3.36,1.355),(3.46,1.355),(3.46,0.125)])
R(gf180mcu_fd_sc_mcu9t5v0_, pplus, [(-0.2,2.265,4.68,5.24)])
R(gf180mcu_fd_sc_mcu9t5v0_, nplus, [(-0.2,-0.2,4.68,2.265)])
A(gf180mcu_fd_sc_mcu9t5v0_, contact, 0.25, 0.74, 0.22, 0.22, 4, 1, 1.12, 0)
R(gf180mcu_fd_sc_mcu9t5v0_, contact, [(0.79,2.275,1.01,2.495), (1.86,2.275,2.08,2.495), (2.955,2.275,3.175,2.495), (0.35,3.61,0.57,3.83), (3.51,3.61,3.73,3.83), (0.35,4.08,0.57,4.3), (3.51,4.08,3.73,4.3)])
R(gf180mcu_fd_sc_mcu9t5v0_, metal1, [(2.95,1.77,3.21,2.555), (0.71,2.215,1.015,2.71), (1.8,2.27,2.14,2.71)])
P(gf180mcu_fd_sc_mcu9t5v0_, metal1, [(1.365,0.68),(1.365,1.48),(3.505,1.48),(3.505,4.36),(3.835,4.36),(3.835,0.68),(3.605,0.68),(3.605,1.25),(1.595,1.25),(1.595,0.68)],
  [(0,-0.45),(0,0.45),(0.245,0.45),(0.245,1.02),(0.475,1.02),(0.475,0.45),(2.485,0.45),(2.485,1.02),(2.715,1.02),(2.715,0.45),(4.48,0.45),(4.48,-0.45)],
  [(0.345,3.55),(0.345,4.59),(0,4.59),(0,5.49),(4.48,5.49),(4.48,4.59),(0.575,4.59),(0.575,3.55)])
R(gf180mcu_fd_sc_mcu9t5v0_, dualgate, [(-0.28,-0.28,4.76,5.32)])
R(gf180mcu_fd_sc_mcu9t5v0_, v5_xtor, [(0,0,4.48,5.04)])
R(gf180mcu_fd_sc_mcu9t5v0_, lvpwell, [(-0.43,-0.43,4.91,2.265)])
gf180mcu_fd_sc_mcu9t5v0_.add(gdstk.Label('A1', (3.08,1.96), layer=34, texttype=10))
gf180mcu_fd_sc_mcu9t5v0_.add(gdstk.Label('A2', (1.96,2.52), layer=34, texttype=10))
gf180mcu_fd_sc_mcu9t5v0_.add(gdstk.Label('A3', (0.84,2.52), layer=34, texttype=10))
gf180mcu_fd_sc_mcu9t5v0_.add(gdstk.Label('VDD', (2.24,5.49), layer=34, texttype=10))
gf180mcu_fd_sc_mcu9t5v0_.add(gdstk.Label('VSS', (2.24,-0.45), layer=34, texttype=10))
gf180mcu_fd_sc_mcu9t5v0_.add(gdstk.Label('ZN', (3.64,1.96), layer=34, texttype=10))
gf180mcu_fd_sc_mcu9t5v0_.add(gdstk.Label('& Vendor GLOBALFOUNDRIES', (0,2), layer=63, texttype=63))
gf180mcu_fd_sc_mcu9t5v0_.add(gdstk.Label('& Product GF018hv5v_green_sc9', (0,1.5), layer=63, texttype=63))
gf180mcu_fd_sc_mcu9t5v0_.add(gdstk.Label('& Version 2015q2v2', (0,1), layer=63, texttype=63))
gf180mcu_fd_sc_mcu9t5v0_.add(gdstk.Label('& Metric 1.00', (0,0.5), layer=63, texttype=63))
gf180mcu_fd_sc_mcu9t5v0_.add(gdstk.Label('VNW', (0.345,3.92), layer=21, texttype=10))
gf180mcu_fd_sc_mcu9t5v0_.add(gdstk.Label('VPW', (0.34,-0.085), layer=204, texttype=10))

lib.write_gds('gf180mcu_fd_sc_mcu9t5v0__nor3_1.gds')
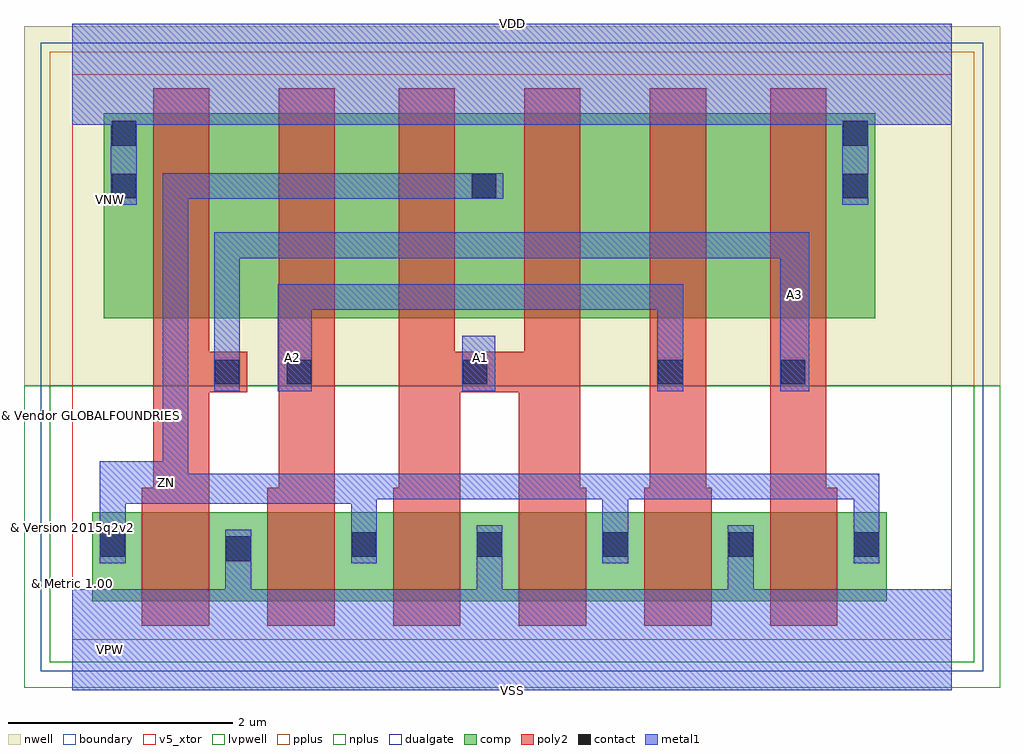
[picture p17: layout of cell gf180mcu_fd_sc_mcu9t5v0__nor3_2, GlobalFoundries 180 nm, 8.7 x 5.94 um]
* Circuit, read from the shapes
.subckt gf180mcu_fd_sc_mcu9t5v0__nor3_2 A1 A2 A3 VDD VNW VSS ZN
XM1 VSS A3 ZN VSUBS nfet_05v0 w=0.79u l=0.6u m=2
XM2 ZN A2 VSS VSUBS nfet_05v0 w=0.79u l=0.6u m=2
XM3 VSS A1 ZN VSUBS nfet_05v0 w=0.79u l=0.6u m=2
XM4 n1 A3 VDD VNW pfet_05v0 w=1.83u l=0.5u
XM5 n2 A2 n1 VNW pfet_05v0 w=1.83u l=0.5u
XM6 ZN A1 n2 VNW pfet_05v0 w=1.83u l=0.5u
XM7 n3 A1 ZN VNW pfet_05v0 w=1.83u l=0.5u
XM8 n4 A2 n3 VNW pfet_05v0 w=1.83u l=0.5u
XM9 VDD A3 n4 VNW pfet_05v0 w=1.83u l=0.5u
.ends

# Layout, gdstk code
import gdstk
lib = gdstk.Library(unit=1e-6, precision=1e-09)
def R(c, l, rs):  # rectangles x0, y0, x1, y1
    for r in rs: c.add(gdstk.rectangle(r[:2], r[2:], *l))
def A(c, l, x, y, w, h, nx, ny, dx, dy):  # array of equal rectangles
    R(c, l, [(x+i*dx, y+j*dy, x+i*dx+w, y+j*dy+h) for i in range(nx) for j in range(ny)])
def P(c, l, *ps):  # polygons
    for p in ps: c.add(gdstk.Polygon(p, *l))
boundary = (0, 0)
nwell = (21, 0)
comp = (22, 0)
poly2 = (30, 0)
pplus = (31, 0)
nplus = (32, 0)
contact = (33, 0)
metal1 = (34, 0)
dualgate = (55, 0)
v5_xtor = (112, 1)
lvpwell = (204, 0)

gf180mcu_fd_sc_mcu9t5v0_ = lib.new_cell('gf180mcu_fd_sc_mcu9t5v0__nor3_2')
R(gf180mcu_fd_sc_mcu9t5v0_, boundary, [(0,0,7.84,5.04)])
R(gf180mcu_fd_sc_mcu9t5v0_, nwell, [(-0.43,2.265,8.27,5.47)])
R(gf180mcu_fd_sc_mcu9t5v0_, comp, [(0.18,0.345,7.26,1.135), (0.28,2.865,7.16,4.695)])
P(gf180mcu_fd_sc_mcu9t5v0_, poly2, [(0.62,0.125),(0.62,1.355),(0.72,1.355),(0.72,4.915),(1.22,4.915),(1.22,2.565),(1.56,2.565),(1.56,2.205),(1.22,2.205),(1.22,0.125)],
  [(1.74,0.125),(1.74,1.355),(1.84,1.355),(1.84,4.915),(2.34,4.915),(2.34,0.125)],
  [(2.86,0.125),(2.86,1.355),(2.91,1.355),(2.91,4.915),(3.41,4.915),(3.41,2.565),(4.03,2.565),(4.03,4.915),(4.53,4.915),(4.53,1.355),(4.58,1.355),(4.58,0.125),(3.98,0.125),(3.98,2.205),(3.46,2.205),(3.46,0.125)],
  [(5.1,0.125),(5.1,1.355),(5.15,1.355),(5.15,4.915),(5.65,4.915),(5.65,1.355),(5.7,1.355),(5.7,0.125)],
  [(6.22,0.125),(6.22,4.915),(6.72,4.915),(6.72,1.355),(6.82,1.355),(6.82,0.125)])
R(gf180mcu_fd_sc_mcu9t5v0_, pplus, [(-0.2,2.265,8.04,5.24)])
R(gf180mcu_fd_sc_mcu9t5v0_, nplus, [(-0.2,-0.2,8.04,2.265)])
A(gf180mcu_fd_sc_mcu9t5v0_, contact, 2.49, 0.74, 0.22, 0.22, 5, 1, 1.12, 0)
R(gf180mcu_fd_sc_mcu9t5v0_, contact, [(1.37,0.7,1.59,0.92), (0.25,0.74,0.47,0.96), (1.27,2.275,1.49,2.495), (1.91,2.275,2.13,2.495), (3.48,2.275,3.7,2.495), (5.22,2.275,5.44,2.495), (6.315,2.275,6.535,2.495), (0.35,3.935,0.57,4.155), (3.56,3.935,3.78,4.155), (6.87,3.935,7.09,4.155), (0.35,4.405,0.57,4.625), (6.87,4.405,7.09,4.625)])
R(gf180mcu_fd_sc_mcu9t5v0_, metal1, [(3.475,2.215,3.77,2.71)])
P(gf180mcu_fd_sc_mcu9t5v0_, metal1, [(1.83,2.215),(1.83,3.17),(5.445,3.17),(5.445,2.215),(5.215,2.215),(5.215,2.94),(2.135,2.94),(2.135,2.215)],
  [(1.265,2.215),(1.265,3.63),(6.57,3.63),(6.57,2.215),(6.31,2.215),(6.31,3.4),(1.495,3.4),(1.495,2.215)],
  [(0.245,0.68),(0.245,1.59),(0.805,1.59),(0.805,4.16),(3.84,4.16),(3.84,3.93),(1.035,3.93),(1.035,1.48),(7.195,1.48),(7.195,0.68),(6.965,0.68),(6.965,1.25),(4.955,1.25),(4.955,0.68),(4.725,0.68),(4.725,1.25),(2.715,1.25),(2.715,0.68),(2.485,0.68),(2.485,1.21),(0.475,1.21),(0.475,0.68)],
  [(0,-0.45),(0,0.45),(1.365,0.45),(1.365,0.98),(1.595,0.98),(1.595,0.45),(3.605,0.45),(3.605,1.02),(3.835,1.02),(3.835,0.45),(5.845,0.45),(5.845,1.02),(6.075,1.02),(6.075,0.45),(7.84,0.45),(7.84,-0.45)],
  [(0.345,3.875),(0.345,4.59),(0,4.59),(0,5.49),(7.84,5.49),(7.84,4.59),(7.095,4.59),(7.095,3.875),(6.865,3.875),(6.865,4.59),(0.575,4.59),(0.575,3.875)])
R(gf180mcu_fd_sc_mcu9t5v0_, dualgate, [(-0.28,-0.28,8.12,5.32)])
R(gf180mcu_fd_sc_mcu9t5v0_, v5_xtor, [(0,0,7.84,5.04)])
R(gf180mcu_fd_sc_mcu9t5v0_, lvpwell, [(-0.43,-0.43,8.27,2.265)])
gf180mcu_fd_sc_mcu9t5v0_.add(gdstk.Label('A1', (3.64,2.52), layer=34, texttype=10))
gf180mcu_fd_sc_mcu9t5v0_.add(gdstk.Label('A2', (1.96,2.52), layer=34, texttype=10))
gf180mcu_fd_sc_mcu9t5v0_.add(gdstk.Label('A3', (6.44,3.08), layer=34, texttype=10))
gf180mcu_fd_sc_mcu9t5v0_.add(gdstk.Label('VDD', (3.92,5.49), layer=34, texttype=10))
gf180mcu_fd_sc_mcu9t5v0_.add(gdstk.Label('VSS', (3.92,-0.45), layer=34, texttype=10))
gf180mcu_fd_sc_mcu9t5v0_.add(gdstk.Label('ZN', (0.84,1.4), layer=34, texttype=10))
gf180mcu_fd_sc_mcu9t5v0_.add(gdstk.Label('& Vendor GLOBALFOUNDRIES', (0,2), layer=63, texttype=63))
gf180mcu_fd_sc_mcu9t5v0_.add(gdstk.Label('& Product GF018hv5v_green_sc9', (0,1.5), layer=63, texttype=63))
gf180mcu_fd_sc_mcu9t5v0_.add(gdstk.Label('& Version 2015q2v2', (0,1), layer=63, texttype=63))
gf180mcu_fd_sc_mcu9t5v0_.add(gdstk.Label('& Metric 1.00', (0,0.5), layer=63, texttype=63))
gf180mcu_fd_sc_mcu9t5v0_.add(gdstk.Label('VNW', (0.345,3.92), layer=21, texttype=10))
gf180mcu_fd_sc_mcu9t5v0_.add(gdstk.Label('VPW', (0.34,-0.085), layer=204, texttype=10))

lib.write_gds('gf180mcu_fd_sc_mcu9t5v0__nor3_2.gds')
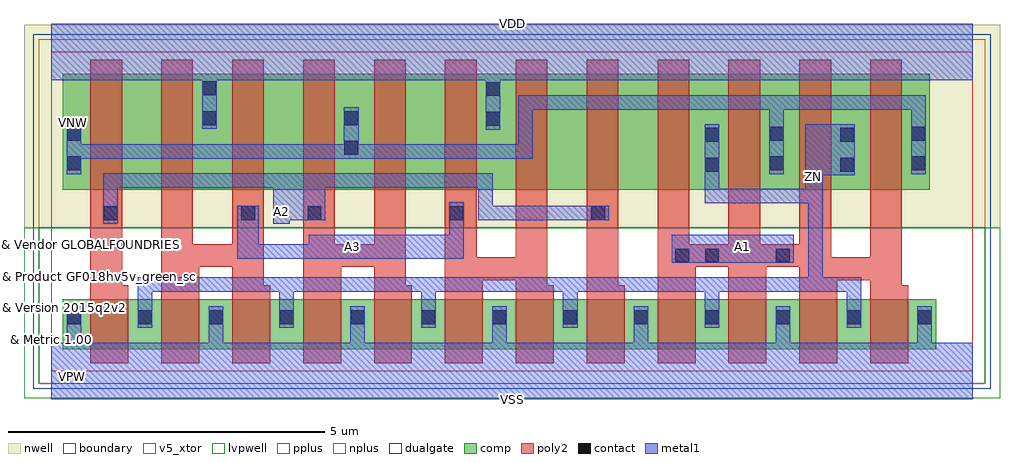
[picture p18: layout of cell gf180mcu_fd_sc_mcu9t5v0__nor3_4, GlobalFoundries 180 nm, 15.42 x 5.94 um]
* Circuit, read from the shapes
.subckt gf180mcu_fd_sc_mcu9t5v0__nor3_4 A1 A2 A3 VDD VNW VSS ZN
XM1 ZN A2 VSS VSUBS nfet_05v0 w=0.79u l=0.6u m=4
XM2 VSS A3 ZN VSUBS nfet_05v0 w=0.79u l=0.6u m=4
XM3 ZN A1 VSS VSUBS nfet_05v0 w=0.79u l=0.6u m=4
XM4 n1 A2 n2 VNW pfet_05v0 w=1.83u l=0.5u
XM5 VDD A3 n1 VNW pfet_05v0 w=1.83u l=0.5u
XM6 n3 A3 VDD VNW pfet_05v0 w=1.83u l=0.5u
XM7 n2 A2 n3 VNW pfet_05v0 w=1.83u l=0.5u
XM8 n4 A2 n2 VNW pfet_05v0 w=1.83u l=0.5u
XM9 VDD A3 n4 VNW pfet_05v0 w=1.83u l=0.5u
XM10 n5 A3 VDD VNW pfet_05v0 w=1.83u l=0.5u
XM11 n6 A2 n5 VNW pfet_05v0 w=1.83u l=0.5u
XM12 ZN A1 n6 VNW pfet_05v0 w=1.83u l=0.5u
XM13 n2 A1 ZN VNW pfet_05v0 w=1.83u l=0.5u m=3
.ends

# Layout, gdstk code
import gdstk
lib = gdstk.Library(unit=1e-6, precision=1e-09)
def R(c, l, rs):  # rectangles x0, y0, x1, y1
    for r in rs: c.add(gdstk.rectangle(r[:2], r[2:], *l))
def A(c, l, x, y, w, h, nx, ny, dx, dy):  # array of equal rectangles
    R(c, l, [(x+i*dx, y+j*dy, x+i*dx+w, y+j*dy+h) for i in range(nx) for j in range(ny)])
def P(c, l, *ps):  # polygons
    for p in ps: c.add(gdstk.Polygon(p, *l))
boundary = (0, 0)
nwell = (21, 0)
comp = (22, 0)
poly2 = (30, 0)
pplus = (31, 0)
nplus = (32, 0)
contact = (33, 0)
metal1 = (34, 0)
dualgate = (55, 0)
v5_xtor = (112, 1)
lvpwell = (204, 0)

gf180mcu_fd_sc_mcu9t5v0_ = lib.new_cell('gf180mcu_fd_sc_mcu9t5v0__nor3_4')
R(gf180mcu_fd_sc_mcu9t5v0_, boundary, [(0,0,14.56,5.04)])
R(gf180mcu_fd_sc_mcu9t5v0_, nwell, [(-0.43,2.265,14.99,5.47)])
R(gf180mcu_fd_sc_mcu9t5v0_, comp, [(0.18,0.345,13.98,1.135), (0.18,2.865,13.88,4.695)])
P(gf180mcu_fd_sc_mcu9t5v0_, poly2, [(0.62,0.125),(0.62,4.915),(1.12,4.915),(1.12,1.355),(1.22,1.355),(1.22,0.125)],
  [(1.74,0.125),(1.74,4.915),(2.24,4.915),(2.24,2.005),(2.86,2.005),(2.86,4.915),(3.36,4.915),(3.36,1.355),(3.46,1.355),(3.46,0.125),(2.86,0.125),(2.86,1.645),(2.34,1.645),(2.34,0.125)],
  [(3.98,0.125),(3.98,4.915),(4.48,4.915),(4.48,2.005),(5.1,2.005),(5.1,4.915),(5.6,4.915),(5.6,1.355),(5.7,1.355),(5.7,0.125),(5.1,0.125),(5.1,1.645),(4.58,1.645),(4.58,0.125)],
  [(6.22,0.125),(6.22,4.915),(6.72,4.915),(6.72,1.795),(7.34,1.795),(7.34,4.915),(7.84,4.915),(7.84,1.355),(7.94,1.355),(7.94,0.125),(7.34,0.125),(7.34,1.435),(6.82,1.435),(6.82,0.125)],
  [(8.46,0.125),(8.46,4.915),(8.96,4.915),(8.96,1.355),(9.06,1.355),(9.06,0.125)],
  [(9.58,0.125),(9.58,4.915),(10.08,4.915),(10.08,2.005),(10.7,2.005),(10.7,4.915),(11.2,4.915),(11.2,2.005),(11.82,2.005),(11.82,4.915),(12.32,4.915),(12.32,1.795),(12.94,1.795),(12.94,4.915),(13.44,4.915),(13.44,1.355),(13.54,1.355),(13.54,0.125),(12.94,0.125),(12.94,1.435),(12.42,1.435),(12.42,0.125),(11.82,0.125),(11.82,1.645),(11.3,1.645),(11.3,0.125),(10.7,0.125),(10.7,1.645),(10.18,1.645),(10.18,0.125)])
R(gf180mcu_fd_sc_mcu9t5v0_, pplus, [(-0.2,2.265,14.76,5.24)])
R(gf180mcu_fd_sc_mcu9t5v0_, nplus, [(-0.2,-0.2,14.76,2.265)])
A(gf180mcu_fd_sc_mcu9t5v0_, contact, 0.25, 0.74, 0.22, 0.22, 13, 1, 1.12, 0)
A(gf180mcu_fd_sc_mcu9t5v0_, contact, 4.05, 2.385, 0.22, 0.22, 3, 1, 2.24, 0)
R(gf180mcu_fd_sc_mcu9t5v0_, contact, [(9.86,1.715,10.08,1.935), (10.33,1.715,10.55,1.935), (11.45,1.715,11.67,1.935), (0.83,2.385,1.05,2.605), (3,2.385,3.22,2.605), (10.33,3.15,10.55,3.37), (12.47,3.15,12.69,3.37), (0.25,3.17,0.47,3.39), (11.35,3.17,11.57,3.39), (13.59,3.17,13.81,3.39), (4.63,3.415,4.85,3.635), (10.33,3.62,10.55,3.84), (12.47,3.62,12.69,3.84), (0.25,3.64,0.47,3.86), (11.35,3.64,11.57,3.86), (13.59,3.64,13.81,3.86), (6.87,3.875,7.09,4.095), (2.39,3.885,2.61,4.105), (4.63,3.885,4.85,4.105), (6.87,4.345,7.09,4.565), (2.39,4.355,2.61,4.575)])
R(gf180mcu_fd_sc_mcu9t5v0_, metal1, [(9.8,1.71,11.73,2.15)])
P(gf180mcu_fd_sc_mcu9t5v0_, metal1, [(2.94,1.77),(2.94,2.61),(3.28,2.61),(3.28,2),(4.07,2),(4.07,2.15),(6.285,2.15),(6.285,2.665),(6.515,2.665),(6.515,1.77)],
  [(0.825,2.325),(0.825,3.125),(6.975,3.125),(6.975,2.61),(8.81,2.61),(8.81,2.38),(6.745,2.38),(6.745,2.895),(4.33,2.895),(4.33,2.38),(3.77,2.38),(3.77,2.33),(3.51,2.33),(3.51,2.895),(1.055,2.895),(1.055,2.325)],
  [(1.365,0.68),(1.365,1.48),(11.96,1.48),(11.96,2.65),(10.325,2.65),(10.325,3.9),(10.555,3.9),(10.555,2.88),(11.91,2.88),(11.91,3.9),(12.695,3.9),(12.695,3.09),(12.19,3.09),(12.19,1.48),(12.795,1.48),(12.795,0.68),(12.565,0.68),(12.565,1.25),(10.555,1.25),(10.555,0.68),(10.325,0.68),(10.325,1.25),(8.315,1.25),(8.315,0.68),(8.085,0.68),(8.085,1.25),(6.075,1.25),(6.075,0.68),(5.845,0.68),(5.845,1.25),(3.835,1.25),(3.835,0.68),(3.605,0.68),(3.605,1.25),(1.595,1.25),(1.595,0.68)],
  [(0.245,3.11),(0.245,3.92),(0.475,3.92),(0.475,3.585),(4.625,3.585),(4.625,4.165),(4.855,4.165),(4.855,3.585),(7.375,3.585),(7.375,4.36),(13.815,4.36),(13.815,3.11),(13.585,3.11),(13.585,4.13),(11.575,4.13),(11.575,3.11),(11.345,3.11),(11.345,4.13),(7.605,4.13),(7.605,3.355),(0.475,3.355),(0.475,3.11)],
  [(0,-0.45),(0,0.45),(0.245,0.45),(0.245,1.02),(0.475,1.02),(0.475,0.45),(2.485,0.45),(2.485,1.02),(2.715,1.02),(2.715,0.45),(4.725,0.45),(4.725,1.02),(4.955,1.02),(4.955,0.45),(6.965,0.45),(6.965,1.02),(7.195,1.02),(7.195,0.45),(9.205,0.45),(9.205,1.02),(9.435,1.02),(9.435,0.45),(11.445,0.45),(11.445,1.02),(11.675,1.02),(11.675,0.45),(13.685,0.45),(13.685,1.02),(13.915,1.02),(13.915,0.45),(14.56,0.45),(14.56,-0.45)],
  [(6.865,3.815),(6.865,4.59),(2.615,4.59),(2.615,3.825),(2.385,3.825),(2.385,4.59),(0,4.59),(0,5.49),(14.56,5.49),(14.56,4.59),(7.095,4.59),(7.095,3.815)])
R(gf180mcu_fd_sc_mcu9t5v0_, dualgate, [(-0.28,-0.28,14.84,5.32)])
R(gf180mcu_fd_sc_mcu9t5v0_, v5_xtor, [(0,0,14.56,5.04)])
R(gf180mcu_fd_sc_mcu9t5v0_, lvpwell, [(-0.43,-0.43,14.99,2.265)])
gf180mcu_fd_sc_mcu9t5v0_.add(gdstk.Label('A1', (10.92,1.96), layer=34, texttype=10))
gf180mcu_fd_sc_mcu9t5v0_.add(gdstk.Label('A2', (3.64,2.52), layer=34, texttype=10))
gf180mcu_fd_sc_mcu9t5v0_.add(gdstk.Label('A3', (4.76,1.96), layer=34, texttype=10))
gf180mcu_fd_sc_mcu9t5v0_.add(gdstk.Label('VDD', (7.28,5.49), layer=34, texttype=10))
gf180mcu_fd_sc_mcu9t5v0_.add(gdstk.Label('VSS', (7.28,-0.45), layer=34, texttype=10))
gf180mcu_fd_sc_mcu9t5v0_.add(gdstk.Label('ZN', (12.04,3.08), layer=34, texttype=10))
gf180mcu_fd_sc_mcu9t5v0_.add(gdstk.Label('& Vendor GLOBALFOUNDRIES', (0,2), layer=63, texttype=63))
gf180mcu_fd_sc_mcu9t5v0_.add(gdstk.Label('& Product GF018hv5v_green_sc9', (0,1.5), layer=63, texttype=63))
gf180mcu_fd_sc_mcu9t5v0_.add(gdstk.Label('& Version 2015q2v2', (0,1), layer=63, texttype=63))
gf180mcu_fd_sc_mcu9t5v0_.add(gdstk.Label('& Metric 1.00', (0,0.5), layer=63, texttype=63))
gf180mcu_fd_sc_mcu9t5v0_.add(gdstk.Label('VNW', (0.345,3.92), layer=21, texttype=10))
gf180mcu_fd_sc_mcu9t5v0_.add(gdstk.Label('VPW', (0.34,-0.085), layer=204, texttype=10))

lib.write_gds('gf180mcu_fd_sc_mcu9t5v0__nor3_4.gds')
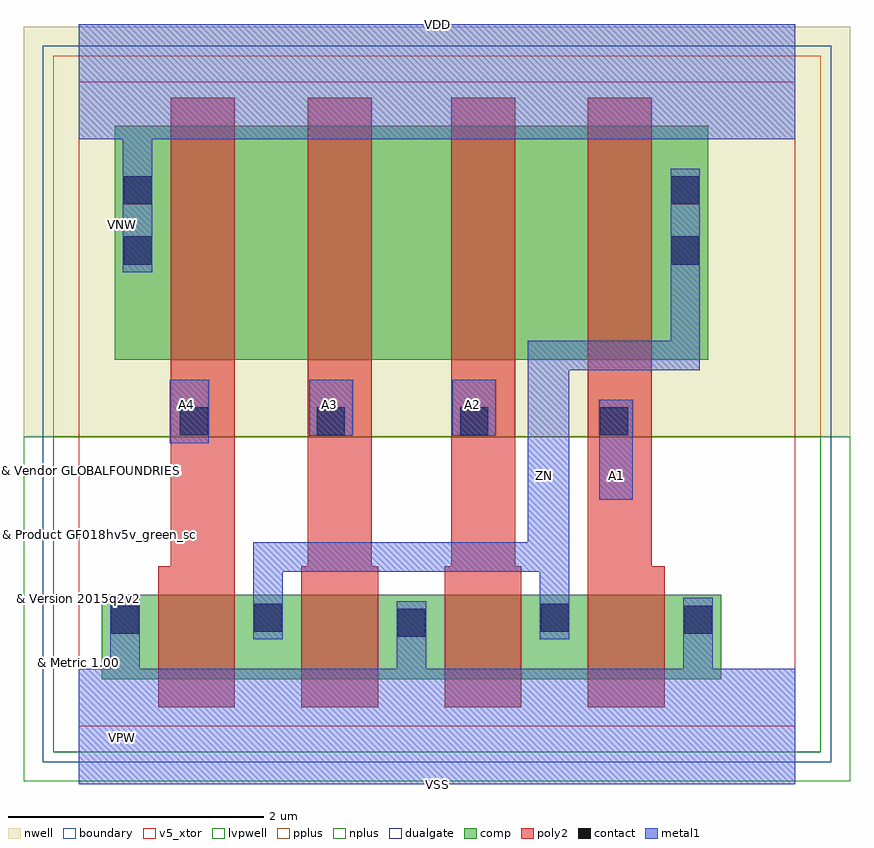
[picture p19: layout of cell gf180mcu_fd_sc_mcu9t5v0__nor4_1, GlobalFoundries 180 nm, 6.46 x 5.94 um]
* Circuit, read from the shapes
.subckt gf180mcu_fd_sc_mcu9t5v0__nor4_1 A1 A2 A3 A4 VDD VNW VSS ZN
XM1 ZN A4 VSS VSUBS nfet_05v0 w=0.66u l=0.6u
XM2 VSS A3 ZN VSUBS nfet_05v0 w=0.66u l=0.6u
XM3 ZN A2 VSS VSUBS nfet_05v0 w=0.66u l=0.6u
XM4 VSS A1 ZN VSUBS nfet_05v0 w=0.66u l=0.6u
XM5 n1 A4 VDD VNW pfet_05v0 w=1.83u l=0.5u
XM6 n2 A3 n1 VNW pfet_05v0 w=1.83u l=0.5u
XM7 n3 A2 n2 VNW pfet_05v0 w=1.83u l=0.5u
XM8 ZN A1 n3 VNW pfet_05v0 w=1.83u l=0.5u
.ends

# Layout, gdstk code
import gdstk
lib = gdstk.Library(unit=1e-6, precision=1e-09)
def R(c, l, rs):  # rectangles x0, y0, x1, y1
    for r in rs: c.add(gdstk.rectangle(r[:2], r[2:], *l))
def P(c, l, *ps):  # polygons
    for p in ps: c.add(gdstk.Polygon(p, *l))
boundary = (0, 0)
nwell = (21, 0)
comp = (22, 0)
poly2 = (30, 0)
pplus = (31, 0)
nplus = (32, 0)
contact = (33, 0)
metal1 = (34, 0)
dualgate = (55, 0)
v5_xtor = (112, 1)
lvpwell = (204, 0)

gf180mcu_fd_sc_mcu9t5v0_ = lib.new_cell('gf180mcu_fd_sc_mcu9t5v0__nor4_1')
R(gf180mcu_fd_sc_mcu9t5v0_, boundary, [(0,0,5.6,5.04)])
R(gf180mcu_fd_sc_mcu9t5v0_, nwell, [(-0.43,2.265,6.03,5.47)])
R(gf180mcu_fd_sc_mcu9t5v0_, comp, [(0.18,0.37,5.02,1.03), (0.28,2.865,4.92,4.695)])
P(gf180mcu_fd_sc_mcu9t5v0_, poly2, [(0.62,0.15),(0.62,1.25),(0.72,1.25),(0.72,4.915),(1.22,4.915),(1.22,0.15)],
  [(1.74,0.15),(1.74,1.25),(1.79,1.25),(1.79,4.915),(2.29,4.915),(2.29,1.25),(2.34,1.25),(2.34,0.15)],
  [(2.86,0.15),(2.86,1.25),(2.91,1.25),(2.91,4.915),(3.41,4.915),(3.41,1.25),(3.46,1.25),(3.46,0.15)],
  [(3.98,0.15),(3.98,4.915),(4.48,4.915),(4.48,1.25),(4.58,1.25),(4.58,0.15)])
R(gf180mcu_fd_sc_mcu9t5v0_, pplus, [(-0.2,2.265,5.8,5.24)])
R(gf180mcu_fd_sc_mcu9t5v0_, nplus, [(-0.2,-0.2,5.8,2.265)])
R(gf180mcu_fd_sc_mcu9t5v0_, contact, [(2.49,0.7,2.71,0.92), (0.25,0.725,0.47,0.945), (4.73,0.725,4.95,0.945), (1.37,0.74,1.59,0.96), (3.61,0.74,3.83,0.96), (0.79,2.275,1.01,2.495), (1.86,2.275,2.08,2.495), (2.98,2.275,3.2,2.495), (4.075,2.275,4.295,2.495), (0.35,3.61,0.57,3.83), (4.63,3.61,4.85,3.83), (0.35,4.08,0.57,4.3), (4.63,4.08,4.85,4.3)])
R(gf180mcu_fd_sc_mcu9t5v0_, metal1, [(4.07,1.77,4.33,2.555), (0.71,2.215,1.015,2.71), (1.8,2.27,2.14,2.71), (2.92,2.27,3.26,2.71)])
P(gf180mcu_fd_sc_mcu9t5v0_, metal1, [(1.365,0.68),(1.365,1.44),(3.51,1.44),(3.51,3.015),(4.625,3.015),(4.625,4.36),(4.855,4.36),(4.855,2.785),(3.835,2.785),(3.835,0.68),(3.605,0.68),(3.605,1.21),(1.595,1.21),(1.595,0.68)],
  [(0,-0.45),(0,0.45),(0.245,0.45),(0.245,1.005),(0.475,1.005),(0.475,0.45),(2.485,0.45),(2.485,0.98),(2.715,0.98),(2.715,0.45),(4.725,0.45),(4.725,1.005),(4.955,1.005),(4.955,0.45),(5.6,0.45),(5.6,-0.45)],
  [(0.345,3.55),(0.345,4.59),(0,4.59),(0,5.49),(5.6,5.49),(5.6,4.59),(0.575,4.59),(0.575,3.55)])
R(gf180mcu_fd_sc_mcu9t5v0_, dualgate, [(-0.28,-0.28,5.88,5.32)])
R(gf180mcu_fd_sc_mcu9t5v0_, v5_xtor, [(0,0,5.6,5.04)])
R(gf180mcu_fd_sc_mcu9t5v0_, lvpwell, [(-0.43,-0.43,6.03,2.265)])
gf180mcu_fd_sc_mcu9t5v0_.add(gdstk.Label('A1', (4.2,1.96), layer=34, texttype=10))
gf180mcu_fd_sc_mcu9t5v0_.add(gdstk.Label('A2', (3.08,2.52), layer=34, texttype=10))
gf180mcu_fd_sc_mcu9t5v0_.add(gdstk.Label('A3', (1.96,2.52), layer=34, texttype=10))
gf180mcu_fd_sc_mcu9t5v0_.add(gdstk.Label('A4', (0.84,2.52), layer=34, texttype=10))
gf180mcu_fd_sc_mcu9t5v0_.add(gdstk.Label('VDD', (2.8,5.49), layer=34, texttype=10))
gf180mcu_fd_sc_mcu9t5v0_.add(gdstk.Label('VSS', (2.8,-0.45), layer=34, texttype=10))
gf180mcu_fd_sc_mcu9t5v0_.add(gdstk.Label('ZN', (3.64,1.96), layer=34, texttype=10))
gf180mcu_fd_sc_mcu9t5v0_.add(gdstk.Label('& Vendor GLOBALFOUNDRIES', (0,2), layer=63, texttype=63))
gf180mcu_fd_sc_mcu9t5v0_.add(gdstk.Label('& Product GF018hv5v_green_sc9', (0,1.5), layer=63, texttype=63))
gf180mcu_fd_sc_mcu9t5v0_.add(gdstk.Label('& Version 2015q2v2', (0,1), layer=63, texttype=63))
gf180mcu_fd_sc_mcu9t5v0_.add(gdstk.Label('& Metric 1.00', (0,0.5), layer=63, texttype=63))
gf180mcu_fd_sc_mcu9t5v0_.add(gdstk.Label('VNW', (0.345,3.92), layer=21, texttype=10))
gf180mcu_fd_sc_mcu9t5v0_.add(gdstk.Label('VPW', (0.34,-0.085), layer=204, texttype=10))

lib.write_gds('gf180mcu_fd_sc_mcu9t5v0__nor4_1.gds')
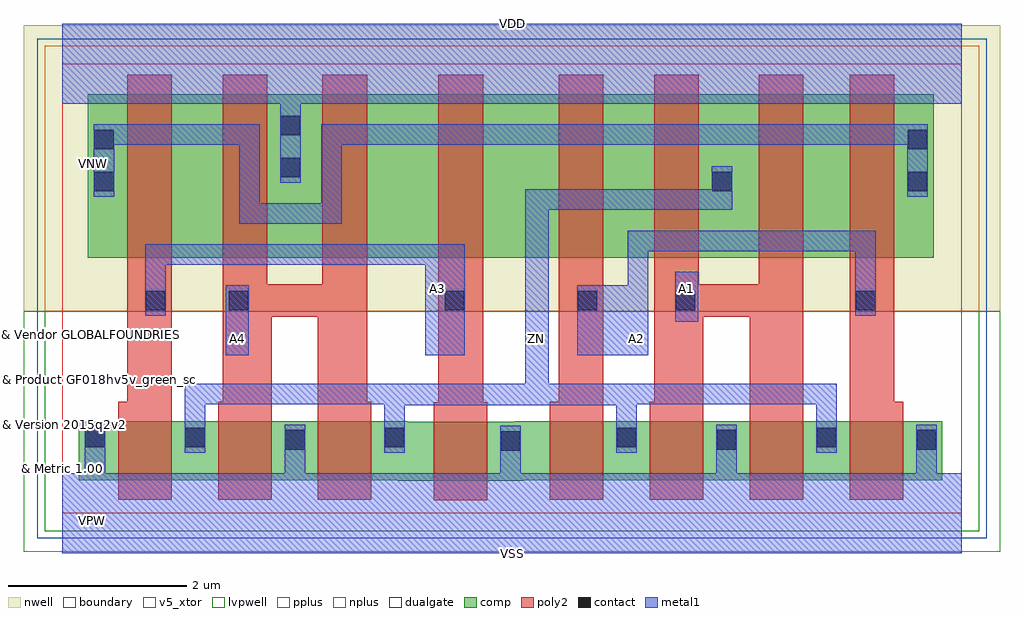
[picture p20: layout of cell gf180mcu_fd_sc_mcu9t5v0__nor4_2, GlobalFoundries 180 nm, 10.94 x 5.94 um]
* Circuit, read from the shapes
.subckt gf180mcu_fd_sc_mcu9t5v0__nor4_2 A1 A2 A3 A4 VDD VNW VSS ZN
XM1 ZN A3 VSS VSUBS nfet_05v0 w=0.66u l=0.6u m=2
XM2 VSS A4 ZN VSUBS nfet_05v0 w=0.66u l=0.6u m=2
XM3 ZN A2 VSS VSUBS nfet_05v0 w=0.66u l=0.6u m=2
XM4 VSS A1 ZN VSUBS nfet_05v0 w=0.66u l=0.6u m=2
XM5 n1 A3 n2 VNW pfet_05v0 w=1.83u l=0.5u
XM6 VDD A4 n1 VNW pfet_05v0 w=1.83u l=0.5u
XM7 n3 A4 VDD VNW pfet_05v0 w=1.83u l=0.5u
XM8 n4 A3 n3 VNW pfet_05v0 w=1.83u l=0.5u
XM9 n5 A2 n4 VNW pfet_05v0 w=1.83u l=0.5u
XM10 ZN A1 n5 VNW pfet_05v0 w=1.83u l=0.5u
XM11 n6 A1 ZN VNW pfet_05v0 w=1.83u l=0.5u
XM12 n2 A2 n6 VNW pfet_05v0 w=1.83u l=0.5u
.ends

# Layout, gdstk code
import gdstk
lib = gdstk.Library(unit=1e-6, precision=1e-09)
def R(c, l, rs):  # rectangles x0, y0, x1, y1
    for r in rs: c.add(gdstk.rectangle(r[:2], r[2:], *l))
def P(c, l, *ps):  # polygons
    for p in ps: c.add(gdstk.Polygon(p, *l))
boundary = (0, 0)
nwell = (21, 0)
comp = (22, 0)
poly2 = (30, 0)
pplus = (31, 0)
nplus = (32, 0)
contact = (33, 0)
metal1 = (34, 0)
dualgate = (55, 0)
v5_xtor = (112, 1)
lvpwell = (204, 0)

gf180mcu_fd_sc_mcu9t5v0_ = lib.new_cell('gf180mcu_fd_sc_mcu9t5v0__nor4_2')
R(gf180mcu_fd_sc_mcu9t5v0_, boundary, [(0,0,10.08,5.04)])
R(gf180mcu_fd_sc_mcu9t5v0_, nwell, [(-0.43,2.265,10.51,5.47)])
R(gf180mcu_fd_sc_mcu9t5v0_, comp, [(0.285,2.865,9.765,4.695)])
P(gf180mcu_fd_sc_mcu9t5v0_, comp, [(3.765,0.365),(3.765,0.37),(0.185,0.37),(0.185,1.03),(3.865,1.03),(3.865,1.025),(5.065,1.025),(5.065,1.03),(9.865,1.03),(9.865,0.37),(5.165,0.37),(5.165,0.365)])
P(gf180mcu_fd_sc_mcu9t5v0_, poly2, [(0.625,0.15),(0.625,1.25),(0.725,1.25),(0.725,4.915),(1.225,4.915),(1.225,0.15)],
  [(1.745,0.15),(1.745,1.25),(1.795,1.25),(1.795,4.915),(2.295,4.915),(2.295,2.565),(2.915,2.565),(2.915,4.915),(3.415,4.915),(3.415,1.25),(3.465,1.25),(3.465,0.15),(2.865,0.15),(2.865,2.205),(2.345,2.205),(2.345,0.15)],
  [(4.165,0.145),(4.165,1.245),(4.215,1.245),(4.215,4.915),(4.715,4.915),(4.715,1.245),(4.765,1.245),(4.765,0.145)],
  [(5.465,0.15),(5.465,1.25),(5.565,1.25),(5.565,4.915),(6.065,4.915),(6.065,0.15)],
  [(6.585,0.15),(6.585,1.25),(6.635,1.25),(6.635,4.915),(7.135,4.915),(7.135,2.565),(7.805,2.565),(7.805,4.915),(8.305,4.915),(8.305,0.15),(7.705,0.15),(7.705,2.205),(7.185,2.205),(7.185,0.15)],
  [(8.825,0.15),(8.825,4.915),(9.325,4.915),(9.325,1.25),(9.425,1.25),(9.425,0.15)])
R(gf180mcu_fd_sc_mcu9t5v0_, pplus, [(-0.2,2.265,10.28,5.24)])
R(gf180mcu_fd_sc_mcu9t5v0_, nplus, [(-0.2,-0.2,10.28,2.265)])
R(gf180mcu_fd_sc_mcu9t5v0_, contact, [(4.915,0.7,5.135,0.92), (2.495,0.715,2.715,0.935), (7.335,0.715,7.555,0.935), (9.575,0.715,9.795,0.935), (0.255,0.74,0.475,0.96), (1.375,0.74,1.595,0.96), (3.615,0.74,3.835,0.96), (6.215,0.74,6.435,0.96), (8.455,0.74,8.675,0.96), (0.935,2.275,1.155,2.495), (1.865,2.275,2.085,2.495), (4.285,2.275,4.505,2.495), (5.775,2.275,5.995,2.495), (6.875,2.275,7.095,2.495), (8.895,2.275,9.115,2.495), (0.355,3.61,0.575,3.83), (7.285,3.61,7.505,3.83), (9.475,3.61,9.695,3.83), (2.445,3.765,2.665,3.985), (0.355,4.08,0.575,4.3), (9.475,4.08,9.695,4.3), (2.445,4.235,2.665,4.455)])
R(gf180mcu_fd_sc_mcu9t5v0_, metal1, [(1.83,1.77,2.09,2.555), (6.87,2.15,7.13,2.71)])
P(gf180mcu_fd_sc_mcu9t5v0_, metal1, [(4.07,1.77),(4.07,2.785),(1.16,2.785),(1.16,2.215),(0.93,2.215),(0.93,3.015),(4.51,3.015),(4.51,1.77)],
  [(1.37,0.68),(1.37,1.455),(5.19,1.455),(5.19,3.63),(7.28,3.63),(7.28,3.89),(7.51,3.89),(7.51,3.4),(5.45,3.4),(5.45,1.455),(8.68,1.455),(8.68,0.68),(8.45,0.68),(8.45,1.225),(6.44,1.225),(6.44,0.68),(6.21,0.68),(6.21,1.21),(3.84,1.21),(3.84,0.68),(3.61,0.68),(3.61,1.225),(1.6,1.225),(1.6,0.68)],
  [(5.77,1.77),(5.77,2.555),(6.34,2.555),(6.34,3.17),(9.12,3.17),(9.12,2.215),(8.89,2.215),(8.89,2.94),(6.57,2.94),(6.57,1.77)],
  [(1.98,3.245),(1.98,4.13),(0.58,4.13),(0.58,3.55),(0.35,3.55),(0.35,4.36),(2.21,4.36),(2.21,3.475),(2.9,3.475),(2.9,4.36),(9.7,4.36),(9.7,3.55),(9.47,3.55),(9.47,4.13),(3.13,4.13),(3.13,3.245)],
  [(0,-0.45),(0,0.45),(0.25,0.45),(0.25,1.02),(0.48,1.02),(0.48,0.45),(2.49,0.45),(2.49,0.995),(2.72,0.995),(2.72,0.45),(4.91,0.45),(4.91,0.98),(5.14,0.98),(5.14,0.45),(7.33,0.45),(7.33,0.995),(7.56,0.995),(7.56,0.45),(9.57,0.45),(9.57,0.995),(9.8,0.995),(9.8,0.45),(10.08,0.45),(10.08,-0.45)],
  [(2.44,3.705),(2.44,4.59),(0,4.59),(0,5.49),(10.08,5.49),(10.08,4.59),(2.67,4.59),(2.67,3.705)])
R(gf180mcu_fd_sc_mcu9t5v0_, dualgate, [(-0.28,-0.28,10.36,5.32)])
R(gf180mcu_fd_sc_mcu9t5v0_, v5_xtor, [(0,0,10.08,5.04)])
R(gf180mcu_fd_sc_mcu9t5v0_, lvpwell, [(-0.43,-0.43,10.51,2.265)])
gf180mcu_fd_sc_mcu9t5v0_.add(gdstk.Label('A1', (7,2.52), layer=34, texttype=10))
gf180mcu_fd_sc_mcu9t5v0_.add(gdstk.Label('A2', (6.44,1.96), layer=34, texttype=10))
gf180mcu_fd_sc_mcu9t5v0_.add(gdstk.Label('A3', (4.2,2.52), layer=34, texttype=10))
gf180mcu_fd_sc_mcu9t5v0_.add(gdstk.Label('A4', (1.96,1.96), layer=34, texttype=10))
gf180mcu_fd_sc_mcu9t5v0_.add(gdstk.Label('VDD', (5.04,5.49), layer=34, texttype=10))
gf180mcu_fd_sc_mcu9t5v0_.add(gdstk.Label('VSS', (5.04,-0.45), layer=34, texttype=10))
gf180mcu_fd_sc_mcu9t5v0_.add(gdstk.Label('ZN', (5.32,1.96), layer=34, texttype=10))
gf180mcu_fd_sc_mcu9t5v0_.add(gdstk.Label('& Vendor GLOBALFOUNDRIES', (0,2), layer=63, texttype=63))
gf180mcu_fd_sc_mcu9t5v0_.add(gdstk.Label('& Product GF018hv5v_green_sc9', (0,1.5), layer=63, texttype=63))
gf180mcu_fd_sc_mcu9t5v0_.add(gdstk.Label('& Version 2015q2v2', (0,1), layer=63, texttype=63))
gf180mcu_fd_sc_mcu9t5v0_.add(gdstk.Label('& Metric 1.00', (0,0.5), layer=63, texttype=63))
gf180mcu_fd_sc_mcu9t5v0_.add(gdstk.Label('VNW', (0.345,3.92), layer=21, texttype=10))
gf180mcu_fd_sc_mcu9t5v0_.add(gdstk.Label('VPW', (0.34,-0.085), layer=204, texttype=10))

lib.write_gds('gf180mcu_fd_sc_mcu9t5v0__nor4_2.gds')
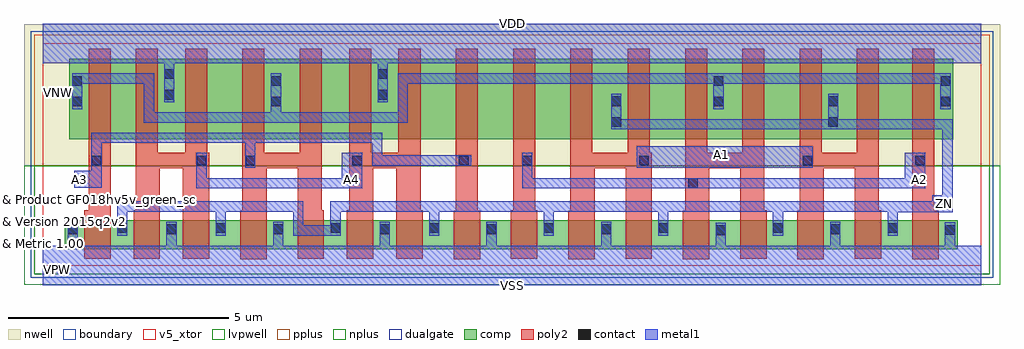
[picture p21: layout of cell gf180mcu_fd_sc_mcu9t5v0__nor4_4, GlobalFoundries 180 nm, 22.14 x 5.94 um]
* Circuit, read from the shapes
.subckt gf180mcu_fd_sc_mcu9t5v0__nor4_4 A1 A2 A3 A4 VDD VNW VSS ZN
XM1 ZN A3 VSS VSUBS nfet_05v0 w=0.66u l=0.6u m=4
XM2 VSS A4 ZN VSUBS nfet_05v0 w=0.66u l=0.6u m=4
XM3 ZN A2 VSS VSUBS nfet_05v0 w=0.66u l=0.6u m=4
XM4 VSS A1 ZN VSUBS nfet_05v0 w=0.66u l=0.6u m=4
XM5 n1 A3 n2 VNW pfet_05v0 w=1.83u l=0.5u
XM6 VDD A4 n1 VNW pfet_05v0 w=1.83u l=0.5u
XM7 n3 A4 VDD VNW pfet_05v0 w=1.83u l=0.5u
XM8 n2 A3 n3 VNW pfet_05v0 w=1.83u l=0.5u
XM9 n4 A3 n2 VNW pfet_05v0 w=1.83u l=0.5u
XM10 VDD A4 n4 VNW pfet_05v0 w=1.83u l=0.5u
XM11 n5 A4 VDD VNW pfet_05v0 w=1.83u l=0.5u
XM12 n6 A3 n5 VNW pfet_05v0 w=1.83u l=0.5u
XM13 n7 A2 n6 VNW pfet_05v0 w=1.83u l=0.5u
XM14 ZN A1 n7 VNW pfet_05v0 w=1.83u l=0.5u
XM15 n8 A1 ZN VNW pfet_05v0 w=1.83u l=0.5u
XM16 n2 A2 n8 VNW pfet_05v0 w=1.83u l=0.5u
XM17 n9 A2 n2 VNW pfet_05v0 w=1.83u l=0.5u
XM18 ZN A1 n9 VNW pfet_05v0 w=1.83u l=0.5u
XM19 n10 A1 ZN VNW pfet_05v0 w=1.83u l=0.5u
XM20 n2 A2 n10 VNW pfet_05v0 w=1.83u l=0.5u
.ends

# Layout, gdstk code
import gdstk
lib = gdstk.Library(unit=1e-6, precision=1e-09)
def R(c, l, rs):  # rectangles x0, y0, x1, y1
    for r in rs: c.add(gdstk.rectangle(r[:2], r[2:], *l))
def A(c, l, x, y, w, h, nx, ny, dx, dy):  # array of equal rectangles
    R(c, l, [(x+i*dx, y+j*dy, x+i*dx+w, y+j*dy+h) for i in range(nx) for j in range(ny)])
def P(c, l, *ps):  # polygons
    for p in ps: c.add(gdstk.Polygon(p, *l))
boundary = (0, 0)
nwell = (21, 0)
comp = (22, 0)
poly2 = (30, 0)
pplus = (31, 0)
nplus = (32, 0)
contact = (33, 0)
metal1 = (34, 0)
dualgate = (55, 0)
v5_xtor = (112, 1)
lvpwell = (204, 0)

gf180mcu_fd_sc_mcu9t5v0_ = lib.new_cell('gf180mcu_fd_sc_mcu9t5v0__nor4_4')
R(gf180mcu_fd_sc_mcu9t5v0_, boundary, [(0,0,21.28,5.04)])
R(gf180mcu_fd_sc_mcu9t5v0_, nwell, [(-0.43,2.265,21.71,5.47)])
R(gf180mcu_fd_sc_mcu9t5v0_, comp, [(0.595,2.865,20.655,4.695)])
P(gf180mcu_fd_sc_mcu9t5v0_, comp, [(4.075,0.365),(4.075,0.37),(0.495,0.37),(0.495,1.03),(4.175,1.03),(4.175,1.025),(5.375,1.025),(5.375,1.03),(9.015,1.03),(9.015,1.025),(10.215,1.025),(10.215,1.03),(11.615,1.03),(11.615,1.025),(12.815,1.025),(12.815,1.03),(14.215,1.03),(14.215,1.025),(15.415,1.025),(15.415,1.03),(16.815,1.03),(16.815,1.025),(18.015,1.025),(18.015,1.03),(19.415,1.03),(19.415,1.025),(20.755,1.025),(20.755,0.365),(19.315,0.365),(19.315,0.37),(18.115,0.37),(18.115,0.365),(16.715,0.365),(16.715,0.37),(15.515,0.37),(15.515,0.365),(14.115,0.365),(14.115,0.37),(12.915,0.37),(12.915,0.365),(11.515,0.365),(11.515,0.37),(10.315,0.37),(10.315,0.365),(8.915,0.365),(8.915,0.37),(5.475,0.37),(5.475,0.365)])
P(gf180mcu_fd_sc_mcu9t5v0_, poly2, [(0.935,0.15),(0.935,1.25),(1.035,1.25),(1.035,4.915),(1.535,4.915),(1.535,0.15)],
  [(2.055,0.15),(2.055,1.25),(2.105,1.25),(2.105,4.915),(2.605,4.915),(2.605,2.565),(3.225,2.565),(3.225,4.915),(3.725,4.915),(3.725,2.565),(3.775,2.565),(3.775,0.15),(3.175,0.15),(3.175,2.205),(2.655,2.205),(2.655,0.15)],
  [(4.475,0.145),(4.475,1.245),(4.525,1.245),(4.525,4.915),(5.025,4.915),(5.025,2.565),(5.825,2.565),(5.825,4.915),(6.325,4.915),(6.325,1.25),(6.375,1.25),(6.375,0.15),(5.775,0.15),(5.775,2.205),(5.075,2.205),(5.075,0.145)],
  [(6.895,0.15),(6.895,1.25),(6.945,1.25),(6.945,4.915),(7.445,4.915),(7.445,2.565),(8.065,2.565),(8.065,4.915),(8.565,4.915),(8.565,1.25),(8.615,1.25),(8.615,0.15),(8.015,0.15),(8.015,2.205),(7.495,2.205),(7.495,0.15)],
  [(9.315,0.145),(9.315,1.245),(9.365,1.245),(9.365,4.915),(9.865,4.915),(9.865,1.245),(9.915,1.245),(9.915,0.145)],
  [(10.615,0.15),(10.615,1.25),(10.665,1.25),(10.665,4.915),(11.165,4.915),(11.165,1.25),(11.215,1.25),(11.215,0.15)],
  [(11.915,0.145),(11.915,1.245),(11.965,1.245),(11.965,4.915),(12.465,4.915),(12.465,2.565),(13.265,2.565),(13.265,4.915),(13.765,4.915),(13.765,2.565),(13.815,2.565),(13.815,0.15),(13.215,0.15),(13.215,2.205),(12.515,2.205),(12.515,0.145)],
  [(14.515,0.145),(14.515,1.245),(14.565,1.245),(14.565,4.915),(15.065,4.915),(15.065,2.565),(15.865,2.565),(15.865,4.915),(16.365,4.915),(16.365,1.25),(16.415,1.25),(16.415,0.15),(15.815,0.15),(15.815,2.205),(15.115,2.205),(15.115,0.145)],
  [(17.115,0.145),(17.115,1.245),(17.165,1.245),(17.165,4.915),(17.665,4.915),(17.665,2.565),(18.465,2.565),(18.465,4.915),(18.965,4.915),(18.965,1.25),(19.015,1.25),(19.015,0.15),(18.415,0.15),(18.415,2.205),(17.715,2.205),(17.715,0.145)],
  [(19.715,0.145),(19.715,4.915),(20.215,4.915),(20.215,1.245),(20.315,1.245),(20.315,0.145)])
R(gf180mcu_fd_sc_mcu9t5v0_, pplus, [(-0.2,2.265,21.48,5.24)])
R(gf180mcu_fd_sc_mcu9t5v0_, nplus, [(-0.2,-0.2,21.48,2.265)])
A(gf180mcu_fd_sc_mcu9t5v0_, contact, 2.805, 0.715, 0.22, 0.22, 4, 1, 2.42, 0)
A(gf180mcu_fd_sc_mcu9t5v0_, contact, 8.765, 0.74, 0.22, 0.22, 5, 1, 2.6, 0)
A(gf180mcu_fd_sc_mcu9t5v0_, contact, 4.595, 2.275, 0.22, 0.22, 3, 1, 2.42, 0)
R(gf180mcu_fd_sc_mcu9t5v0_, contact, [(15.265,0.69,15.485,0.91), (20.465,0.7,20.685,0.92), (0.565,0.715,0.785,0.935), (12.665,0.715,12.885,0.935), (17.865,0.715,18.085,0.935), (1.685,0.74,1.905,0.96), (3.925,0.74,4.145,0.96), (6.525,0.74,6.745,0.96), (14.635,1.76,14.855,1.98), (1.105,2.275,1.325,2.495), (3.485,2.275,3.705,2.495), (10.875,2.275,11.095,2.495), (13.525,2.275,13.745,2.495), (17.235,2.275,17.455,2.495), (19.785,2.275,20.005,2.495), (12.895,3.15,13.115,3.37), (17.815,3.15,18.035,3.37), (0.665,3.61,0.885,3.83), (5.175,3.61,5.395,3.83), (15.215,3.61,15.435,3.83), (20.365,3.61,20.585,3.83), (12.895,3.62,13.115,3.84), (17.815,3.62,18.035,3.84), (2.755,3.765,2.975,3.985), (7.595,3.765,7.815,3.985), (0.665,4.08,0.885,4.3), (5.175,4.08,5.395,4.3), (15.215,4.08,15.435,4.3), (20.365,4.08,20.585,4.3), (2.755,4.235,2.975,4.455), (7.595,4.235,7.815,4.455)])
R(gf180mcu_fd_sc_mcu9t5v0_, metal1, [(13.465,2.215,17.46,2.71)])
P(gf180mcu_fd_sc_mcu9t5v0_, metal1, [(3.48,1.755),(3.48,2.555),(3.71,2.555),(3.71,1.985),(6.78,1.985),(6.78,2.555),(7.24,2.555),(7.24,1.755)],
  [(0.71,1.77),(0.71,2.15),(1.1,2.15),(1.1,3.015),(7.7,3.015),(7.7,2.5),(9.715,2.5),(9.715,2.27),(7.47,2.27),(7.47,2.785),(4.82,2.785),(4.82,2.215),(4.59,2.215),(4.59,2.785),(1.33,2.785),(1.33,1.77)],
  [(10.87,1.755),(10.87,2.555),(11.1,2.555),(11.1,1.985),(19.55,1.985),(19.55,2.555),(20.01,2.555),(20.01,1.755)],
  [(2.29,3.245),(2.29,4.13),(0.89,4.13),(0.89,3.55),(0.66,3.55),(0.66,4.36),(2.52,4.36),(2.52,3.475),(5.17,3.475),(5.17,4.36),(5.4,4.36),(5.4,3.475),(8.05,3.475),(8.05,4.36),(20.59,4.36),(20.59,3.55),(20.36,3.55),(20.36,4.13),(15.44,4.13),(15.44,3.55),(15.21,3.55),(15.21,4.13),(8.28,4.13),(8.28,3.245)],
  [(1.68,0.68),(1.68,1.455),(5.91,1.455),(5.91,0.91),(6.52,0.91),(6.52,1.455),(20.175,1.455),(20.175,1.59),(20.405,1.59),(20.405,3.09),(12.89,3.09),(12.89,3.9),(13.12,3.9),(13.12,3.32),(17.81,3.32),(17.81,3.9),(18.04,3.9),(18.04,3.32),(20.635,3.32),(20.635,1.21),(19.39,1.21),(19.39,0.68),(19.16,0.68),(19.16,1.225),(16.79,1.225),(16.79,0.68),(16.56,0.68),(16.56,1.225),(14.19,1.225),(14.19,0.68),(13.96,0.68),(13.96,1.225),(11.59,1.225),(11.59,0.68),(11.36,0.68),(11.36,1.225),(8.99,1.225),(8.99,0.68),(8.76,0.68),(8.76,1.225),(6.75,1.225),(6.75,0.68),(5.68,0.68),(5.68,1.225),(4.15,1.225),(4.15,0.68),(3.92,0.68),(3.92,1.225),(1.91,1.225),(1.91,0.68)],
  [(0,-0.45),(0,0.45),(0.56,0.45),(0.56,0.995),(0.79,0.995),(0.79,0.45),(2.8,0.45),(2.8,0.995),(3.03,0.995),(3.03,0.45),(5.22,0.45),(5.22,0.995),(5.45,0.995),(5.45,0.45),(7.64,0.45),(7.64,0.995),(7.87,0.995),(7.87,0.45),(10.06,0.45),(10.06,0.995),(10.29,0.995),(10.29,0.45),(12.66,0.45),(12.66,0.995),(12.89,0.995),(12.89,0.45),(15.26,0.45),(15.26,0.97),(15.49,0.97),(15.49,0.45),(17.86,0.45),(17.86,0.995),(18.09,0.995),(18.09,0.45),(20.46,0.45),(20.46,0.98),(20.69,0.98),(20.69,0.45),(21.28,0.45),(21.28,-0.45)],
  [(2.75,3.705),(2.75,4.59),(0,4.59),(0,5.49),(21.28,5.49),(21.28,4.59),(7.82,4.59),(7.82,3.705),(7.59,3.705),(7.59,4.59),(2.98,4.59),(2.98,3.705)])
R(gf180mcu_fd_sc_mcu9t5v0_, dualgate, [(-0.28,-0.28,21.56,5.32)])
R(gf180mcu_fd_sc_mcu9t5v0_, v5_xtor, [(0,0,21.28,5.04)])
R(gf180mcu_fd_sc_mcu9t5v0_, lvpwell, [(-0.43,-0.43,21.71,2.265)])
gf180mcu_fd_sc_mcu9t5v0_.add(gdstk.Label('A1', (15.4,2.52), layer=34, texttype=10))
gf180mcu_fd_sc_mcu9t5v0_.add(gdstk.Label('A2', (19.88,1.96), layer=34, texttype=10))
gf180mcu_fd_sc_mcu9t5v0_.add(gdstk.Label('A3', (0.84,1.96), layer=34, texttype=10))
gf180mcu_fd_sc_mcu9t5v0_.add(gdstk.Label('A4', (7,1.96), layer=34, texttype=10))
gf180mcu_fd_sc_mcu9t5v0_.add(gdstk.Label('VDD', (10.64,5.49), layer=34, texttype=10))
gf180mcu_fd_sc_mcu9t5v0_.add(gdstk.Label('VSS', (10.64,-0.45), layer=34, texttype=10))
gf180mcu_fd_sc_mcu9t5v0_.add(gdstk.Label('ZN', (20.44,1.4), layer=34, texttype=10))
gf180mcu_fd_sc_mcu9t5v0_.add(gdstk.Label('& Vendor GLOBALFOUNDRIES', (0,2), layer=63, texttype=63))
gf180mcu_fd_sc_mcu9t5v0_.add(gdstk.Label('& Product GF018hv5v_green_sc9', (0,1.5), layer=63, texttype=63))
gf180mcu_fd_sc_mcu9t5v0_.add(gdstk.Label('& Version 2015q2v2', (0,1), layer=63, texttype=63))
gf180mcu_fd_sc_mcu9t5v0_.add(gdstk.Label('& Metric 1.00', (0,0.5), layer=63, texttype=63))
gf180mcu_fd_sc_mcu9t5v0_.add(gdstk.Label('VNW', (0.345,3.92), layer=21, texttype=10))
gf180mcu_fd_sc_mcu9t5v0_.add(gdstk.Label('VPW', (0.34,-0.085), layer=204, texttype=10))

lib.write_gds('gf180mcu_fd_sc_mcu9t5v0__nor4_4.gds')
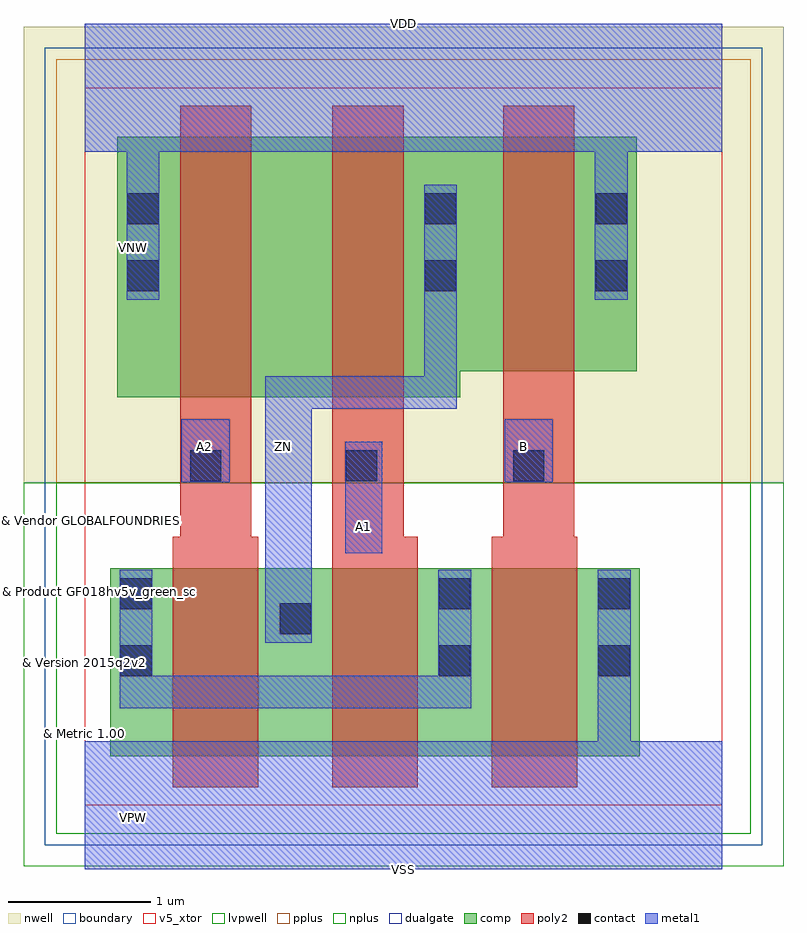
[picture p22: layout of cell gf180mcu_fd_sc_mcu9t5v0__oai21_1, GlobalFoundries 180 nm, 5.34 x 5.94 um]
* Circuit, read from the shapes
.subckt gf180mcu_fd_sc_mcu9t5v0__oai21_1 A1 A2 B VDD VNW VSS ZN
XM1 ZN A2 n1 VSUBS nfet_05v0 w=1.32u l=0.6u
XM2 n1 A1 ZN VSUBS nfet_05v0 w=1.32u l=0.6u
XM3 VSS B n1 VSUBS nfet_05v0 w=1.32u l=0.6u
XM4 n2 A2 VDD VNW pfet_05v0 w=1.83u l=0.5u
XM5 ZN A1 n2 VNW pfet_05v0 w=1.83u l=0.5u
XM6 VDD B ZN VNW pfet_05v0 w=1.645u l=0.5u
.ends

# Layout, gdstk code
import gdstk
lib = gdstk.Library(unit=1e-6, precision=1e-09)
def R(c, l, rs):  # rectangles x0, y0, x1, y1
    for r in rs: c.add(gdstk.rectangle(r[:2], r[2:], *l))
def P(c, l, *ps):  # polygons
    for p in ps: c.add(gdstk.Polygon(p, *l))
boundary = (0, 0)
nwell = (21, 0)
comp = (22, 0)
poly2 = (30, 0)
pplus = (31, 0)
nplus = (32, 0)
contact = (33, 0)
metal1 = (34, 0)
dualgate = (55, 0)
v5_xtor = (112, 1)
lvpwell = (204, 0)

gf180mcu_fd_sc_mcu9t5v0_ = lib.new_cell('gf180mcu_fd_sc_mcu9t5v0__oai21_1')
R(gf180mcu_fd_sc_mcu9t5v0_, boundary, [(0,0,4.48,5.04)])
R(gf180mcu_fd_sc_mcu9t5v0_, nwell, [(-0.43,2.265,4.91,5.47)])
R(gf180mcu_fd_sc_mcu9t5v0_, comp, [(0.18,0.345,3.9,1.665)])
P(gf180mcu_fd_sc_mcu9t5v0_, comp, [(0.23,2.865),(0.23,4.695),(3.88,4.695),(3.88,3.05),(2.64,3.05),(2.64,2.865)])
P(gf180mcu_fd_sc_mcu9t5v0_, poly2, [(0.62,0.125),(0.62,1.885),(0.67,1.885),(0.67,4.915),(1.17,4.915),(1.17,1.885),(1.22,1.885),(1.22,0.125)],
  [(1.74,0.125),(1.74,4.915),(2.24,4.915),(2.24,1.885),(2.34,1.885),(2.34,0.125)],
  [(2.86,0.125),(2.86,1.885),(2.94,1.885),(2.94,4.915),(3.44,4.915),(3.44,1.885),(3.46,1.885),(3.46,0.125)])
R(gf180mcu_fd_sc_mcu9t5v0_, pplus, [(-0.2,2.265,4.68,5.24)])
R(gf180mcu_fd_sc_mcu9t5v0_, nplus, [(-0.2,-0.2,4.68,2.265)])
R(gf180mcu_fd_sc_mcu9t5v0_, contact, [(0.25,0.905,0.47,1.125), (2.49,0.905,2.71,1.125), (3.61,0.905,3.83,1.125), (1.37,1.2,1.59,1.42), (0.25,1.375,0.47,1.595), (2.49,1.375,2.71,1.595), (3.61,1.375,3.83,1.595), (0.74,2.275,0.96,2.495), (1.835,2.275,2.055,2.495), (3.01,2.275,3.23,2.495), (0.3,3.61,0.52,3.83), (2.39,3.61,2.61,3.83), (3.59,3.61,3.81,3.83), (0.3,4.08,0.52,4.3), (2.39,4.08,2.61,4.3), (3.59,4.08,3.81,4.3)])
R(gf180mcu_fd_sc_mcu9t5v0_, metal1, [(1.83,1.77,2.09,2.555), (0.68,2.27,1.02,2.71), (2.95,2.27,3.29,2.71)])
P(gf180mcu_fd_sc_mcu9t5v0_, metal1, [(1.27,1.14),(1.27,3.015),(2.385,3.015),(2.385,4.36),(2.615,4.36),(2.615,2.785),(1.595,2.785),(1.595,1.14)],
  [(0.245,0.68),(0.245,1.655),(0.475,1.655),(0.475,0.91),(2.485,0.91),(2.485,1.655),(2.715,1.655),(2.715,0.68)],
  [(0,-0.45),(0,0.45),(3.605,0.45),(3.605,1.655),(3.835,1.655),(3.835,0.45),(4.48,0.45),(4.48,-0.45)],
  [(0.295,3.55),(0.295,4.59),(0,4.59),(0,5.49),(4.48,5.49),(4.48,4.59),(3.815,4.59),(3.815,3.55),(3.585,3.55),(3.585,4.59),(0.525,4.59),(0.525,3.55)])
R(gf180mcu_fd_sc_mcu9t5v0_, dualgate, [(-0.28,-0.28,4.76,5.32)])
R(gf180mcu_fd_sc_mcu9t5v0_, v5_xtor, [(0,0,4.48,5.04)])
R(gf180mcu_fd_sc_mcu9t5v0_, lvpwell, [(-0.43,-0.43,4.91,2.265)])
gf180mcu_fd_sc_mcu9t5v0_.add(gdstk.Label('A1', (1.96,1.96), layer=34, texttype=10))
gf180mcu_fd_sc_mcu9t5v0_.add(gdstk.Label('A2', (0.84,2.52), layer=34, texttype=10))
gf180mcu_fd_sc_mcu9t5v0_.add(gdstk.Label('B', (3.08,2.52), layer=34, texttype=10))
gf180mcu_fd_sc_mcu9t5v0_.add(gdstk.Label('VDD', (2.24,5.49), layer=34, texttype=10))
gf180mcu_fd_sc_mcu9t5v0_.add(gdstk.Label('VSS', (2.24,-0.45), layer=34, texttype=10))
gf180mcu_fd_sc_mcu9t5v0_.add(gdstk.Label('ZN', (1.4,2.52), layer=34, texttype=10))
gf180mcu_fd_sc_mcu9t5v0_.add(gdstk.Label('& Vendor GLOBALFOUNDRIES', (0,2), layer=63, texttype=63))
gf180mcu_fd_sc_mcu9t5v0_.add(gdstk.Label('& Product GF018hv5v_green_sc9', (0,1.5), layer=63, texttype=63))
gf180mcu_fd_sc_mcu9t5v0_.add(gdstk.Label('& Version 2015q2v2', (0,1), layer=63, texttype=63))
gf180mcu_fd_sc_mcu9t5v0_.add(gdstk.Label('& Metric 1.00', (0,0.5), layer=63, texttype=63))
gf180mcu_fd_sc_mcu9t5v0_.add(gdstk.Label('VNW', (0.345,3.92), layer=21, texttype=10))
gf180mcu_fd_sc_mcu9t5v0_.add(gdstk.Label('VPW', (0.34,-0.085), layer=204, texttype=10))

lib.write_gds('gf180mcu_fd_sc_mcu9t5v0__oai21_1.gds')
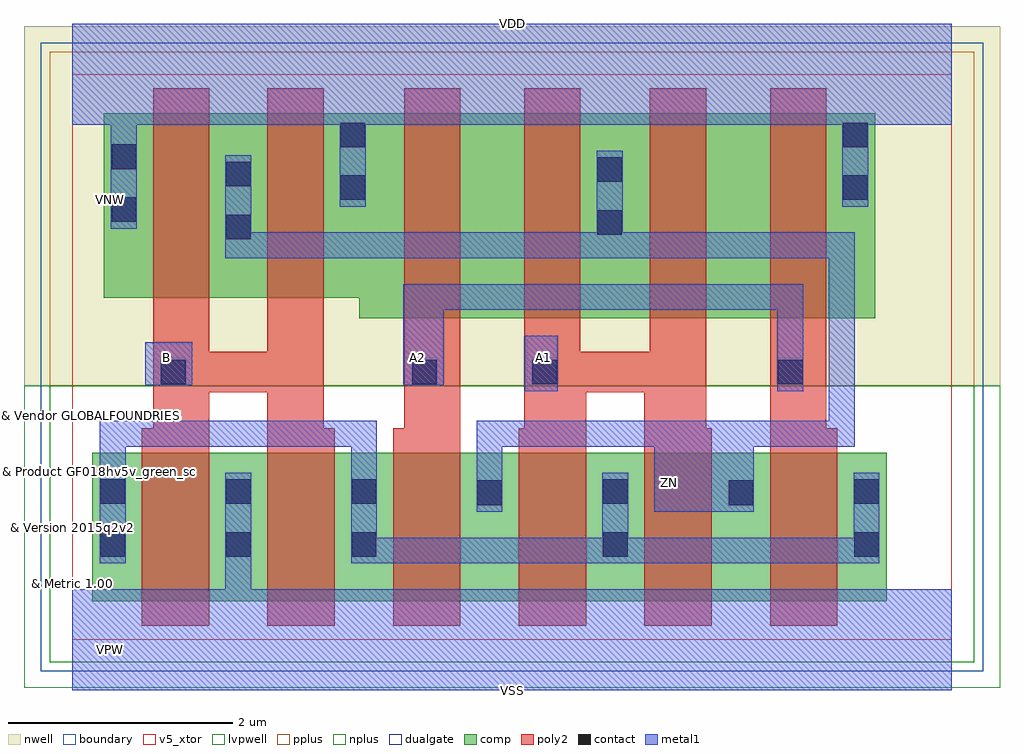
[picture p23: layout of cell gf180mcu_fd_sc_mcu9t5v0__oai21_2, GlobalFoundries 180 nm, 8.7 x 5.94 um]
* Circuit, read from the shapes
.subckt gf180mcu_fd_sc_mcu9t5v0__oai21_2 A1 A2 B VDD VNW VSS ZN
XM1 VSS B n1 VSUBS nfet_05v0 w=1.32u l=0.6u m=2
XM2 ZN A2 n1 VSUBS nfet_05v0 w=1.32u l=0.6u m=2
XM3 n1 A1 ZN VSUBS nfet_05v0 w=1.32u l=0.6u m=2
XM4 ZN B VDD VNW pfet_05v0 w=1.645u l=0.5u m=2
XM5 n2 A2 VDD VNW pfet_05v0 w=1.83u l=0.5u
XM6 ZN A1 n2 VNW pfet_05v0 w=1.83u l=0.5u
XM7 n3 A1 ZN VNW pfet_05v0 w=1.83u l=0.5u
XM8 VDD A2 n3 VNW pfet_05v0 w=1.83u l=0.5u
.ends

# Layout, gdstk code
import gdstk
lib = gdstk.Library(unit=1e-6, precision=1e-09)
def R(c, l, rs):  # rectangles x0, y0, x1, y1
    for r in rs: c.add(gdstk.rectangle(r[:2], r[2:], *l))
def A(c, l, x, y, w, h, nx, ny, dx, dy):  # array of equal rectangles
    R(c, l, [(x+i*dx, y+j*dy, x+i*dx+w, y+j*dy+h) for i in range(nx) for j in range(ny)])
def P(c, l, *ps):  # polygons
    for p in ps: c.add(gdstk.Polygon(p, *l))
boundary = (0, 0)
nwell = (21, 0)
comp = (22, 0)
poly2 = (30, 0)
pplus = (31, 0)
nplus = (32, 0)
contact = (33, 0)
metal1 = (34, 0)
dualgate = (55, 0)
v5_xtor = (112, 1)
lvpwell = (204, 0)

gf180mcu_fd_sc_mcu9t5v0_ = lib.new_cell('gf180mcu_fd_sc_mcu9t5v0__oai21_2')
R(gf180mcu_fd_sc_mcu9t5v0_, boundary, [(0,0,7.84,5.04)])
R(gf180mcu_fd_sc_mcu9t5v0_, nwell, [(-0.43,2.265,8.27,5.47)])
R(gf180mcu_fd_sc_mcu9t5v0_, comp, [(0.18,0.345,7.26,1.665)])
P(gf180mcu_fd_sc_mcu9t5v0_, comp, [(2.56,2.865),(2.56,3.05),(0.28,3.05),(0.28,4.695),(7.16,4.695),(7.16,2.865)])
P(gf180mcu_fd_sc_mcu9t5v0_, poly2, [(0.62,0.125),(0.62,1.885),(0.72,1.885),(0.72,4.915),(1.22,4.915),(1.22,2.565),(1.74,2.565),(1.74,4.915),(2.24,4.915),(2.24,1.885),(2.34,1.885),(2.34,0.125),(1.74,0.125),(1.74,2.205),(1.22,2.205),(1.22,0.125)],
  [(2.86,0.125),(2.86,1.885),(2.96,1.885),(2.96,4.915),(3.46,4.915),(3.46,0.125)],
  [(3.98,0.125),(3.98,1.885),(4.03,1.885),(4.03,4.915),(4.53,4.915),(4.53,2.565),(5.15,2.565),(5.15,4.915),(5.65,4.915),(5.65,1.885),(5.7,1.885),(5.7,0.125),(5.1,0.125),(5.1,2.205),(4.58,2.205),(4.58,0.125)],
  [(6.22,0.125),(6.22,4.915),(6.72,4.915),(6.72,1.885),(6.82,1.885),(6.82,0.125)])
R(gf180mcu_fd_sc_mcu9t5v0_, pplus, [(-0.2,2.265,8.04,5.24)])
R(gf180mcu_fd_sc_mcu9t5v0_, nplus, [(-0.2,-0.2,8.04,2.265)])
A(gf180mcu_fd_sc_mcu9t5v0_, contact, 0.25, 0.74, 0.22, 0.22, 3, 2, 1.12, 0.47)
R(gf180mcu_fd_sc_mcu9t5v0_, contact, [(4.73,0.74,4.95,0.96), (6.97,0.74,7.19,0.96), (3.61,1.2,3.83,1.42), (5.85,1.2,6.07,1.42), (4.73,1.21,4.95,1.43), (6.97,1.21,7.19,1.43), (0.79,2.275,1.01,2.495), (3.03,2.275,3.25,2.495), (4.1,2.275,4.32,2.495), (6.29,2.275,6.51,2.495), (1.37,3.57,1.59,3.79), (4.68,3.61,4.9,3.83), (0.35,3.725,0.57,3.945), (2.39,3.92,2.61,4.14), (6.87,3.92,7.09,4.14), (1.37,4.04,1.59,4.26), (4.68,4.08,4.9,4.3), (0.35,4.195,0.57,4.415), (2.39,4.39,2.61,4.61), (6.87,4.39,7.09,4.61)])
R(gf180mcu_fd_sc_mcu9t5v0_, metal1, [(4.035,2.215,4.33,2.71), (0.65,2.27,1.07,2.65)])
P(gf180mcu_fd_sc_mcu9t5v0_, metal1, [(6.285,2.215),(6.285,2.94),(3.31,2.94),(3.31,2.27),(2.95,2.27),(2.95,3.17),(6.515,3.17),(6.515,2.215)],
  [(3.605,1.14),(3.605,1.95),(6.745,1.95),(6.745,3.4),(1.365,3.4),(1.365,4.32),(1.595,4.32),(1.595,3.63),(4.675,3.63),(4.675,4.36),(4.905,4.36),(4.905,3.63),(6.975,3.63),(6.975,1.72),(6.075,1.72),(6.075,1.14),(5.19,1.14),(5.19,1.72),(3.835,1.72),(3.835,1.14)],
  [(0.245,0.68),(0.245,1.95),(2.715,1.95),(2.715,0.91),(4.725,0.91),(4.725,1.49),(4.955,1.49),(4.955,0.91),(6.965,0.91),(6.965,1.49),(7.195,1.49),(7.195,0.68),(2.485,0.68),(2.485,1.72),(0.475,1.72),(0.475,0.68)],
  [(0,-0.45),(0,0.45),(1.365,0.45),(1.365,1.49),(1.595,1.49),(1.595,0.45),(7.84,0.45),(7.84,-0.45)],
  [(0.345,3.665),(0.345,4.59),(0,4.59),(0,5.49),(7.84,5.49),(7.84,4.59),(7.095,4.59),(7.095,3.86),(6.865,3.86),(6.865,4.59),(2.615,4.59),(2.615,3.86),(2.385,3.86),(2.385,4.59),(0.575,4.59),(0.575,3.665)])
R(gf180mcu_fd_sc_mcu9t5v0_, dualgate, [(-0.28,-0.28,8.12,5.32)])
R(gf180mcu_fd_sc_mcu9t5v0_, v5_xtor, [(0,0,7.84,5.04)])
R(gf180mcu_fd_sc_mcu9t5v0_, lvpwell, [(-0.43,-0.43,8.27,2.265)])
gf180mcu_fd_sc_mcu9t5v0_.add(gdstk.Label('A1', (4.2,2.52), layer=34, texttype=10))
gf180mcu_fd_sc_mcu9t5v0_.add(gdstk.Label('A2', (3.08,2.52), layer=34, texttype=10))
gf180mcu_fd_sc_mcu9t5v0_.add(gdstk.Label('B', (0.84,2.52), layer=34, texttype=10))
gf180mcu_fd_sc_mcu9t5v0_.add(gdstk.Label('VDD', (3.92,5.49), layer=34, texttype=10))
gf180mcu_fd_sc_mcu9t5v0_.add(gdstk.Label('VSS', (3.92,-0.45), layer=34, texttype=10))
gf180mcu_fd_sc_mcu9t5v0_.add(gdstk.Label('ZN', (5.32,1.4), layer=34, texttype=10))
gf180mcu_fd_sc_mcu9t5v0_.add(gdstk.Label('& Vendor GLOBALFOUNDRIES', (0,2), layer=63, texttype=63))
gf180mcu_fd_sc_mcu9t5v0_.add(gdstk.Label('& Product GF018hv5v_green_sc9', (0,1.5), layer=63, texttype=63))
gf180mcu_fd_sc_mcu9t5v0_.add(gdstk.Label('& Version 2015q2v2', (0,1), layer=63, texttype=63))
gf180mcu_fd_sc_mcu9t5v0_.add(gdstk.Label('& Metric 1.00', (0,0.5), layer=63, texttype=63))
gf180mcu_fd_sc_mcu9t5v0_.add(gdstk.Label('VNW', (0.345,3.92), layer=21, texttype=10))
gf180mcu_fd_sc_mcu9t5v0_.add(gdstk.Label('VPW', (0.34,-0.085), layer=204, texttype=10))

lib.write_gds('gf180mcu_fd_sc_mcu9t5v0__oai21_2.gds')
